VERSION 5.8 ;
BUSBITCHARS "[]" ;
DIVIDERCHAR "/" ;
UNITS
    DATABASE MICRONS 1000 ;
END UNITS

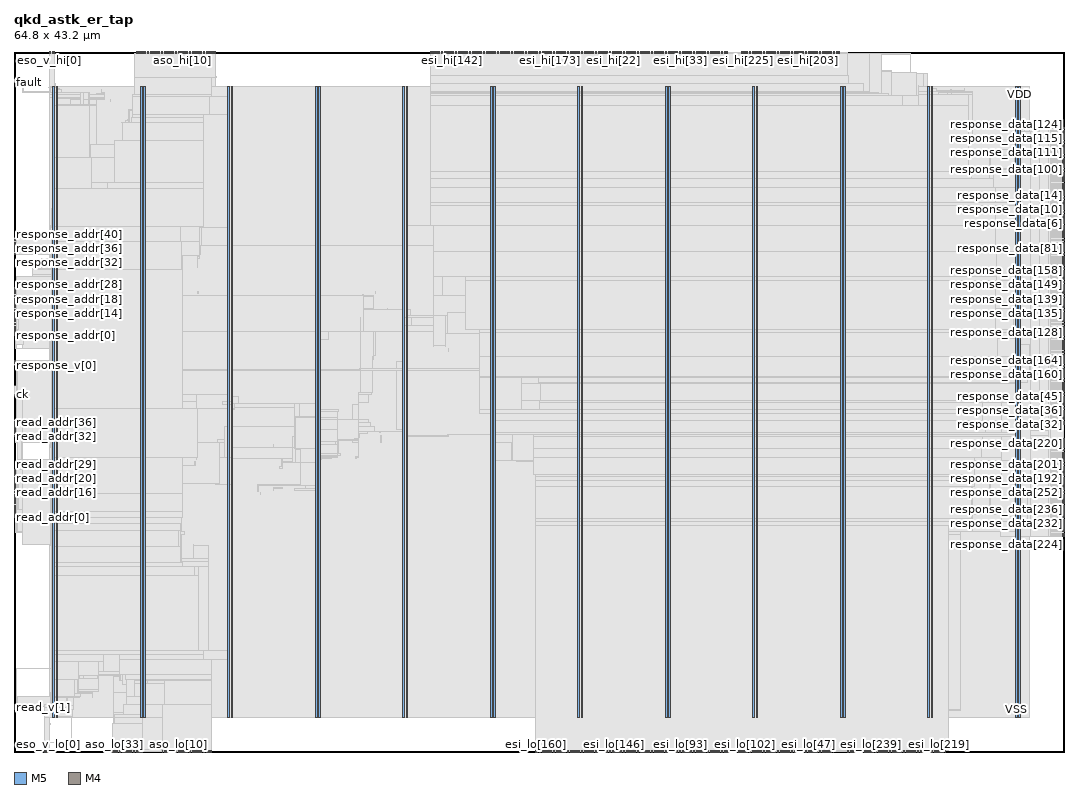
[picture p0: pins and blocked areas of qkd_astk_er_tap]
MACRO qkd_astk_er_tap
  FOREIGN qkd_astk_er_tap 0 0 ;
  CLASS BLOCK ;
  SIZE 64.8 BY 43.2 ;
  PIN aso_hi[0]
    DIRECTION OUTPUT ;
    USE SIGNAL ;
    PORT
      LAYER M5 ;
        RECT  9.456 43.116 9.48 43.2 ;
    END
  END aso_hi[0]
  PIN aso_hi[10]
    DIRECTION OUTPUT ;
    USE SIGNAL ;
    PORT
      LAYER M5 ;
        RECT  10.416 43.116 10.44 43.2 ;
    END
  END aso_hi[10]
  PIN aso_hi[11]
    DIRECTION OUTPUT ;
    USE SIGNAL ;
    PORT
      LAYER M5 ;
        RECT  10.512 43.116 10.536 43.2 ;
    END
  END aso_hi[11]
  PIN aso_hi[12]
    DIRECTION OUTPUT ;
    USE SIGNAL ;
    PORT
      LAYER M5 ;
        RECT  10.608 43.116 10.632 43.2 ;
    END
  END aso_hi[12]
  PIN aso_hi[13]
    DIRECTION OUTPUT ;
    USE SIGNAL ;
    PORT
      LAYER M5 ;
        RECT  10.704 43.116 10.728 43.2 ;
    END
  END aso_hi[13]
  PIN aso_hi[14]
    DIRECTION OUTPUT ;
    USE SIGNAL ;
    PORT
      LAYER M5 ;
        RECT  10.8 43.116 10.824 43.2 ;
    END
  END aso_hi[14]
  PIN aso_hi[15]
    DIRECTION OUTPUT ;
    USE SIGNAL ;
    PORT
      LAYER M5 ;
        RECT  10.896 43.116 10.92 43.2 ;
    END
  END aso_hi[15]
  PIN aso_hi[16]
    DIRECTION OUTPUT ;
    USE SIGNAL ;
    PORT
      LAYER M5 ;
        RECT  10.992 43.116 11.016 43.2 ;
    END
  END aso_hi[16]
  PIN aso_hi[17]
    DIRECTION OUTPUT ;
    USE SIGNAL ;
    PORT
      LAYER M5 ;
        RECT  11.088 43.116 11.112 43.2 ;
    END
  END aso_hi[17]
  PIN aso_hi[18]
    DIRECTION OUTPUT ;
    USE SIGNAL ;
    PORT
      LAYER M5 ;
        RECT  11.184 43.116 11.208 43.2 ;
    END
  END aso_hi[18]
  PIN aso_hi[19]
    DIRECTION OUTPUT ;
    USE SIGNAL ;
    PORT
      LAYER M5 ;
        RECT  11.28 43.116 11.304 43.2 ;
    END
  END aso_hi[19]
  PIN aso_hi[1]
    DIRECTION OUTPUT ;
    USE SIGNAL ;
    PORT
      LAYER M5 ;
        RECT  9.552 43.116 9.576 43.2 ;
    END
  END aso_hi[1]
  PIN aso_hi[20]
    DIRECTION OUTPUT ;
    USE SIGNAL ;
    PORT
      LAYER M5 ;
        RECT  11.376 43.116 11.4 43.2 ;
    END
  END aso_hi[20]
  PIN aso_hi[21]
    DIRECTION OUTPUT ;
    USE SIGNAL ;
    PORT
      LAYER M5 ;
        RECT  11.472 43.116 11.496 43.2 ;
    END
  END aso_hi[21]
  PIN aso_hi[22]
    DIRECTION OUTPUT ;
    USE SIGNAL ;
    PORT
      LAYER M5 ;
        RECT  11.568 43.116 11.592 43.2 ;
    END
  END aso_hi[22]
  PIN aso_hi[23]
    DIRECTION OUTPUT ;
    USE SIGNAL ;
    PORT
      LAYER M5 ;
        RECT  11.664 43.116 11.688 43.2 ;
    END
  END aso_hi[23]
  PIN aso_hi[24]
    DIRECTION OUTPUT ;
    USE SIGNAL ;
    PORT
      LAYER M5 ;
        RECT  11.76 43.116 11.784 43.2 ;
    END
  END aso_hi[24]
  PIN aso_hi[25]
    DIRECTION OUTPUT ;
    USE SIGNAL ;
    PORT
      LAYER M5 ;
        RECT  11.856 43.116 11.88 43.2 ;
    END
  END aso_hi[25]
  PIN aso_hi[26]
    DIRECTION OUTPUT ;
    USE SIGNAL ;
    PORT
      LAYER M5 ;
        RECT  11.952 43.116 11.976 43.2 ;
    END
  END aso_hi[26]
  PIN aso_hi[27]
    DIRECTION OUTPUT ;
    USE SIGNAL ;
    PORT
      LAYER M5 ;
        RECT  12.048 43.116 12.072 43.2 ;
    END
  END aso_hi[27]
  PIN aso_hi[28]
    DIRECTION OUTPUT ;
    USE SIGNAL ;
    PORT
      LAYER M5 ;
        RECT  12.144 43.116 12.168 43.2 ;
    END
  END aso_hi[28]
  PIN aso_hi[29]
    DIRECTION OUTPUT ;
    USE SIGNAL ;
    PORT
      LAYER M5 ;
        RECT  12.24 43.116 12.264 43.2 ;
    END
  END aso_hi[29]
  PIN aso_hi[2]
    DIRECTION OUTPUT ;
    USE SIGNAL ;
    PORT
      LAYER M5 ;
        RECT  9.648 43.116 9.672 43.2 ;
    END
  END aso_hi[2]
  PIN aso_hi[30]
    DIRECTION OUTPUT ;
    USE SIGNAL ;
    PORT
      LAYER M5 ;
        RECT  12.336 43.116 12.36 43.2 ;
    END
  END aso_hi[30]
  PIN aso_hi[31]
    DIRECTION OUTPUT ;
    USE SIGNAL ;
    PORT
      LAYER M5 ;
        RECT  12.432 43.116 12.456 43.2 ;
    END
  END aso_hi[31]
  PIN aso_hi[32]
    DIRECTION OUTPUT ;
    USE SIGNAL ;
    PORT
      LAYER M5 ;
        RECT  7.536 43.116 7.56 43.2 ;
    END
  END aso_hi[32]
  PIN aso_hi[33]
    DIRECTION OUTPUT ;
    USE SIGNAL ;
    PORT
      LAYER M5 ;
        RECT  7.632 43.116 7.656 43.2 ;
    END
  END aso_hi[33]
  PIN aso_hi[34]
    DIRECTION OUTPUT ;
    USE SIGNAL ;
    PORT
      LAYER M5 ;
        RECT  7.728 43.116 7.752 43.2 ;
    END
  END aso_hi[34]
  PIN aso_hi[35]
    DIRECTION OUTPUT ;
    USE SIGNAL ;
    PORT
      LAYER M5 ;
        RECT  7.824 43.116 7.848 43.2 ;
    END
  END aso_hi[35]
  PIN aso_hi[36]
    DIRECTION OUTPUT ;
    USE SIGNAL ;
    PORT
      LAYER M5 ;
        RECT  7.92 43.116 7.944 43.2 ;
    END
  END aso_hi[36]
  PIN aso_hi[37]
    DIRECTION OUTPUT ;
    USE SIGNAL ;
    PORT
      LAYER M5 ;
        RECT  8.016 43.116 8.04 43.2 ;
    END
  END aso_hi[37]
  PIN aso_hi[38]
    DIRECTION OUTPUT ;
    USE SIGNAL ;
    PORT
      LAYER M5 ;
        RECT  8.112 43.116 8.136 43.2 ;
    END
  END aso_hi[38]
  PIN aso_hi[39]
    DIRECTION OUTPUT ;
    USE SIGNAL ;
    PORT
      LAYER M5 ;
        RECT  8.208 43.116 8.232 43.2 ;
    END
  END aso_hi[39]
  PIN aso_hi[3]
    DIRECTION OUTPUT ;
    USE SIGNAL ;
    PORT
      LAYER M5 ;
        RECT  9.744 43.116 9.768 43.2 ;
    END
  END aso_hi[3]
  PIN aso_hi[40]
    DIRECTION OUTPUT ;
    USE SIGNAL ;
    PORT
      LAYER M5 ;
        RECT  8.304 43.116 8.328 43.2 ;
    END
  END aso_hi[40]
  PIN aso_hi[41]
    DIRECTION OUTPUT ;
    USE SIGNAL ;
    PORT
      LAYER M5 ;
        RECT  8.4 43.116 8.424 43.2 ;
    END
  END aso_hi[41]
  PIN aso_hi[42]
    DIRECTION OUTPUT ;
    USE SIGNAL ;
    PORT
      LAYER M5 ;
        RECT  8.496 43.116 8.52 43.2 ;
    END
  END aso_hi[42]
  PIN aso_hi[43]
    DIRECTION OUTPUT ;
    USE SIGNAL ;
    PORT
      LAYER M5 ;
        RECT  8.592 43.116 8.616 43.2 ;
    END
  END aso_hi[43]
  PIN aso_hi[44]
    DIRECTION OUTPUT ;
    USE SIGNAL ;
    PORT
      LAYER M5 ;
        RECT  8.688 43.116 8.712 43.2 ;
    END
  END aso_hi[44]
  PIN aso_hi[45]
    DIRECTION OUTPUT ;
    USE SIGNAL ;
    PORT
      LAYER M5 ;
        RECT  8.784 43.116 8.808 43.2 ;
    END
  END aso_hi[45]
  PIN aso_hi[46]
    DIRECTION OUTPUT ;
    USE SIGNAL ;
    PORT
      LAYER M5 ;
        RECT  8.88 43.116 8.904 43.2 ;
    END
  END aso_hi[46]
  PIN aso_hi[47]
    DIRECTION OUTPUT ;
    USE SIGNAL ;
    PORT
      LAYER M5 ;
        RECT  8.976 43.116 9 43.2 ;
    END
  END aso_hi[47]
  PIN aso_hi[48]
    DIRECTION OUTPUT ;
    USE SIGNAL ;
    PORT
      LAYER M5 ;
        RECT  9.072 43.116 9.096 43.2 ;
    END
  END aso_hi[48]
  PIN aso_hi[49]
    DIRECTION OUTPUT ;
    USE SIGNAL ;
    PORT
      LAYER M5 ;
        RECT  9.168 43.116 9.192 43.2 ;
    END
  END aso_hi[49]
  PIN aso_hi[4]
    DIRECTION OUTPUT ;
    USE SIGNAL ;
    PORT
      LAYER M5 ;
        RECT  9.84 43.116 9.864 43.2 ;
    END
  END aso_hi[4]
  PIN aso_hi[50]
    DIRECTION OUTPUT ;
    USE SIGNAL ;
    PORT
      LAYER M5 ;
        RECT  9.264 43.116 9.288 43.2 ;
    END
  END aso_hi[50]
  PIN aso_hi[51]
    DIRECTION OUTPUT ;
    USE SIGNAL ;
    PORT
      LAYER M5 ;
        RECT  9.36 43.116 9.384 43.2 ;
    END
  END aso_hi[51]
  PIN aso_hi[5]
    DIRECTION OUTPUT ;
    USE SIGNAL ;
    PORT
      LAYER M5 ;
        RECT  9.936 43.116 9.96 43.2 ;
    END
  END aso_hi[5]
  PIN aso_hi[6]
    DIRECTION OUTPUT ;
    USE SIGNAL ;
    PORT
      LAYER M5 ;
        RECT  10.032 43.116 10.056 43.2 ;
    END
  END aso_hi[6]
  PIN aso_hi[7]
    DIRECTION OUTPUT ;
    USE SIGNAL ;
    PORT
      LAYER M5 ;
        RECT  10.128 43.116 10.152 43.2 ;
    END
  END aso_hi[7]
  PIN aso_hi[8]
    DIRECTION OUTPUT ;
    USE SIGNAL ;
    PORT
      LAYER M5 ;
        RECT  10.224 43.116 10.248 43.2 ;
    END
  END aso_hi[8]
  PIN aso_hi[9]
    DIRECTION OUTPUT ;
    USE SIGNAL ;
    PORT
      LAYER M5 ;
        RECT  10.32 43.116 10.344 43.2 ;
    END
  END aso_hi[9]
  PIN aso_lo[0]
    DIRECTION OUTPUT ;
    USE SIGNAL ;
    PORT
      LAYER M5 ;
        RECT  9.168 0 9.192 0.084 ;
    END
  END aso_lo[0]
  PIN aso_lo[10]
    DIRECTION OUTPUT ;
    USE SIGNAL ;
    PORT
      LAYER M5 ;
        RECT  10.128 0 10.152 0.084 ;
    END
  END aso_lo[10]
  PIN aso_lo[11]
    DIRECTION OUTPUT ;
    USE SIGNAL ;
    PORT
      LAYER M5 ;
        RECT  10.224 0 10.248 0.084 ;
    END
  END aso_lo[11]
  PIN aso_lo[12]
    DIRECTION OUTPUT ;
    USE SIGNAL ;
    PORT
      LAYER M5 ;
        RECT  10.32 0 10.344 0.084 ;
    END
  END aso_lo[12]
  PIN aso_lo[13]
    DIRECTION OUTPUT ;
    USE SIGNAL ;
    PORT
      LAYER M5 ;
        RECT  10.416 0 10.44 0.084 ;
    END
  END aso_lo[13]
  PIN aso_lo[14]
    DIRECTION OUTPUT ;
    USE SIGNAL ;
    PORT
      LAYER M5 ;
        RECT  10.512 0 10.536 0.084 ;
    END
  END aso_lo[14]
  PIN aso_lo[15]
    DIRECTION OUTPUT ;
    USE SIGNAL ;
    PORT
      LAYER M5 ;
        RECT  10.608 0 10.632 0.084 ;
    END
  END aso_lo[15]
  PIN aso_lo[16]
    DIRECTION OUTPUT ;
    USE SIGNAL ;
    PORT
      LAYER M5 ;
        RECT  10.704 0 10.728 0.084 ;
    END
  END aso_lo[16]
  PIN aso_lo[17]
    DIRECTION OUTPUT ;
    USE SIGNAL ;
    PORT
      LAYER M5 ;
        RECT  10.8 0 10.824 0.084 ;
    END
  END aso_lo[17]
  PIN aso_lo[18]
    DIRECTION OUTPUT ;
    USE SIGNAL ;
    PORT
      LAYER M5 ;
        RECT  10.896 0 10.92 0.084 ;
    END
  END aso_lo[18]
  PIN aso_lo[19]
    DIRECTION OUTPUT ;
    USE SIGNAL ;
    PORT
      LAYER M5 ;
        RECT  10.992 0 11.016 0.084 ;
    END
  END aso_lo[19]
  PIN aso_lo[1]
    DIRECTION OUTPUT ;
    USE SIGNAL ;
    PORT
      LAYER M5 ;
        RECT  9.264 0 9.288 0.084 ;
    END
  END aso_lo[1]
  PIN aso_lo[20]
    DIRECTION OUTPUT ;
    USE SIGNAL ;
    PORT
      LAYER M5 ;
        RECT  11.088 0 11.112 0.084 ;
    END
  END aso_lo[20]
  PIN aso_lo[21]
    DIRECTION OUTPUT ;
    USE SIGNAL ;
    PORT
      LAYER M5 ;
        RECT  11.184 0 11.208 0.084 ;
    END
  END aso_lo[21]
  PIN aso_lo[22]
    DIRECTION OUTPUT ;
    USE SIGNAL ;
    PORT
      LAYER M5 ;
        RECT  11.28 0 11.304 0.084 ;
    END
  END aso_lo[22]
  PIN aso_lo[23]
    DIRECTION OUTPUT ;
    USE SIGNAL ;
    PORT
      LAYER M5 ;
        RECT  11.376 0 11.4 0.084 ;
    END
  END aso_lo[23]
  PIN aso_lo[24]
    DIRECTION OUTPUT ;
    USE SIGNAL ;
    PORT
      LAYER M5 ;
        RECT  11.472 0 11.496 0.084 ;
    END
  END aso_lo[24]
  PIN aso_lo[25]
    DIRECTION OUTPUT ;
    USE SIGNAL ;
    PORT
      LAYER M5 ;
        RECT  11.568 0 11.592 0.084 ;
    END
  END aso_lo[25]
  PIN aso_lo[26]
    DIRECTION OUTPUT ;
    USE SIGNAL ;
    PORT
      LAYER M5 ;
        RECT  11.664 0 11.688 0.084 ;
    END
  END aso_lo[26]
  PIN aso_lo[27]
    DIRECTION OUTPUT ;
    USE SIGNAL ;
    PORT
      LAYER M5 ;
        RECT  11.76 0 11.784 0.084 ;
    END
  END aso_lo[27]
  PIN aso_lo[28]
    DIRECTION OUTPUT ;
    USE SIGNAL ;
    PORT
      LAYER M5 ;
        RECT  11.856 0 11.88 0.084 ;
    END
  END aso_lo[28]
  PIN aso_lo[29]
    DIRECTION OUTPUT ;
    USE SIGNAL ;
    PORT
      LAYER M5 ;
        RECT  11.952 0 11.976 0.084 ;
    END
  END aso_lo[29]
  PIN aso_lo[2]
    DIRECTION OUTPUT ;
    USE SIGNAL ;
    PORT
      LAYER M5 ;
        RECT  9.36 0 9.384 0.084 ;
    END
  END aso_lo[2]
  PIN aso_lo[30]
    DIRECTION OUTPUT ;
    USE SIGNAL ;
    PORT
      LAYER M5 ;
        RECT  12.048 0 12.072 0.084 ;
    END
  END aso_lo[30]
  PIN aso_lo[31]
    DIRECTION OUTPUT ;
    USE SIGNAL ;
    PORT
      LAYER M5 ;
        RECT  12.144 0 12.168 0.084 ;
    END
  END aso_lo[31]
  PIN aso_lo[32]
    DIRECTION OUTPUT ;
    USE SIGNAL ;
    PORT
      LAYER M5 ;
        RECT  6.096 0 6.12 0.084 ;
    END
  END aso_lo[32]
  PIN aso_lo[33]
    DIRECTION OUTPUT ;
    USE SIGNAL ;
    PORT
      LAYER M5 ;
        RECT  6.192 0 6.216 0.084 ;
    END
  END aso_lo[33]
  PIN aso_lo[34]
    DIRECTION OUTPUT ;
    USE SIGNAL ;
    PORT
      LAYER M5 ;
        RECT  6.288 0 6.312 0.084 ;
    END
  END aso_lo[34]
  PIN aso_lo[35]
    DIRECTION OUTPUT ;
    USE SIGNAL ;
    PORT
      LAYER M5 ;
        RECT  6.384 0 6.408 0.084 ;
    END
  END aso_lo[35]
  PIN aso_lo[36]
    DIRECTION OUTPUT ;
    USE SIGNAL ;
    PORT
      LAYER M5 ;
        RECT  6.48 0 6.504 0.084 ;
    END
  END aso_lo[36]
  PIN aso_lo[37]
    DIRECTION OUTPUT ;
    USE SIGNAL ;
    PORT
      LAYER M5 ;
        RECT  6.576 0 6.6 0.084 ;
    END
  END aso_lo[37]
  PIN aso_lo[38]
    DIRECTION OUTPUT ;
    USE SIGNAL ;
    PORT
      LAYER M5 ;
        RECT  6.672 0 6.696 0.084 ;
    END
  END aso_lo[38]
  PIN aso_lo[39]
    DIRECTION OUTPUT ;
    USE SIGNAL ;
    PORT
      LAYER M5 ;
        RECT  6.768 0 6.792 0.084 ;
    END
  END aso_lo[39]
  PIN aso_lo[3]
    DIRECTION OUTPUT ;
    USE SIGNAL ;
    PORT
      LAYER M5 ;
        RECT  9.456 0 9.48 0.084 ;
    END
  END aso_lo[3]
  PIN aso_lo[40]
    DIRECTION OUTPUT ;
    USE SIGNAL ;
    PORT
      LAYER M5 ;
        RECT  6.864 0 6.888 0.084 ;
    END
  END aso_lo[40]
  PIN aso_lo[41]
    DIRECTION OUTPUT ;
    USE SIGNAL ;
    PORT
      LAYER M5 ;
        RECT  6.96 0 6.984 0.084 ;
    END
  END aso_lo[41]
  PIN aso_lo[42]
    DIRECTION OUTPUT ;
    USE SIGNAL ;
    PORT
      LAYER M5 ;
        RECT  7.056 0 7.08 0.084 ;
    END
  END aso_lo[42]
  PIN aso_lo[43]
    DIRECTION OUTPUT ;
    USE SIGNAL ;
    PORT
      LAYER M5 ;
        RECT  7.152 0 7.176 0.084 ;
    END
  END aso_lo[43]
  PIN aso_lo[44]
    DIRECTION OUTPUT ;
    USE SIGNAL ;
    PORT
      LAYER M5 ;
        RECT  7.248 0 7.272 0.084 ;
    END
  END aso_lo[44]
  PIN aso_lo[45]
    DIRECTION OUTPUT ;
    USE SIGNAL ;
    PORT
      LAYER M5 ;
        RECT  7.344 0 7.368 0.084 ;
    END
  END aso_lo[45]
  PIN aso_lo[46]
    DIRECTION OUTPUT ;
    USE SIGNAL ;
    PORT
      LAYER M5 ;
        RECT  7.44 0 7.464 0.084 ;
    END
  END aso_lo[46]
  PIN aso_lo[47]
    DIRECTION OUTPUT ;
    USE SIGNAL ;
    PORT
      LAYER M5 ;
        RECT  7.536 0 7.56 0.084 ;
    END
  END aso_lo[47]
  PIN aso_lo[48]
    DIRECTION OUTPUT ;
    USE SIGNAL ;
    PORT
      LAYER M5 ;
        RECT  7.632 0 7.656 0.084 ;
    END
  END aso_lo[48]
  PIN aso_lo[49]
    DIRECTION OUTPUT ;
    USE SIGNAL ;
    PORT
      LAYER M5 ;
        RECT  7.728 0 7.752 0.084 ;
    END
  END aso_lo[49]
  PIN aso_lo[4]
    DIRECTION OUTPUT ;
    USE SIGNAL ;
    PORT
      LAYER M5 ;
        RECT  9.552 0 9.576 0.084 ;
    END
  END aso_lo[4]
  PIN aso_lo[50]
    DIRECTION OUTPUT ;
    USE SIGNAL ;
    PORT
      LAYER M5 ;
        RECT  7.824 0 7.848 0.084 ;
    END
  END aso_lo[50]
  PIN aso_lo[51]
    DIRECTION OUTPUT ;
    USE SIGNAL ;
    PORT
      LAYER M5 ;
        RECT  7.92 0 7.944 0.084 ;
    END
  END aso_lo[51]
  PIN aso_lo[5]
    DIRECTION OUTPUT ;
    USE SIGNAL ;
    PORT
      LAYER M5 ;
        RECT  9.648 0 9.672 0.084 ;
    END
  END aso_lo[5]
  PIN aso_lo[6]
    DIRECTION OUTPUT ;
    USE SIGNAL ;
    PORT
      LAYER M5 ;
        RECT  9.744 0 9.768 0.084 ;
    END
  END aso_lo[6]
  PIN aso_lo[7]
    DIRECTION OUTPUT ;
    USE SIGNAL ;
    PORT
      LAYER M5 ;
        RECT  9.84 0 9.864 0.084 ;
    END
  END aso_lo[7]
  PIN aso_lo[8]
    DIRECTION OUTPUT ;
    USE SIGNAL ;
    PORT
      LAYER M5 ;
        RECT  9.936 0 9.96 0.084 ;
    END
  END aso_lo[8]
  PIN aso_lo[9]
    DIRECTION OUTPUT ;
    USE SIGNAL ;
    PORT
      LAYER M5 ;
        RECT  10.032 0 10.056 0.084 ;
    END
  END aso_lo[9]
  PIN ck
    DIRECTION INPUT ;
    USE SIGNAL ;
    PORT
      LAYER M4 ;
        RECT  0 22.032 0.084 22.056 ;
    END
  END ck
  PIN esi_hi[0]
    DIRECTION INPUT ;
    USE SIGNAL ;
    PORT
      LAYER M5 ;
        RECT  34.896 43.116 34.92 43.2 ;
    END
  END esi_hi[0]
  PIN esi_hi[100]
    DIRECTION INPUT ;
    USE SIGNAL ;
    PORT
      LAYER M5 ;
        RECT  29.136 43.116 29.16 43.2 ;
    END
  END esi_hi[100]
  PIN esi_hi[101]
    DIRECTION INPUT ;
    USE SIGNAL ;
    PORT
      LAYER M5 ;
        RECT  29.232 43.116 29.256 43.2 ;
    END
  END esi_hi[101]
  PIN esi_hi[102]
    DIRECTION INPUT ;
    USE SIGNAL ;
    PORT
      LAYER M5 ;
        RECT  29.328 43.116 29.352 43.2 ;
    END
  END esi_hi[102]
  PIN esi_hi[103]
    DIRECTION INPUT ;
    USE SIGNAL ;
    PORT
      LAYER M5 ;
        RECT  29.424 43.116 29.448 43.2 ;
    END
  END esi_hi[103]
  PIN esi_hi[104]
    DIRECTION INPUT ;
    USE SIGNAL ;
    PORT
      LAYER M5 ;
        RECT  29.52 43.116 29.544 43.2 ;
    END
  END esi_hi[104]
  PIN esi_hi[105]
    DIRECTION INPUT ;
    USE SIGNAL ;
    PORT
      LAYER M5 ;
        RECT  29.616 43.116 29.64 43.2 ;
    END
  END esi_hi[105]
  PIN esi_hi[106]
    DIRECTION INPUT ;
    USE SIGNAL ;
    PORT
      LAYER M5 ;
        RECT  29.712 43.116 29.736 43.2 ;
    END
  END esi_hi[106]
  PIN esi_hi[107]
    DIRECTION INPUT ;
    USE SIGNAL ;
    PORT
      LAYER M5 ;
        RECT  29.808 43.116 29.832 43.2 ;
    END
  END esi_hi[107]
  PIN esi_hi[108]
    DIRECTION INPUT ;
    USE SIGNAL ;
    PORT
      LAYER M5 ;
        RECT  29.904 43.116 29.928 43.2 ;
    END
  END esi_hi[108]
  PIN esi_hi[109]
    DIRECTION INPUT ;
    USE SIGNAL ;
    PORT
      LAYER M5 ;
        RECT  30 43.116 30.024 43.2 ;
    END
  END esi_hi[109]
  PIN esi_hi[10]
    DIRECTION INPUT ;
    USE SIGNAL ;
    PORT
      LAYER M5 ;
        RECT  35.856 43.116 35.88 43.2 ;
    END
  END esi_hi[10]
  PIN esi_hi[110]
    DIRECTION INPUT ;
    USE SIGNAL ;
    PORT
      LAYER M5 ;
        RECT  30.096 43.116 30.12 43.2 ;
    END
  END esi_hi[110]
  PIN esi_hi[111]
    DIRECTION INPUT ;
    USE SIGNAL ;
    PORT
      LAYER M5 ;
        RECT  30.192 43.116 30.216 43.2 ;
    END
  END esi_hi[111]
  PIN esi_hi[112]
    DIRECTION INPUT ;
    USE SIGNAL ;
    PORT
      LAYER M5 ;
        RECT  30.288 43.116 30.312 43.2 ;
    END
  END esi_hi[112]
  PIN esi_hi[113]
    DIRECTION INPUT ;
    USE SIGNAL ;
    PORT
      LAYER M5 ;
        RECT  30.384 43.116 30.408 43.2 ;
    END
  END esi_hi[113]
  PIN esi_hi[114]
    DIRECTION INPUT ;
    USE SIGNAL ;
    PORT
      LAYER M5 ;
        RECT  30.48 43.116 30.504 43.2 ;
    END
  END esi_hi[114]
  PIN esi_hi[115]
    DIRECTION INPUT ;
    USE SIGNAL ;
    PORT
      LAYER M5 ;
        RECT  30.576 43.116 30.6 43.2 ;
    END
  END esi_hi[115]
  PIN esi_hi[116]
    DIRECTION INPUT ;
    USE SIGNAL ;
    PORT
      LAYER M5 ;
        RECT  30.672 43.116 30.696 43.2 ;
    END
  END esi_hi[116]
  PIN esi_hi[117]
    DIRECTION INPUT ;
    USE SIGNAL ;
    PORT
      LAYER M5 ;
        RECT  30.768 43.116 30.792 43.2 ;
    END
  END esi_hi[117]
  PIN esi_hi[118]
    DIRECTION INPUT ;
    USE SIGNAL ;
    PORT
      LAYER M5 ;
        RECT  30.864 43.116 30.888 43.2 ;
    END
  END esi_hi[118]
  PIN esi_hi[119]
    DIRECTION INPUT ;
    USE SIGNAL ;
    PORT
      LAYER M5 ;
        RECT  30.96 43.116 30.984 43.2 ;
    END
  END esi_hi[119]
  PIN esi_hi[11]
    DIRECTION INPUT ;
    USE SIGNAL ;
    PORT
      LAYER M5 ;
        RECT  35.952 43.116 35.976 43.2 ;
    END
  END esi_hi[11]
  PIN esi_hi[120]
    DIRECTION INPUT ;
    USE SIGNAL ;
    PORT
      LAYER M5 ;
        RECT  31.056 43.116 31.08 43.2 ;
    END
  END esi_hi[120]
  PIN esi_hi[121]
    DIRECTION INPUT ;
    USE SIGNAL ;
    PORT
      LAYER M5 ;
        RECT  31.152 43.116 31.176 43.2 ;
    END
  END esi_hi[121]
  PIN esi_hi[122]
    DIRECTION INPUT ;
    USE SIGNAL ;
    PORT
      LAYER M5 ;
        RECT  31.248 43.116 31.272 43.2 ;
    END
  END esi_hi[122]
  PIN esi_hi[123]
    DIRECTION INPUT ;
    USE SIGNAL ;
    PORT
      LAYER M5 ;
        RECT  31.344 43.116 31.368 43.2 ;
    END
  END esi_hi[123]
  PIN esi_hi[124]
    DIRECTION INPUT ;
    USE SIGNAL ;
    PORT
      LAYER M5 ;
        RECT  31.44 43.116 31.464 43.2 ;
    END
  END esi_hi[124]
  PIN esi_hi[125]
    DIRECTION INPUT ;
    USE SIGNAL ;
    PORT
      LAYER M5 ;
        RECT  31.536 43.116 31.56 43.2 ;
    END
  END esi_hi[125]
  PIN esi_hi[126]
    DIRECTION INPUT ;
    USE SIGNAL ;
    PORT
      LAYER M5 ;
        RECT  31.632 43.116 31.656 43.2 ;
    END
  END esi_hi[126]
  PIN esi_hi[127]
    DIRECTION INPUT ;
    USE SIGNAL ;
    PORT
      LAYER M5 ;
        RECT  31.728 43.116 31.752 43.2 ;
    END
  END esi_hi[127]
  PIN esi_hi[128]
    DIRECTION INPUT ;
    USE SIGNAL ;
    PORT
      LAYER M5 ;
        RECT  25.68 43.116 25.704 43.2 ;
    END
  END esi_hi[128]
  PIN esi_hi[129]
    DIRECTION INPUT ;
    USE SIGNAL ;
    PORT
      LAYER M5 ;
        RECT  25.776 43.116 25.8 43.2 ;
    END
  END esi_hi[129]
  PIN esi_hi[12]
    DIRECTION INPUT ;
    USE SIGNAL ;
    PORT
      LAYER M5 ;
        RECT  36.048 43.116 36.072 43.2 ;
    END
  END esi_hi[12]
  PIN esi_hi[130]
    DIRECTION INPUT ;
    USE SIGNAL ;
    PORT
      LAYER M5 ;
        RECT  25.872 43.116 25.896 43.2 ;
    END
  END esi_hi[130]
  PIN esi_hi[131]
    DIRECTION INPUT ;
    USE SIGNAL ;
    PORT
      LAYER M5 ;
        RECT  25.968 43.116 25.992 43.2 ;
    END
  END esi_hi[131]
  PIN esi_hi[132]
    DIRECTION INPUT ;
    USE SIGNAL ;
    PORT
      LAYER M5 ;
        RECT  26.064 43.116 26.088 43.2 ;
    END
  END esi_hi[132]
  PIN esi_hi[133]
    DIRECTION INPUT ;
    USE SIGNAL ;
    PORT
      LAYER M5 ;
        RECT  26.16 43.116 26.184 43.2 ;
    END
  END esi_hi[133]
  PIN esi_hi[134]
    DIRECTION INPUT ;
    USE SIGNAL ;
    PORT
      LAYER M5 ;
        RECT  26.256 43.116 26.28 43.2 ;
    END
  END esi_hi[134]
  PIN esi_hi[135]
    DIRECTION INPUT ;
    USE SIGNAL ;
    PORT
      LAYER M5 ;
        RECT  26.352 43.116 26.376 43.2 ;
    END
  END esi_hi[135]
  PIN esi_hi[136]
    DIRECTION INPUT ;
    USE SIGNAL ;
    PORT
      LAYER M5 ;
        RECT  26.448 43.116 26.472 43.2 ;
    END
  END esi_hi[136]
  PIN esi_hi[137]
    DIRECTION INPUT ;
    USE SIGNAL ;
    PORT
      LAYER M5 ;
        RECT  26.544 43.116 26.568 43.2 ;
    END
  END esi_hi[137]
  PIN esi_hi[138]
    DIRECTION INPUT ;
    USE SIGNAL ;
    PORT
      LAYER M5 ;
        RECT  26.64 43.116 26.664 43.2 ;
    END
  END esi_hi[138]
  PIN esi_hi[139]
    DIRECTION INPUT ;
    USE SIGNAL ;
    PORT
      LAYER M5 ;
        RECT  26.736 43.116 26.76 43.2 ;
    END
  END esi_hi[139]
  PIN esi_hi[13]
    DIRECTION INPUT ;
    USE SIGNAL ;
    PORT
      LAYER M5 ;
        RECT  36.144 43.116 36.168 43.2 ;
    END
  END esi_hi[13]
  PIN esi_hi[140]
    DIRECTION INPUT ;
    USE SIGNAL ;
    PORT
      LAYER M5 ;
        RECT  26.832 43.116 26.856 43.2 ;
    END
  END esi_hi[140]
  PIN esi_hi[141]
    DIRECTION INPUT ;
    USE SIGNAL ;
    PORT
      LAYER M5 ;
        RECT  26.928 43.116 26.952 43.2 ;
    END
  END esi_hi[141]
  PIN esi_hi[142]
    DIRECTION INPUT ;
    USE SIGNAL ;
    PORT
      LAYER M5 ;
        RECT  27.024 43.116 27.048 43.2 ;
    END
  END esi_hi[142]
  PIN esi_hi[143]
    DIRECTION INPUT ;
    USE SIGNAL ;
    PORT
      LAYER M5 ;
        RECT  27.12 43.116 27.144 43.2 ;
    END
  END esi_hi[143]
  PIN esi_hi[144]
    DIRECTION INPUT ;
    USE SIGNAL ;
    PORT
      LAYER M5 ;
        RECT  27.216 43.116 27.24 43.2 ;
    END
  END esi_hi[144]
  PIN esi_hi[145]
    DIRECTION INPUT ;
    USE SIGNAL ;
    PORT
      LAYER M5 ;
        RECT  27.312 43.116 27.336 43.2 ;
    END
  END esi_hi[145]
  PIN esi_hi[146]
    DIRECTION INPUT ;
    USE SIGNAL ;
    PORT
      LAYER M5 ;
        RECT  27.408 43.116 27.432 43.2 ;
    END
  END esi_hi[146]
  PIN esi_hi[147]
    DIRECTION INPUT ;
    USE SIGNAL ;
    PORT
      LAYER M5 ;
        RECT  27.504 43.116 27.528 43.2 ;
    END
  END esi_hi[147]
  PIN esi_hi[148]
    DIRECTION INPUT ;
    USE SIGNAL ;
    PORT
      LAYER M5 ;
        RECT  27.6 43.116 27.624 43.2 ;
    END
  END esi_hi[148]
  PIN esi_hi[149]
    DIRECTION INPUT ;
    USE SIGNAL ;
    PORT
      LAYER M5 ;
        RECT  27.696 43.116 27.72 43.2 ;
    END
  END esi_hi[149]
  PIN esi_hi[14]
    DIRECTION INPUT ;
    USE SIGNAL ;
    PORT
      LAYER M5 ;
        RECT  36.24 43.116 36.264 43.2 ;
    END
  END esi_hi[14]
  PIN esi_hi[150]
    DIRECTION INPUT ;
    USE SIGNAL ;
    PORT
      LAYER M5 ;
        RECT  27.792 43.116 27.816 43.2 ;
    END
  END esi_hi[150]
  PIN esi_hi[151]
    DIRECTION INPUT ;
    USE SIGNAL ;
    PORT
      LAYER M5 ;
        RECT  27.888 43.116 27.912 43.2 ;
    END
  END esi_hi[151]
  PIN esi_hi[152]
    DIRECTION INPUT ;
    USE SIGNAL ;
    PORT
      LAYER M5 ;
        RECT  27.984 43.116 28.008 43.2 ;
    END
  END esi_hi[152]
  PIN esi_hi[153]
    DIRECTION INPUT ;
    USE SIGNAL ;
    PORT
      LAYER M5 ;
        RECT  28.08 43.116 28.104 43.2 ;
    END
  END esi_hi[153]
  PIN esi_hi[154]
    DIRECTION INPUT ;
    USE SIGNAL ;
    PORT
      LAYER M5 ;
        RECT  28.176 43.116 28.2 43.2 ;
    END
  END esi_hi[154]
  PIN esi_hi[155]
    DIRECTION INPUT ;
    USE SIGNAL ;
    PORT
      LAYER M5 ;
        RECT  28.272 43.116 28.296 43.2 ;
    END
  END esi_hi[155]
  PIN esi_hi[156]
    DIRECTION INPUT ;
    USE SIGNAL ;
    PORT
      LAYER M5 ;
        RECT  28.368 43.116 28.392 43.2 ;
    END
  END esi_hi[156]
  PIN esi_hi[157]
    DIRECTION INPUT ;
    USE SIGNAL ;
    PORT
      LAYER M5 ;
        RECT  28.464 43.116 28.488 43.2 ;
    END
  END esi_hi[157]
  PIN esi_hi[158]
    DIRECTION INPUT ;
    USE SIGNAL ;
    PORT
      LAYER M5 ;
        RECT  28.56 43.116 28.584 43.2 ;
    END
  END esi_hi[158]
  PIN esi_hi[159]
    DIRECTION INPUT ;
    USE SIGNAL ;
    PORT
      LAYER M5 ;
        RECT  28.656 43.116 28.68 43.2 ;
    END
  END esi_hi[159]
  PIN esi_hi[15]
    DIRECTION INPUT ;
    USE SIGNAL ;
    PORT
      LAYER M5 ;
        RECT  36.336 43.116 36.36 43.2 ;
    END
  END esi_hi[15]
  PIN esi_hi[160]
    DIRECTION INPUT ;
    USE SIGNAL ;
    PORT
      LAYER M5 ;
        RECT  31.824 43.116 31.848 43.2 ;
    END
  END esi_hi[160]
  PIN esi_hi[161]
    DIRECTION INPUT ;
    USE SIGNAL ;
    PORT
      LAYER M5 ;
        RECT  31.92 43.116 31.944 43.2 ;
    END
  END esi_hi[161]
  PIN esi_hi[162]
    DIRECTION INPUT ;
    USE SIGNAL ;
    PORT
      LAYER M5 ;
        RECT  32.016 43.116 32.04 43.2 ;
    END
  END esi_hi[162]
  PIN esi_hi[163]
    DIRECTION INPUT ;
    USE SIGNAL ;
    PORT
      LAYER M5 ;
        RECT  32.112 43.116 32.136 43.2 ;
    END
  END esi_hi[163]
  PIN esi_hi[164]
    DIRECTION INPUT ;
    USE SIGNAL ;
    PORT
      LAYER M5 ;
        RECT  32.208 43.116 32.232 43.2 ;
    END
  END esi_hi[164]
  PIN esi_hi[165]
    DIRECTION INPUT ;
    USE SIGNAL ;
    PORT
      LAYER M5 ;
        RECT  32.304 43.116 32.328 43.2 ;
    END
  END esi_hi[165]
  PIN esi_hi[166]
    DIRECTION INPUT ;
    USE SIGNAL ;
    PORT
      LAYER M5 ;
        RECT  32.4 43.116 32.424 43.2 ;
    END
  END esi_hi[166]
  PIN esi_hi[167]
    DIRECTION INPUT ;
    USE SIGNAL ;
    PORT
      LAYER M5 ;
        RECT  32.496 43.116 32.52 43.2 ;
    END
  END esi_hi[167]
  PIN esi_hi[168]
    DIRECTION INPUT ;
    USE SIGNAL ;
    PORT
      LAYER M5 ;
        RECT  32.592 43.116 32.616 43.2 ;
    END
  END esi_hi[168]
  PIN esi_hi[169]
    DIRECTION INPUT ;
    USE SIGNAL ;
    PORT
      LAYER M5 ;
        RECT  32.688 43.116 32.712 43.2 ;
    END
  END esi_hi[169]
  PIN esi_hi[16]
    DIRECTION INPUT ;
    USE SIGNAL ;
    PORT
      LAYER M5 ;
        RECT  36.432 43.116 36.456 43.2 ;
    END
  END esi_hi[16]
  PIN esi_hi[170]
    DIRECTION INPUT ;
    USE SIGNAL ;
    PORT
      LAYER M5 ;
        RECT  32.784 43.116 32.808 43.2 ;
    END
  END esi_hi[170]
  PIN esi_hi[171]
    DIRECTION INPUT ;
    USE SIGNAL ;
    PORT
      LAYER M5 ;
        RECT  32.88 43.116 32.904 43.2 ;
    END
  END esi_hi[171]
  PIN esi_hi[172]
    DIRECTION INPUT ;
    USE SIGNAL ;
    PORT
      LAYER M5 ;
        RECT  32.976 43.116 33 43.2 ;
    END
  END esi_hi[172]
  PIN esi_hi[173]
    DIRECTION INPUT ;
    USE SIGNAL ;
    PORT
      LAYER M5 ;
        RECT  33.072 43.116 33.096 43.2 ;
    END
  END esi_hi[173]
  PIN esi_hi[174]
    DIRECTION INPUT ;
    USE SIGNAL ;
    PORT
      LAYER M5 ;
        RECT  33.168 43.116 33.192 43.2 ;
    END
  END esi_hi[174]
  PIN esi_hi[175]
    DIRECTION INPUT ;
    USE SIGNAL ;
    PORT
      LAYER M5 ;
        RECT  33.264 43.116 33.288 43.2 ;
    END
  END esi_hi[175]
  PIN esi_hi[176]
    DIRECTION INPUT ;
    USE SIGNAL ;
    PORT
      LAYER M5 ;
        RECT  33.36 43.116 33.384 43.2 ;
    END
  END esi_hi[176]
  PIN esi_hi[177]
    DIRECTION INPUT ;
    USE SIGNAL ;
    PORT
      LAYER M5 ;
        RECT  33.456 43.116 33.48 43.2 ;
    END
  END esi_hi[177]
  PIN esi_hi[178]
    DIRECTION INPUT ;
    USE SIGNAL ;
    PORT
      LAYER M5 ;
        RECT  33.552 43.116 33.576 43.2 ;
    END
  END esi_hi[178]
  PIN esi_hi[179]
    DIRECTION INPUT ;
    USE SIGNAL ;
    PORT
      LAYER M5 ;
        RECT  33.648 43.116 33.672 43.2 ;
    END
  END esi_hi[179]
  PIN esi_hi[17]
    DIRECTION INPUT ;
    USE SIGNAL ;
    PORT
      LAYER M5 ;
        RECT  36.528 43.116 36.552 43.2 ;
    END
  END esi_hi[17]
  PIN esi_hi[180]
    DIRECTION INPUT ;
    USE SIGNAL ;
    PORT
      LAYER M5 ;
        RECT  33.744 43.116 33.768 43.2 ;
    END
  END esi_hi[180]
  PIN esi_hi[181]
    DIRECTION INPUT ;
    USE SIGNAL ;
    PORT
      LAYER M5 ;
        RECT  33.84 43.116 33.864 43.2 ;
    END
  END esi_hi[181]
  PIN esi_hi[182]
    DIRECTION INPUT ;
    USE SIGNAL ;
    PORT
      LAYER M5 ;
        RECT  33.936 43.116 33.96 43.2 ;
    END
  END esi_hi[182]
  PIN esi_hi[183]
    DIRECTION INPUT ;
    USE SIGNAL ;
    PORT
      LAYER M5 ;
        RECT  34.032 43.116 34.056 43.2 ;
    END
  END esi_hi[183]
  PIN esi_hi[184]
    DIRECTION INPUT ;
    USE SIGNAL ;
    PORT
      LAYER M5 ;
        RECT  34.128 43.116 34.152 43.2 ;
    END
  END esi_hi[184]
  PIN esi_hi[185]
    DIRECTION INPUT ;
    USE SIGNAL ;
    PORT
      LAYER M5 ;
        RECT  34.224 43.116 34.248 43.2 ;
    END
  END esi_hi[185]
  PIN esi_hi[186]
    DIRECTION INPUT ;
    USE SIGNAL ;
    PORT
      LAYER M5 ;
        RECT  34.32 43.116 34.344 43.2 ;
    END
  END esi_hi[186]
  PIN esi_hi[187]
    DIRECTION INPUT ;
    USE SIGNAL ;
    PORT
      LAYER M5 ;
        RECT  34.416 43.116 34.44 43.2 ;
    END
  END esi_hi[187]
  PIN esi_hi[188]
    DIRECTION INPUT ;
    USE SIGNAL ;
    PORT
      LAYER M5 ;
        RECT  34.512 43.116 34.536 43.2 ;
    END
  END esi_hi[188]
  PIN esi_hi[189]
    DIRECTION INPUT ;
    USE SIGNAL ;
    PORT
      LAYER M5 ;
        RECT  34.608 43.116 34.632 43.2 ;
    END
  END esi_hi[189]
  PIN esi_hi[18]
    DIRECTION INPUT ;
    USE SIGNAL ;
    PORT
      LAYER M5 ;
        RECT  36.624 43.116 36.648 43.2 ;
    END
  END esi_hi[18]
  PIN esi_hi[190]
    DIRECTION INPUT ;
    USE SIGNAL ;
    PORT
      LAYER M5 ;
        RECT  34.704 43.116 34.728 43.2 ;
    END
  END esi_hi[190]
  PIN esi_hi[191]
    DIRECTION INPUT ;
    USE SIGNAL ;
    PORT
      LAYER M5 ;
        RECT  34.8 43.116 34.824 43.2 ;
    END
  END esi_hi[191]
  PIN esi_hi[192]
    DIRECTION INPUT ;
    USE SIGNAL ;
    PORT
      LAYER M5 ;
        RECT  47.952 43.116 47.976 43.2 ;
    END
  END esi_hi[192]
  PIN esi_hi[193]
    DIRECTION INPUT ;
    USE SIGNAL ;
    PORT
      LAYER M5 ;
        RECT  48.048 43.116 48.072 43.2 ;
    END
  END esi_hi[193]
  PIN esi_hi[194]
    DIRECTION INPUT ;
    USE SIGNAL ;
    PORT
      LAYER M5 ;
        RECT  48.144 43.116 48.168 43.2 ;
    END
  END esi_hi[194]
  PIN esi_hi[195]
    DIRECTION INPUT ;
    USE SIGNAL ;
    PORT
      LAYER M5 ;
        RECT  48.24 43.116 48.264 43.2 ;
    END
  END esi_hi[195]
  PIN esi_hi[196]
    DIRECTION INPUT ;
    USE SIGNAL ;
    PORT
      LAYER M5 ;
        RECT  48.336 43.116 48.36 43.2 ;
    END
  END esi_hi[196]
  PIN esi_hi[197]
    DIRECTION INPUT ;
    USE SIGNAL ;
    PORT
      LAYER M5 ;
        RECT  48.432 43.116 48.456 43.2 ;
    END
  END esi_hi[197]
  PIN esi_hi[198]
    DIRECTION INPUT ;
    USE SIGNAL ;
    PORT
      LAYER M5 ;
        RECT  48.528 43.116 48.552 43.2 ;
    END
  END esi_hi[198]
  PIN esi_hi[199]
    DIRECTION INPUT ;
    USE SIGNAL ;
    PORT
      LAYER M5 ;
        RECT  48.624 43.116 48.648 43.2 ;
    END
  END esi_hi[199]
  PIN esi_hi[19]
    DIRECTION INPUT ;
    USE SIGNAL ;
    PORT
      LAYER M5 ;
        RECT  36.72 43.116 36.744 43.2 ;
    END
  END esi_hi[19]
  PIN esi_hi[1]
    DIRECTION INPUT ;
    USE SIGNAL ;
    PORT
      LAYER M5 ;
        RECT  34.992 43.116 35.016 43.2 ;
    END
  END esi_hi[1]
  PIN esi_hi[200]
    DIRECTION INPUT ;
    USE SIGNAL ;
    PORT
      LAYER M5 ;
        RECT  48.72 43.116 48.744 43.2 ;
    END
  END esi_hi[200]
  PIN esi_hi[201]
    DIRECTION INPUT ;
    USE SIGNAL ;
    PORT
      LAYER M5 ;
        RECT  48.816 43.116 48.84 43.2 ;
    END
  END esi_hi[201]
  PIN esi_hi[202]
    DIRECTION INPUT ;
    USE SIGNAL ;
    PORT
      LAYER M5 ;
        RECT  48.912 43.116 48.936 43.2 ;
    END
  END esi_hi[202]
  PIN esi_hi[203]
    DIRECTION INPUT ;
    USE SIGNAL ;
    PORT
      LAYER M5 ;
        RECT  49.008 43.116 49.032 43.2 ;
    END
  END esi_hi[203]
  PIN esi_hi[204]
    DIRECTION INPUT ;
    USE SIGNAL ;
    PORT
      LAYER M5 ;
        RECT  49.104 43.116 49.128 43.2 ;
    END
  END esi_hi[204]
  PIN esi_hi[205]
    DIRECTION INPUT ;
    USE SIGNAL ;
    PORT
      LAYER M5 ;
        RECT  49.2 43.116 49.224 43.2 ;
    END
  END esi_hi[205]
  PIN esi_hi[206]
    DIRECTION INPUT ;
    USE SIGNAL ;
    PORT
      LAYER M5 ;
        RECT  49.296 43.116 49.32 43.2 ;
    END
  END esi_hi[206]
  PIN esi_hi[207]
    DIRECTION INPUT ;
    USE SIGNAL ;
    PORT
      LAYER M5 ;
        RECT  49.392 43.116 49.416 43.2 ;
    END
  END esi_hi[207]
  PIN esi_hi[208]
    DIRECTION INPUT ;
    USE SIGNAL ;
    PORT
      LAYER M5 ;
        RECT  49.488 43.116 49.512 43.2 ;
    END
  END esi_hi[208]
  PIN esi_hi[209]
    DIRECTION INPUT ;
    USE SIGNAL ;
    PORT
      LAYER M5 ;
        RECT  49.584 43.116 49.608 43.2 ;
    END
  END esi_hi[209]
  PIN esi_hi[20]
    DIRECTION INPUT ;
    USE SIGNAL ;
    PORT
      LAYER M5 ;
        RECT  36.816 43.116 36.84 43.2 ;
    END
  END esi_hi[20]
  PIN esi_hi[210]
    DIRECTION INPUT ;
    USE SIGNAL ;
    PORT
      LAYER M5 ;
        RECT  49.68 43.116 49.704 43.2 ;
    END
  END esi_hi[210]
  PIN esi_hi[211]
    DIRECTION INPUT ;
    USE SIGNAL ;
    PORT
      LAYER M5 ;
        RECT  49.776 43.116 49.8 43.2 ;
    END
  END esi_hi[211]
  PIN esi_hi[212]
    DIRECTION INPUT ;
    USE SIGNAL ;
    PORT
      LAYER M5 ;
        RECT  49.872 43.116 49.896 43.2 ;
    END
  END esi_hi[212]
  PIN esi_hi[213]
    DIRECTION INPUT ;
    USE SIGNAL ;
    PORT
      LAYER M5 ;
        RECT  49.968 43.116 49.992 43.2 ;
    END
  END esi_hi[213]
  PIN esi_hi[214]
    DIRECTION INPUT ;
    USE SIGNAL ;
    PORT
      LAYER M5 ;
        RECT  50.064 43.116 50.088 43.2 ;
    END
  END esi_hi[214]
  PIN esi_hi[215]
    DIRECTION INPUT ;
    USE SIGNAL ;
    PORT
      LAYER M5 ;
        RECT  50.16 43.116 50.184 43.2 ;
    END
  END esi_hi[215]
  PIN esi_hi[216]
    DIRECTION INPUT ;
    USE SIGNAL ;
    PORT
      LAYER M5 ;
        RECT  50.256 43.116 50.28 43.2 ;
    END
  END esi_hi[216]
  PIN esi_hi[217]
    DIRECTION INPUT ;
    USE SIGNAL ;
    PORT
      LAYER M5 ;
        RECT  50.352 43.116 50.376 43.2 ;
    END
  END esi_hi[217]
  PIN esi_hi[218]
    DIRECTION INPUT ;
    USE SIGNAL ;
    PORT
      LAYER M5 ;
        RECT  50.448 43.116 50.472 43.2 ;
    END
  END esi_hi[218]
  PIN esi_hi[219]
    DIRECTION INPUT ;
    USE SIGNAL ;
    PORT
      LAYER M5 ;
        RECT  50.544 43.116 50.568 43.2 ;
    END
  END esi_hi[219]
  PIN esi_hi[21]
    DIRECTION INPUT ;
    USE SIGNAL ;
    PORT
      LAYER M5 ;
        RECT  36.912 43.116 36.936 43.2 ;
    END
  END esi_hi[21]
  PIN esi_hi[220]
    DIRECTION INPUT ;
    USE SIGNAL ;
    PORT
      LAYER M5 ;
        RECT  50.64 43.116 50.664 43.2 ;
    END
  END esi_hi[220]
  PIN esi_hi[221]
    DIRECTION INPUT ;
    USE SIGNAL ;
    PORT
      LAYER M5 ;
        RECT  50.736 43.116 50.76 43.2 ;
    END
  END esi_hi[221]
  PIN esi_hi[222]
    DIRECTION INPUT ;
    USE SIGNAL ;
    PORT
      LAYER M5 ;
        RECT  50.832 43.116 50.856 43.2 ;
    END
  END esi_hi[222]
  PIN esi_hi[223]
    DIRECTION INPUT ;
    USE SIGNAL ;
    PORT
      LAYER M5 ;
        RECT  50.928 43.116 50.952 43.2 ;
    END
  END esi_hi[223]
  PIN esi_hi[224]
    DIRECTION INPUT ;
    USE SIGNAL ;
    PORT
      LAYER M5 ;
        RECT  44.88 43.116 44.904 43.2 ;
    END
  END esi_hi[224]
  PIN esi_hi[225]
    DIRECTION INPUT ;
    USE SIGNAL ;
    PORT
      LAYER M5 ;
        RECT  44.976 43.116 45 43.2 ;
    END
  END esi_hi[225]
  PIN esi_hi[226]
    DIRECTION INPUT ;
    USE SIGNAL ;
    PORT
      LAYER M5 ;
        RECT  45.072 43.116 45.096 43.2 ;
    END
  END esi_hi[226]
  PIN esi_hi[227]
    DIRECTION INPUT ;
    USE SIGNAL ;
    PORT
      LAYER M5 ;
        RECT  45.168 43.116 45.192 43.2 ;
    END
  END esi_hi[227]
  PIN esi_hi[228]
    DIRECTION INPUT ;
    USE SIGNAL ;
    PORT
      LAYER M5 ;
        RECT  45.264 43.116 45.288 43.2 ;
    END
  END esi_hi[228]
  PIN esi_hi[229]
    DIRECTION INPUT ;
    USE SIGNAL ;
    PORT
      LAYER M5 ;
        RECT  45.36 43.116 45.384 43.2 ;
    END
  END esi_hi[229]
  PIN esi_hi[22]
    DIRECTION INPUT ;
    USE SIGNAL ;
    PORT
      LAYER M5 ;
        RECT  37.008 43.116 37.032 43.2 ;
    END
  END esi_hi[22]
  PIN esi_hi[230]
    DIRECTION INPUT ;
    USE SIGNAL ;
    PORT
      LAYER M5 ;
        RECT  45.456 43.116 45.48 43.2 ;
    END
  END esi_hi[230]
  PIN esi_hi[231]
    DIRECTION INPUT ;
    USE SIGNAL ;
    PORT
      LAYER M5 ;
        RECT  45.552 43.116 45.576 43.2 ;
    END
  END esi_hi[231]
  PIN esi_hi[232]
    DIRECTION INPUT ;
    USE SIGNAL ;
    PORT
      LAYER M5 ;
        RECT  45.648 43.116 45.672 43.2 ;
    END
  END esi_hi[232]
  PIN esi_hi[233]
    DIRECTION INPUT ;
    USE SIGNAL ;
    PORT
      LAYER M5 ;
        RECT  45.744 43.116 45.768 43.2 ;
    END
  END esi_hi[233]
  PIN esi_hi[234]
    DIRECTION INPUT ;
    USE SIGNAL ;
    PORT
      LAYER M5 ;
        RECT  45.84 43.116 45.864 43.2 ;
    END
  END esi_hi[234]
  PIN esi_hi[235]
    DIRECTION INPUT ;
    USE SIGNAL ;
    PORT
      LAYER M5 ;
        RECT  45.936 43.116 45.96 43.2 ;
    END
  END esi_hi[235]
  PIN esi_hi[236]
    DIRECTION INPUT ;
    USE SIGNAL ;
    PORT
      LAYER M5 ;
        RECT  46.032 43.116 46.056 43.2 ;
    END
  END esi_hi[236]
  PIN esi_hi[237]
    DIRECTION INPUT ;
    USE SIGNAL ;
    PORT
      LAYER M5 ;
        RECT  46.128 43.116 46.152 43.2 ;
    END
  END esi_hi[237]
  PIN esi_hi[238]
    DIRECTION INPUT ;
    USE SIGNAL ;
    PORT
      LAYER M5 ;
        RECT  46.224 43.116 46.248 43.2 ;
    END
  END esi_hi[238]
  PIN esi_hi[239]
    DIRECTION INPUT ;
    USE SIGNAL ;
    PORT
      LAYER M5 ;
        RECT  46.32 43.116 46.344 43.2 ;
    END
  END esi_hi[239]
  PIN esi_hi[23]
    DIRECTION INPUT ;
    USE SIGNAL ;
    PORT
      LAYER M5 ;
        RECT  37.104 43.116 37.128 43.2 ;
    END
  END esi_hi[23]
  PIN esi_hi[240]
    DIRECTION INPUT ;
    USE SIGNAL ;
    PORT
      LAYER M5 ;
        RECT  46.416 43.116 46.44 43.2 ;
    END
  END esi_hi[240]
  PIN esi_hi[241]
    DIRECTION INPUT ;
    USE SIGNAL ;
    PORT
      LAYER M5 ;
        RECT  46.512 43.116 46.536 43.2 ;
    END
  END esi_hi[241]
  PIN esi_hi[242]
    DIRECTION INPUT ;
    USE SIGNAL ;
    PORT
      LAYER M5 ;
        RECT  46.608 43.116 46.632 43.2 ;
    END
  END esi_hi[242]
  PIN esi_hi[243]
    DIRECTION INPUT ;
    USE SIGNAL ;
    PORT
      LAYER M5 ;
        RECT  46.704 43.116 46.728 43.2 ;
    END
  END esi_hi[243]
  PIN esi_hi[244]
    DIRECTION INPUT ;
    USE SIGNAL ;
    PORT
      LAYER M5 ;
        RECT  46.8 43.116 46.824 43.2 ;
    END
  END esi_hi[244]
  PIN esi_hi[245]
    DIRECTION INPUT ;
    USE SIGNAL ;
    PORT
      LAYER M5 ;
        RECT  46.896 43.116 46.92 43.2 ;
    END
  END esi_hi[245]
  PIN esi_hi[246]
    DIRECTION INPUT ;
    USE SIGNAL ;
    PORT
      LAYER M5 ;
        RECT  46.992 43.116 47.016 43.2 ;
    END
  END esi_hi[246]
  PIN esi_hi[247]
    DIRECTION INPUT ;
    USE SIGNAL ;
    PORT
      LAYER M5 ;
        RECT  47.088 43.116 47.112 43.2 ;
    END
  END esi_hi[247]
  PIN esi_hi[248]
    DIRECTION INPUT ;
    USE SIGNAL ;
    PORT
      LAYER M5 ;
        RECT  47.184 43.116 47.208 43.2 ;
    END
  END esi_hi[248]
  PIN esi_hi[249]
    DIRECTION INPUT ;
    USE SIGNAL ;
    PORT
      LAYER M5 ;
        RECT  47.28 43.116 47.304 43.2 ;
    END
  END esi_hi[249]
  PIN esi_hi[24]
    DIRECTION INPUT ;
    USE SIGNAL ;
    PORT
      LAYER M5 ;
        RECT  37.2 43.116 37.224 43.2 ;
    END
  END esi_hi[24]
  PIN esi_hi[250]
    DIRECTION INPUT ;
    USE SIGNAL ;
    PORT
      LAYER M5 ;
        RECT  47.376 43.116 47.4 43.2 ;
    END
  END esi_hi[250]
  PIN esi_hi[251]
    DIRECTION INPUT ;
    USE SIGNAL ;
    PORT
      LAYER M5 ;
        RECT  47.472 43.116 47.496 43.2 ;
    END
  END esi_hi[251]
  PIN esi_hi[252]
    DIRECTION INPUT ;
    USE SIGNAL ;
    PORT
      LAYER M5 ;
        RECT  47.568 43.116 47.592 43.2 ;
    END
  END esi_hi[252]
  PIN esi_hi[253]
    DIRECTION INPUT ;
    USE SIGNAL ;
    PORT
      LAYER M5 ;
        RECT  47.664 43.116 47.688 43.2 ;
    END
  END esi_hi[253]
  PIN esi_hi[254]
    DIRECTION INPUT ;
    USE SIGNAL ;
    PORT
      LAYER M5 ;
        RECT  47.76 43.116 47.784 43.2 ;
    END
  END esi_hi[254]
  PIN esi_hi[255]
    DIRECTION INPUT ;
    USE SIGNAL ;
    PORT
      LAYER M5 ;
        RECT  47.856 43.116 47.88 43.2 ;
    END
  END esi_hi[255]
  PIN esi_hi[25]
    DIRECTION INPUT ;
    USE SIGNAL ;
    PORT
      LAYER M5 ;
        RECT  37.296 43.116 37.32 43.2 ;
    END
  END esi_hi[25]
  PIN esi_hi[26]
    DIRECTION INPUT ;
    USE SIGNAL ;
    PORT
      LAYER M5 ;
        RECT  37.392 43.116 37.416 43.2 ;
    END
  END esi_hi[26]
  PIN esi_hi[27]
    DIRECTION INPUT ;
    USE SIGNAL ;
    PORT
      LAYER M5 ;
        RECT  37.488 43.116 37.512 43.2 ;
    END
  END esi_hi[27]
  PIN esi_hi[28]
    DIRECTION INPUT ;
    USE SIGNAL ;
    PORT
      LAYER M5 ;
        RECT  37.584 43.116 37.608 43.2 ;
    END
  END esi_hi[28]
  PIN esi_hi[29]
    DIRECTION INPUT ;
    USE SIGNAL ;
    PORT
      LAYER M5 ;
        RECT  37.68 43.116 37.704 43.2 ;
    END
  END esi_hi[29]
  PIN esi_hi[2]
    DIRECTION INPUT ;
    USE SIGNAL ;
    PORT
      LAYER M5 ;
        RECT  35.088 43.116 35.112 43.2 ;
    END
  END esi_hi[2]
  PIN esi_hi[30]
    DIRECTION INPUT ;
    USE SIGNAL ;
    PORT
      LAYER M5 ;
        RECT  37.776 43.116 37.8 43.2 ;
    END
  END esi_hi[30]
  PIN esi_hi[31]
    DIRECTION INPUT ;
    USE SIGNAL ;
    PORT
      LAYER M5 ;
        RECT  37.872 43.116 37.896 43.2 ;
    END
  END esi_hi[31]
  PIN esi_hi[32]
    DIRECTION INPUT ;
    USE SIGNAL ;
    PORT
      LAYER M5 ;
        RECT  41.04 43.116 41.064 43.2 ;
    END
  END esi_hi[32]
  PIN esi_hi[33]
    DIRECTION INPUT ;
    USE SIGNAL ;
    PORT
      LAYER M5 ;
        RECT  41.136 43.116 41.16 43.2 ;
    END
  END esi_hi[33]
  PIN esi_hi[34]
    DIRECTION INPUT ;
    USE SIGNAL ;
    PORT
      LAYER M5 ;
        RECT  41.232 43.116 41.256 43.2 ;
    END
  END esi_hi[34]
  PIN esi_hi[35]
    DIRECTION INPUT ;
    USE SIGNAL ;
    PORT
      LAYER M5 ;
        RECT  41.328 43.116 41.352 43.2 ;
    END
  END esi_hi[35]
  PIN esi_hi[36]
    DIRECTION INPUT ;
    USE SIGNAL ;
    PORT
      LAYER M5 ;
        RECT  41.424 43.116 41.448 43.2 ;
    END
  END esi_hi[36]
  PIN esi_hi[37]
    DIRECTION INPUT ;
    USE SIGNAL ;
    PORT
      LAYER M5 ;
        RECT  41.52 43.116 41.544 43.2 ;
    END
  END esi_hi[37]
  PIN esi_hi[38]
    DIRECTION INPUT ;
    USE SIGNAL ;
    PORT
      LAYER M5 ;
        RECT  41.616 43.116 41.64 43.2 ;
    END
  END esi_hi[38]
  PIN esi_hi[39]
    DIRECTION INPUT ;
    USE SIGNAL ;
    PORT
      LAYER M5 ;
        RECT  41.712 43.116 41.736 43.2 ;
    END
  END esi_hi[39]
  PIN esi_hi[3]
    DIRECTION INPUT ;
    USE SIGNAL ;
    PORT
      LAYER M5 ;
        RECT  35.184 43.116 35.208 43.2 ;
    END
  END esi_hi[3]
  PIN esi_hi[40]
    DIRECTION INPUT ;
    USE SIGNAL ;
    PORT
      LAYER M5 ;
        RECT  41.808 43.116 41.832 43.2 ;
    END
  END esi_hi[40]
  PIN esi_hi[41]
    DIRECTION INPUT ;
    USE SIGNAL ;
    PORT
      LAYER M5 ;
        RECT  41.904 43.116 41.928 43.2 ;
    END
  END esi_hi[41]
  PIN esi_hi[42]
    DIRECTION INPUT ;
    USE SIGNAL ;
    PORT
      LAYER M5 ;
        RECT  42 43.116 42.024 43.2 ;
    END
  END esi_hi[42]
  PIN esi_hi[43]
    DIRECTION INPUT ;
    USE SIGNAL ;
    PORT
      LAYER M5 ;
        RECT  42.096 43.116 42.12 43.2 ;
    END
  END esi_hi[43]
  PIN esi_hi[44]
    DIRECTION INPUT ;
    USE SIGNAL ;
    PORT
      LAYER M5 ;
        RECT  42.192 43.116 42.216 43.2 ;
    END
  END esi_hi[44]
  PIN esi_hi[45]
    DIRECTION INPUT ;
    USE SIGNAL ;
    PORT
      LAYER M5 ;
        RECT  42.288 43.116 42.312 43.2 ;
    END
  END esi_hi[45]
  PIN esi_hi[46]
    DIRECTION INPUT ;
    USE SIGNAL ;
    PORT
      LAYER M5 ;
        RECT  42.384 43.116 42.408 43.2 ;
    END
  END esi_hi[46]
  PIN esi_hi[47]
    DIRECTION INPUT ;
    USE SIGNAL ;
    PORT
      LAYER M5 ;
        RECT  42.48 43.116 42.504 43.2 ;
    END
  END esi_hi[47]
  PIN esi_hi[48]
    DIRECTION INPUT ;
    USE SIGNAL ;
    PORT
      LAYER M5 ;
        RECT  42.576 43.116 42.6 43.2 ;
    END
  END esi_hi[48]
  PIN esi_hi[49]
    DIRECTION INPUT ;
    USE SIGNAL ;
    PORT
      LAYER M5 ;
        RECT  42.672 43.116 42.696 43.2 ;
    END
  END esi_hi[49]
  PIN esi_hi[4]
    DIRECTION INPUT ;
    USE SIGNAL ;
    PORT
      LAYER M5 ;
        RECT  35.28 43.116 35.304 43.2 ;
    END
  END esi_hi[4]
  PIN esi_hi[50]
    DIRECTION INPUT ;
    USE SIGNAL ;
    PORT
      LAYER M5 ;
        RECT  42.768 43.116 42.792 43.2 ;
    END
  END esi_hi[50]
  PIN esi_hi[51]
    DIRECTION INPUT ;
    USE SIGNAL ;
    PORT
      LAYER M5 ;
        RECT  42.864 43.116 42.888 43.2 ;
    END
  END esi_hi[51]
  PIN esi_hi[52]
    DIRECTION INPUT ;
    USE SIGNAL ;
    PORT
      LAYER M5 ;
        RECT  42.96 43.116 42.984 43.2 ;
    END
  END esi_hi[52]
  PIN esi_hi[53]
    DIRECTION INPUT ;
    USE SIGNAL ;
    PORT
      LAYER M5 ;
        RECT  43.056 43.116 43.08 43.2 ;
    END
  END esi_hi[53]
  PIN esi_hi[54]
    DIRECTION INPUT ;
    USE SIGNAL ;
    PORT
      LAYER M5 ;
        RECT  43.152 43.116 43.176 43.2 ;
    END
  END esi_hi[54]
  PIN esi_hi[55]
    DIRECTION INPUT ;
    USE SIGNAL ;
    PORT
      LAYER M5 ;
        RECT  43.248 43.116 43.272 43.2 ;
    END
  END esi_hi[55]
  PIN esi_hi[56]
    DIRECTION INPUT ;
    USE SIGNAL ;
    PORT
      LAYER M5 ;
        RECT  43.344 43.116 43.368 43.2 ;
    END
  END esi_hi[56]
  PIN esi_hi[57]
    DIRECTION INPUT ;
    USE SIGNAL ;
    PORT
      LAYER M5 ;
        RECT  43.44 43.116 43.464 43.2 ;
    END
  END esi_hi[57]
  PIN esi_hi[58]
    DIRECTION INPUT ;
    USE SIGNAL ;
    PORT
      LAYER M5 ;
        RECT  43.536 43.116 43.56 43.2 ;
    END
  END esi_hi[58]
  PIN esi_hi[59]
    DIRECTION INPUT ;
    USE SIGNAL ;
    PORT
      LAYER M5 ;
        RECT  43.632 43.116 43.656 43.2 ;
    END
  END esi_hi[59]
  PIN esi_hi[5]
    DIRECTION INPUT ;
    USE SIGNAL ;
    PORT
      LAYER M5 ;
        RECT  35.376 43.116 35.4 43.2 ;
    END
  END esi_hi[5]
  PIN esi_hi[60]
    DIRECTION INPUT ;
    USE SIGNAL ;
    PORT
      LAYER M5 ;
        RECT  43.728 43.116 43.752 43.2 ;
    END
  END esi_hi[60]
  PIN esi_hi[61]
    DIRECTION INPUT ;
    USE SIGNAL ;
    PORT
      LAYER M5 ;
        RECT  43.824 43.116 43.848 43.2 ;
    END
  END esi_hi[61]
  PIN esi_hi[62]
    DIRECTION INPUT ;
    USE SIGNAL ;
    PORT
      LAYER M5 ;
        RECT  43.92 43.116 43.944 43.2 ;
    END
  END esi_hi[62]
  PIN esi_hi[63]
    DIRECTION INPUT ;
    USE SIGNAL ;
    PORT
      LAYER M5 ;
        RECT  44.016 43.116 44.04 43.2 ;
    END
  END esi_hi[63]
  PIN esi_hi[64]
    DIRECTION INPUT ;
    USE SIGNAL ;
    PORT
      LAYER M5 ;
        RECT  37.968 43.116 37.992 43.2 ;
    END
  END esi_hi[64]
  PIN esi_hi[65]
    DIRECTION INPUT ;
    USE SIGNAL ;
    PORT
      LAYER M5 ;
        RECT  38.064 43.116 38.088 43.2 ;
    END
  END esi_hi[65]
  PIN esi_hi[66]
    DIRECTION INPUT ;
    USE SIGNAL ;
    PORT
      LAYER M5 ;
        RECT  38.16 43.116 38.184 43.2 ;
    END
  END esi_hi[66]
  PIN esi_hi[67]
    DIRECTION INPUT ;
    USE SIGNAL ;
    PORT
      LAYER M5 ;
        RECT  38.256 43.116 38.28 43.2 ;
    END
  END esi_hi[67]
  PIN esi_hi[68]
    DIRECTION INPUT ;
    USE SIGNAL ;
    PORT
      LAYER M5 ;
        RECT  38.352 43.116 38.376 43.2 ;
    END
  END esi_hi[68]
  PIN esi_hi[69]
    DIRECTION INPUT ;
    USE SIGNAL ;
    PORT
      LAYER M5 ;
        RECT  38.448 43.116 38.472 43.2 ;
    END
  END esi_hi[69]
  PIN esi_hi[6]
    DIRECTION INPUT ;
    USE SIGNAL ;
    PORT
      LAYER M5 ;
        RECT  35.472 43.116 35.496 43.2 ;
    END
  END esi_hi[6]
  PIN esi_hi[70]
    DIRECTION INPUT ;
    USE SIGNAL ;
    PORT
      LAYER M5 ;
        RECT  38.544 43.116 38.568 43.2 ;
    END
  END esi_hi[70]
  PIN esi_hi[71]
    DIRECTION INPUT ;
    USE SIGNAL ;
    PORT
      LAYER M5 ;
        RECT  38.64 43.116 38.664 43.2 ;
    END
  END esi_hi[71]
  PIN esi_hi[72]
    DIRECTION INPUT ;
    USE SIGNAL ;
    PORT
      LAYER M5 ;
        RECT  38.736 43.116 38.76 43.2 ;
    END
  END esi_hi[72]
  PIN esi_hi[73]
    DIRECTION INPUT ;
    USE SIGNAL ;
    PORT
      LAYER M5 ;
        RECT  38.832 43.116 38.856 43.2 ;
    END
  END esi_hi[73]
  PIN esi_hi[74]
    DIRECTION INPUT ;
    USE SIGNAL ;
    PORT
      LAYER M5 ;
        RECT  38.928 43.116 38.952 43.2 ;
    END
  END esi_hi[74]
  PIN esi_hi[75]
    DIRECTION INPUT ;
    USE SIGNAL ;
    PORT
      LAYER M5 ;
        RECT  39.024 43.116 39.048 43.2 ;
    END
  END esi_hi[75]
  PIN esi_hi[76]
    DIRECTION INPUT ;
    USE SIGNAL ;
    PORT
      LAYER M5 ;
        RECT  39.12 43.116 39.144 43.2 ;
    END
  END esi_hi[76]
  PIN esi_hi[77]
    DIRECTION INPUT ;
    USE SIGNAL ;
    PORT
      LAYER M5 ;
        RECT  39.216 43.116 39.24 43.2 ;
    END
  END esi_hi[77]
  PIN esi_hi[78]
    DIRECTION INPUT ;
    USE SIGNAL ;
    PORT
      LAYER M5 ;
        RECT  39.312 43.116 39.336 43.2 ;
    END
  END esi_hi[78]
  PIN esi_hi[79]
    DIRECTION INPUT ;
    USE SIGNAL ;
    PORT
      LAYER M5 ;
        RECT  39.408 43.116 39.432 43.2 ;
    END
  END esi_hi[79]
  PIN esi_hi[7]
    DIRECTION INPUT ;
    USE SIGNAL ;
    PORT
      LAYER M5 ;
        RECT  35.568 43.116 35.592 43.2 ;
    END
  END esi_hi[7]
  PIN esi_hi[80]
    DIRECTION INPUT ;
    USE SIGNAL ;
    PORT
      LAYER M5 ;
        RECT  39.504 43.116 39.528 43.2 ;
    END
  END esi_hi[80]
  PIN esi_hi[81]
    DIRECTION INPUT ;
    USE SIGNAL ;
    PORT
      LAYER M5 ;
        RECT  39.6 43.116 39.624 43.2 ;
    END
  END esi_hi[81]
  PIN esi_hi[82]
    DIRECTION INPUT ;
    USE SIGNAL ;
    PORT
      LAYER M5 ;
        RECT  39.696 43.116 39.72 43.2 ;
    END
  END esi_hi[82]
  PIN esi_hi[83]
    DIRECTION INPUT ;
    USE SIGNAL ;
    PORT
      LAYER M5 ;
        RECT  39.792 43.116 39.816 43.2 ;
    END
  END esi_hi[83]
  PIN esi_hi[84]
    DIRECTION INPUT ;
    USE SIGNAL ;
    PORT
      LAYER M5 ;
        RECT  39.888 43.116 39.912 43.2 ;
    END
  END esi_hi[84]
  PIN esi_hi[85]
    DIRECTION INPUT ;
    USE SIGNAL ;
    PORT
      LAYER M5 ;
        RECT  39.984 43.116 40.008 43.2 ;
    END
  END esi_hi[85]
  PIN esi_hi[86]
    DIRECTION INPUT ;
    USE SIGNAL ;
    PORT
      LAYER M5 ;
        RECT  40.08 43.116 40.104 43.2 ;
    END
  END esi_hi[86]
  PIN esi_hi[87]
    DIRECTION INPUT ;
    USE SIGNAL ;
    PORT
      LAYER M5 ;
        RECT  40.176 43.116 40.2 43.2 ;
    END
  END esi_hi[87]
  PIN esi_hi[88]
    DIRECTION INPUT ;
    USE SIGNAL ;
    PORT
      LAYER M5 ;
        RECT  40.272 43.116 40.296 43.2 ;
    END
  END esi_hi[88]
  PIN esi_hi[89]
    DIRECTION INPUT ;
    USE SIGNAL ;
    PORT
      LAYER M5 ;
        RECT  40.368 43.116 40.392 43.2 ;
    END
  END esi_hi[89]
  PIN esi_hi[8]
    DIRECTION INPUT ;
    USE SIGNAL ;
    PORT
      LAYER M5 ;
        RECT  35.664 43.116 35.688 43.2 ;
    END
  END esi_hi[8]
  PIN esi_hi[90]
    DIRECTION INPUT ;
    USE SIGNAL ;
    PORT
      LAYER M5 ;
        RECT  40.464 43.116 40.488 43.2 ;
    END
  END esi_hi[90]
  PIN esi_hi[91]
    DIRECTION INPUT ;
    USE SIGNAL ;
    PORT
      LAYER M5 ;
        RECT  40.56 43.116 40.584 43.2 ;
    END
  END esi_hi[91]
  PIN esi_hi[92]
    DIRECTION INPUT ;
    USE SIGNAL ;
    PORT
      LAYER M5 ;
        RECT  40.656 43.116 40.68 43.2 ;
    END
  END esi_hi[92]
  PIN esi_hi[93]
    DIRECTION INPUT ;
    USE SIGNAL ;
    PORT
      LAYER M5 ;
        RECT  40.752 43.116 40.776 43.2 ;
    END
  END esi_hi[93]
  PIN esi_hi[94]
    DIRECTION INPUT ;
    USE SIGNAL ;
    PORT
      LAYER M5 ;
        RECT  40.848 43.116 40.872 43.2 ;
    END
  END esi_hi[94]
  PIN esi_hi[95]
    DIRECTION INPUT ;
    USE SIGNAL ;
    PORT
      LAYER M5 ;
        RECT  40.944 43.116 40.968 43.2 ;
    END
  END esi_hi[95]
  PIN esi_hi[96]
    DIRECTION INPUT ;
    USE SIGNAL ;
    PORT
      LAYER M5 ;
        RECT  28.752 43.116 28.776 43.2 ;
    END
  END esi_hi[96]
  PIN esi_hi[97]
    DIRECTION INPUT ;
    USE SIGNAL ;
    PORT
      LAYER M5 ;
        RECT  28.848 43.116 28.872 43.2 ;
    END
  END esi_hi[97]
  PIN esi_hi[98]
    DIRECTION INPUT ;
    USE SIGNAL ;
    PORT
      LAYER M5 ;
        RECT  28.944 43.116 28.968 43.2 ;
    END
  END esi_hi[98]
  PIN esi_hi[99]
    DIRECTION INPUT ;
    USE SIGNAL ;
    PORT
      LAYER M5 ;
        RECT  29.04 43.116 29.064 43.2 ;
    END
  END esi_hi[99]
  PIN esi_hi[9]
    DIRECTION INPUT ;
    USE SIGNAL ;
    PORT
      LAYER M5 ;
        RECT  35.76 43.116 35.784 43.2 ;
    END
  END esi_hi[9]
  PIN esi_lo[0]
    DIRECTION INPUT ;
    USE SIGNAL ;
    PORT
      LAYER M5 ;
        RECT  41.424 0 41.448 0.084 ;
    END
  END esi_lo[0]
  PIN esi_lo[100]
    DIRECTION INPUT ;
    USE SIGNAL ;
    PORT
      LAYER M5 ;
        RECT  44.88 0 44.904 0.084 ;
    END
  END esi_lo[100]
  PIN esi_lo[101]
    DIRECTION INPUT ;
    USE SIGNAL ;
    PORT
      LAYER M5 ;
        RECT  44.976 0 45 0.084 ;
    END
  END esi_lo[101]
  PIN esi_lo[102]
    DIRECTION INPUT ;
    USE SIGNAL ;
    PORT
      LAYER M5 ;
        RECT  45.072 0 45.096 0.084 ;
    END
  END esi_lo[102]
  PIN esi_lo[103]
    DIRECTION INPUT ;
    USE SIGNAL ;
    PORT
      LAYER M5 ;
        RECT  45.168 0 45.192 0.084 ;
    END
  END esi_lo[103]
  PIN esi_lo[104]
    DIRECTION INPUT ;
    USE SIGNAL ;
    PORT
      LAYER M5 ;
        RECT  45.264 0 45.288 0.084 ;
    END
  END esi_lo[104]
  PIN esi_lo[105]
    DIRECTION INPUT ;
    USE SIGNAL ;
    PORT
      LAYER M5 ;
        RECT  45.36 0 45.384 0.084 ;
    END
  END esi_lo[105]
  PIN esi_lo[106]
    DIRECTION INPUT ;
    USE SIGNAL ;
    PORT
      LAYER M5 ;
        RECT  45.456 0 45.48 0.084 ;
    END
  END esi_lo[106]
  PIN esi_lo[107]
    DIRECTION INPUT ;
    USE SIGNAL ;
    PORT
      LAYER M5 ;
        RECT  45.552 0 45.576 0.084 ;
    END
  END esi_lo[107]
  PIN esi_lo[108]
    DIRECTION INPUT ;
    USE SIGNAL ;
    PORT
      LAYER M5 ;
        RECT  45.648 0 45.672 0.084 ;
    END
  END esi_lo[108]
  PIN esi_lo[109]
    DIRECTION INPUT ;
    USE SIGNAL ;
    PORT
      LAYER M5 ;
        RECT  45.744 0 45.768 0.084 ;
    END
  END esi_lo[109]
  PIN esi_lo[10]
    DIRECTION INPUT ;
    USE SIGNAL ;
    PORT
      LAYER M5 ;
        RECT  42.384 0 42.408 0.084 ;
    END
  END esi_lo[10]
  PIN esi_lo[110]
    DIRECTION INPUT ;
    USE SIGNAL ;
    PORT
      LAYER M5 ;
        RECT  45.84 0 45.864 0.084 ;
    END
  END esi_lo[110]
  PIN esi_lo[111]
    DIRECTION INPUT ;
    USE SIGNAL ;
    PORT
      LAYER M5 ;
        RECT  45.936 0 45.96 0.084 ;
    END
  END esi_lo[111]
  PIN esi_lo[112]
    DIRECTION INPUT ;
    USE SIGNAL ;
    PORT
      LAYER M5 ;
        RECT  46.032 0 46.056 0.084 ;
    END
  END esi_lo[112]
  PIN esi_lo[113]
    DIRECTION INPUT ;
    USE SIGNAL ;
    PORT
      LAYER M5 ;
        RECT  46.128 0 46.152 0.084 ;
    END
  END esi_lo[113]
  PIN esi_lo[114]
    DIRECTION INPUT ;
    USE SIGNAL ;
    PORT
      LAYER M5 ;
        RECT  46.224 0 46.248 0.084 ;
    END
  END esi_lo[114]
  PIN esi_lo[115]
    DIRECTION INPUT ;
    USE SIGNAL ;
    PORT
      LAYER M5 ;
        RECT  46.32 0 46.344 0.084 ;
    END
  END esi_lo[115]
  PIN esi_lo[116]
    DIRECTION INPUT ;
    USE SIGNAL ;
    PORT
      LAYER M5 ;
        RECT  46.416 0 46.44 0.084 ;
    END
  END esi_lo[116]
  PIN esi_lo[117]
    DIRECTION INPUT ;
    USE SIGNAL ;
    PORT
      LAYER M5 ;
        RECT  46.512 0 46.536 0.084 ;
    END
  END esi_lo[117]
  PIN esi_lo[118]
    DIRECTION INPUT ;
    USE SIGNAL ;
    PORT
      LAYER M5 ;
        RECT  46.608 0 46.632 0.084 ;
    END
  END esi_lo[118]
  PIN esi_lo[119]
    DIRECTION INPUT ;
    USE SIGNAL ;
    PORT
      LAYER M5 ;
        RECT  46.704 0 46.728 0.084 ;
    END
  END esi_lo[119]
  PIN esi_lo[11]
    DIRECTION INPUT ;
    USE SIGNAL ;
    PORT
      LAYER M5 ;
        RECT  42.48 0 42.504 0.084 ;
    END
  END esi_lo[11]
  PIN esi_lo[120]
    DIRECTION INPUT ;
    USE SIGNAL ;
    PORT
      LAYER M5 ;
        RECT  46.8 0 46.824 0.084 ;
    END
  END esi_lo[120]
  PIN esi_lo[121]
    DIRECTION INPUT ;
    USE SIGNAL ;
    PORT
      LAYER M5 ;
        RECT  46.896 0 46.92 0.084 ;
    END
  END esi_lo[121]
  PIN esi_lo[122]
    DIRECTION INPUT ;
    USE SIGNAL ;
    PORT
      LAYER M5 ;
        RECT  46.992 0 47.016 0.084 ;
    END
  END esi_lo[122]
  PIN esi_lo[123]
    DIRECTION INPUT ;
    USE SIGNAL ;
    PORT
      LAYER M5 ;
        RECT  47.088 0 47.112 0.084 ;
    END
  END esi_lo[123]
  PIN esi_lo[124]
    DIRECTION INPUT ;
    USE SIGNAL ;
    PORT
      LAYER M5 ;
        RECT  47.184 0 47.208 0.084 ;
    END
  END esi_lo[124]
  PIN esi_lo[125]
    DIRECTION INPUT ;
    USE SIGNAL ;
    PORT
      LAYER M5 ;
        RECT  47.28 0 47.304 0.084 ;
    END
  END esi_lo[125]
  PIN esi_lo[126]
    DIRECTION INPUT ;
    USE SIGNAL ;
    PORT
      LAYER M5 ;
        RECT  47.376 0 47.4 0.084 ;
    END
  END esi_lo[126]
  PIN esi_lo[127]
    DIRECTION INPUT ;
    USE SIGNAL ;
    PORT
      LAYER M5 ;
        RECT  47.472 0 47.496 0.084 ;
    END
  END esi_lo[127]
  PIN esi_lo[128]
    DIRECTION INPUT ;
    USE SIGNAL ;
    PORT
      LAYER M5 ;
        RECT  35.28 0 35.304 0.084 ;
    END
  END esi_lo[128]
  PIN esi_lo[129]
    DIRECTION INPUT ;
    USE SIGNAL ;
    PORT
      LAYER M5 ;
        RECT  35.376 0 35.4 0.084 ;
    END
  END esi_lo[129]
  PIN esi_lo[12]
    DIRECTION INPUT ;
    USE SIGNAL ;
    PORT
      LAYER M5 ;
        RECT  42.576 0 42.6 0.084 ;
    END
  END esi_lo[12]
  PIN esi_lo[130]
    DIRECTION INPUT ;
    USE SIGNAL ;
    PORT
      LAYER M5 ;
        RECT  35.472 0 35.496 0.084 ;
    END
  END esi_lo[130]
  PIN esi_lo[131]
    DIRECTION INPUT ;
    USE SIGNAL ;
    PORT
      LAYER M5 ;
        RECT  35.568 0 35.592 0.084 ;
    END
  END esi_lo[131]
  PIN esi_lo[132]
    DIRECTION INPUT ;
    USE SIGNAL ;
    PORT
      LAYER M5 ;
        RECT  35.664 0 35.688 0.084 ;
    END
  END esi_lo[132]
  PIN esi_lo[133]
    DIRECTION INPUT ;
    USE SIGNAL ;
    PORT
      LAYER M5 ;
        RECT  35.76 0 35.784 0.084 ;
    END
  END esi_lo[133]
  PIN esi_lo[134]
    DIRECTION INPUT ;
    USE SIGNAL ;
    PORT
      LAYER M5 ;
        RECT  35.856 0 35.88 0.084 ;
    END
  END esi_lo[134]
  PIN esi_lo[135]
    DIRECTION INPUT ;
    USE SIGNAL ;
    PORT
      LAYER M5 ;
        RECT  35.952 0 35.976 0.084 ;
    END
  END esi_lo[135]
  PIN esi_lo[136]
    DIRECTION INPUT ;
    USE SIGNAL ;
    PORT
      LAYER M5 ;
        RECT  36.048 0 36.072 0.084 ;
    END
  END esi_lo[136]
  PIN esi_lo[137]
    DIRECTION INPUT ;
    USE SIGNAL ;
    PORT
      LAYER M5 ;
        RECT  36.144 0 36.168 0.084 ;
    END
  END esi_lo[137]
  PIN esi_lo[138]
    DIRECTION INPUT ;
    USE SIGNAL ;
    PORT
      LAYER M5 ;
        RECT  36.24 0 36.264 0.084 ;
    END
  END esi_lo[138]
  PIN esi_lo[139]
    DIRECTION INPUT ;
    USE SIGNAL ;
    PORT
      LAYER M5 ;
        RECT  36.336 0 36.36 0.084 ;
    END
  END esi_lo[139]
  PIN esi_lo[13]
    DIRECTION INPUT ;
    USE SIGNAL ;
    PORT
      LAYER M5 ;
        RECT  42.672 0 42.696 0.084 ;
    END
  END esi_lo[13]
  PIN esi_lo[140]
    DIRECTION INPUT ;
    USE SIGNAL ;
    PORT
      LAYER M5 ;
        RECT  36.432 0 36.456 0.084 ;
    END
  END esi_lo[140]
  PIN esi_lo[141]
    DIRECTION INPUT ;
    USE SIGNAL ;
    PORT
      LAYER M5 ;
        RECT  36.528 0 36.552 0.084 ;
    END
  END esi_lo[141]
  PIN esi_lo[142]
    DIRECTION INPUT ;
    USE SIGNAL ;
    PORT
      LAYER M5 ;
        RECT  36.624 0 36.648 0.084 ;
    END
  END esi_lo[142]
  PIN esi_lo[143]
    DIRECTION INPUT ;
    USE SIGNAL ;
    PORT
      LAYER M5 ;
        RECT  36.72 0 36.744 0.084 ;
    END
  END esi_lo[143]
  PIN esi_lo[144]
    DIRECTION INPUT ;
    USE SIGNAL ;
    PORT
      LAYER M5 ;
        RECT  36.816 0 36.84 0.084 ;
    END
  END esi_lo[144]
  PIN esi_lo[145]
    DIRECTION INPUT ;
    USE SIGNAL ;
    PORT
      LAYER M5 ;
        RECT  36.912 0 36.936 0.084 ;
    END
  END esi_lo[145]
  PIN esi_lo[146]
    DIRECTION INPUT ;
    USE SIGNAL ;
    PORT
      LAYER M5 ;
        RECT  37.008 0 37.032 0.084 ;
    END
  END esi_lo[146]
  PIN esi_lo[147]
    DIRECTION INPUT ;
    USE SIGNAL ;
    PORT
      LAYER M5 ;
        RECT  37.104 0 37.128 0.084 ;
    END
  END esi_lo[147]
  PIN esi_lo[148]
    DIRECTION INPUT ;
    USE SIGNAL ;
    PORT
      LAYER M5 ;
        RECT  37.2 0 37.224 0.084 ;
    END
  END esi_lo[148]
  PIN esi_lo[149]
    DIRECTION INPUT ;
    USE SIGNAL ;
    PORT
      LAYER M5 ;
        RECT  37.296 0 37.32 0.084 ;
    END
  END esi_lo[149]
  PIN esi_lo[14]
    DIRECTION INPUT ;
    USE SIGNAL ;
    PORT
      LAYER M5 ;
        RECT  42.768 0 42.792 0.084 ;
    END
  END esi_lo[14]
  PIN esi_lo[150]
    DIRECTION INPUT ;
    USE SIGNAL ;
    PORT
      LAYER M5 ;
        RECT  37.392 0 37.416 0.084 ;
    END
  END esi_lo[150]
  PIN esi_lo[151]
    DIRECTION INPUT ;
    USE SIGNAL ;
    PORT
      LAYER M5 ;
        RECT  37.488 0 37.512 0.084 ;
    END
  END esi_lo[151]
  PIN esi_lo[152]
    DIRECTION INPUT ;
    USE SIGNAL ;
    PORT
      LAYER M5 ;
        RECT  37.584 0 37.608 0.084 ;
    END
  END esi_lo[152]
  PIN esi_lo[153]
    DIRECTION INPUT ;
    USE SIGNAL ;
    PORT
      LAYER M5 ;
        RECT  37.68 0 37.704 0.084 ;
    END
  END esi_lo[153]
  PIN esi_lo[154]
    DIRECTION INPUT ;
    USE SIGNAL ;
    PORT
      LAYER M5 ;
        RECT  37.776 0 37.8 0.084 ;
    END
  END esi_lo[154]
  PIN esi_lo[155]
    DIRECTION INPUT ;
    USE SIGNAL ;
    PORT
      LAYER M5 ;
        RECT  37.872 0 37.896 0.084 ;
    END
  END esi_lo[155]
  PIN esi_lo[156]
    DIRECTION INPUT ;
    USE SIGNAL ;
    PORT
      LAYER M5 ;
        RECT  37.968 0 37.992 0.084 ;
    END
  END esi_lo[156]
  PIN esi_lo[157]
    DIRECTION INPUT ;
    USE SIGNAL ;
    PORT
      LAYER M5 ;
        RECT  38.064 0 38.088 0.084 ;
    END
  END esi_lo[157]
  PIN esi_lo[158]
    DIRECTION INPUT ;
    USE SIGNAL ;
    PORT
      LAYER M5 ;
        RECT  38.16 0 38.184 0.084 ;
    END
  END esi_lo[158]
  PIN esi_lo[159]
    DIRECTION INPUT ;
    USE SIGNAL ;
    PORT
      LAYER M5 ;
        RECT  38.256 0 38.28 0.084 ;
    END
  END esi_lo[159]
  PIN esi_lo[15]
    DIRECTION INPUT ;
    USE SIGNAL ;
    PORT
      LAYER M5 ;
        RECT  42.864 0 42.888 0.084 ;
    END
  END esi_lo[15]
  PIN esi_lo[160]
    DIRECTION INPUT ;
    USE SIGNAL ;
    PORT
      LAYER M5 ;
        RECT  32.208 0 32.232 0.084 ;
    END
  END esi_lo[160]
  PIN esi_lo[161]
    DIRECTION INPUT ;
    USE SIGNAL ;
    PORT
      LAYER M5 ;
        RECT  32.304 0 32.328 0.084 ;
    END
  END esi_lo[161]
  PIN esi_lo[162]
    DIRECTION INPUT ;
    USE SIGNAL ;
    PORT
      LAYER M5 ;
        RECT  32.4 0 32.424 0.084 ;
    END
  END esi_lo[162]
  PIN esi_lo[163]
    DIRECTION INPUT ;
    USE SIGNAL ;
    PORT
      LAYER M5 ;
        RECT  32.496 0 32.52 0.084 ;
    END
  END esi_lo[163]
  PIN esi_lo[164]
    DIRECTION INPUT ;
    USE SIGNAL ;
    PORT
      LAYER M5 ;
        RECT  32.592 0 32.616 0.084 ;
    END
  END esi_lo[164]
  PIN esi_lo[165]
    DIRECTION INPUT ;
    USE SIGNAL ;
    PORT
      LAYER M5 ;
        RECT  32.688 0 32.712 0.084 ;
    END
  END esi_lo[165]
  PIN esi_lo[166]
    DIRECTION INPUT ;
    USE SIGNAL ;
    PORT
      LAYER M5 ;
        RECT  32.784 0 32.808 0.084 ;
    END
  END esi_lo[166]
  PIN esi_lo[167]
    DIRECTION INPUT ;
    USE SIGNAL ;
    PORT
      LAYER M5 ;
        RECT  32.88 0 32.904 0.084 ;
    END
  END esi_lo[167]
  PIN esi_lo[168]
    DIRECTION INPUT ;
    USE SIGNAL ;
    PORT
      LAYER M5 ;
        RECT  32.976 0 33 0.084 ;
    END
  END esi_lo[168]
  PIN esi_lo[169]
    DIRECTION INPUT ;
    USE SIGNAL ;
    PORT
      LAYER M5 ;
        RECT  33.072 0 33.096 0.084 ;
    END
  END esi_lo[169]
  PIN esi_lo[16]
    DIRECTION INPUT ;
    USE SIGNAL ;
    PORT
      LAYER M5 ;
        RECT  42.96 0 42.984 0.084 ;
    END
  END esi_lo[16]
  PIN esi_lo[170]
    DIRECTION INPUT ;
    USE SIGNAL ;
    PORT
      LAYER M5 ;
        RECT  33.168 0 33.192 0.084 ;
    END
  END esi_lo[170]
  PIN esi_lo[171]
    DIRECTION INPUT ;
    USE SIGNAL ;
    PORT
      LAYER M5 ;
        RECT  33.264 0 33.288 0.084 ;
    END
  END esi_lo[171]
  PIN esi_lo[172]
    DIRECTION INPUT ;
    USE SIGNAL ;
    PORT
      LAYER M5 ;
        RECT  33.36 0 33.384 0.084 ;
    END
  END esi_lo[172]
  PIN esi_lo[173]
    DIRECTION INPUT ;
    USE SIGNAL ;
    PORT
      LAYER M5 ;
        RECT  33.456 0 33.48 0.084 ;
    END
  END esi_lo[173]
  PIN esi_lo[174]
    DIRECTION INPUT ;
    USE SIGNAL ;
    PORT
      LAYER M5 ;
        RECT  33.552 0 33.576 0.084 ;
    END
  END esi_lo[174]
  PIN esi_lo[175]
    DIRECTION INPUT ;
    USE SIGNAL ;
    PORT
      LAYER M5 ;
        RECT  33.648 0 33.672 0.084 ;
    END
  END esi_lo[175]
  PIN esi_lo[176]
    DIRECTION INPUT ;
    USE SIGNAL ;
    PORT
      LAYER M5 ;
        RECT  33.744 0 33.768 0.084 ;
    END
  END esi_lo[176]
  PIN esi_lo[177]
    DIRECTION INPUT ;
    USE SIGNAL ;
    PORT
      LAYER M5 ;
        RECT  33.84 0 33.864 0.084 ;
    END
  END esi_lo[177]
  PIN esi_lo[178]
    DIRECTION INPUT ;
    USE SIGNAL ;
    PORT
      LAYER M5 ;
        RECT  33.936 0 33.96 0.084 ;
    END
  END esi_lo[178]
  PIN esi_lo[179]
    DIRECTION INPUT ;
    USE SIGNAL ;
    PORT
      LAYER M5 ;
        RECT  34.032 0 34.056 0.084 ;
    END
  END esi_lo[179]
  PIN esi_lo[17]
    DIRECTION INPUT ;
    USE SIGNAL ;
    PORT
      LAYER M5 ;
        RECT  43.056 0 43.08 0.084 ;
    END
  END esi_lo[17]
  PIN esi_lo[180]
    DIRECTION INPUT ;
    USE SIGNAL ;
    PORT
      LAYER M5 ;
        RECT  34.128 0 34.152 0.084 ;
    END
  END esi_lo[180]
  PIN esi_lo[181]
    DIRECTION INPUT ;
    USE SIGNAL ;
    PORT
      LAYER M5 ;
        RECT  34.224 0 34.248 0.084 ;
    END
  END esi_lo[181]
  PIN esi_lo[182]
    DIRECTION INPUT ;
    USE SIGNAL ;
    PORT
      LAYER M5 ;
        RECT  34.32 0 34.344 0.084 ;
    END
  END esi_lo[182]
  PIN esi_lo[183]
    DIRECTION INPUT ;
    USE SIGNAL ;
    PORT
      LAYER M5 ;
        RECT  34.416 0 34.44 0.084 ;
    END
  END esi_lo[183]
  PIN esi_lo[184]
    DIRECTION INPUT ;
    USE SIGNAL ;
    PORT
      LAYER M5 ;
        RECT  34.512 0 34.536 0.084 ;
    END
  END esi_lo[184]
  PIN esi_lo[185]
    DIRECTION INPUT ;
    USE SIGNAL ;
    PORT
      LAYER M5 ;
        RECT  34.608 0 34.632 0.084 ;
    END
  END esi_lo[185]
  PIN esi_lo[186]
    DIRECTION INPUT ;
    USE SIGNAL ;
    PORT
      LAYER M5 ;
        RECT  34.704 0 34.728 0.084 ;
    END
  END esi_lo[186]
  PIN esi_lo[187]
    DIRECTION INPUT ;
    USE SIGNAL ;
    PORT
      LAYER M5 ;
        RECT  34.8 0 34.824 0.084 ;
    END
  END esi_lo[187]
  PIN esi_lo[188]
    DIRECTION INPUT ;
    USE SIGNAL ;
    PORT
      LAYER M5 ;
        RECT  34.896 0 34.92 0.084 ;
    END
  END esi_lo[188]
  PIN esi_lo[189]
    DIRECTION INPUT ;
    USE SIGNAL ;
    PORT
      LAYER M5 ;
        RECT  34.992 0 35.016 0.084 ;
    END
  END esi_lo[189]
  PIN esi_lo[18]
    DIRECTION INPUT ;
    USE SIGNAL ;
    PORT
      LAYER M5 ;
        RECT  43.152 0 43.176 0.084 ;
    END
  END esi_lo[18]
  PIN esi_lo[190]
    DIRECTION INPUT ;
    USE SIGNAL ;
    PORT
      LAYER M5 ;
        RECT  35.088 0 35.112 0.084 ;
    END
  END esi_lo[190]
  PIN esi_lo[191]
    DIRECTION INPUT ;
    USE SIGNAL ;
    PORT
      LAYER M5 ;
        RECT  35.184 0 35.208 0.084 ;
    END
  END esi_lo[191]
  PIN esi_lo[192]
    DIRECTION INPUT ;
    USE SIGNAL ;
    PORT
      LAYER M5 ;
        RECT  54.48 0 54.504 0.084 ;
    END
  END esi_lo[192]
  PIN esi_lo[193]
    DIRECTION INPUT ;
    USE SIGNAL ;
    PORT
      LAYER M5 ;
        RECT  54.576 0 54.6 0.084 ;
    END
  END esi_lo[193]
  PIN esi_lo[194]
    DIRECTION INPUT ;
    USE SIGNAL ;
    PORT
      LAYER M5 ;
        RECT  54.672 0 54.696 0.084 ;
    END
  END esi_lo[194]
  PIN esi_lo[195]
    DIRECTION INPUT ;
    USE SIGNAL ;
    PORT
      LAYER M5 ;
        RECT  54.768 0 54.792 0.084 ;
    END
  END esi_lo[195]
  PIN esi_lo[196]
    DIRECTION INPUT ;
    USE SIGNAL ;
    PORT
      LAYER M5 ;
        RECT  54.864 0 54.888 0.084 ;
    END
  END esi_lo[196]
  PIN esi_lo[197]
    DIRECTION INPUT ;
    USE SIGNAL ;
    PORT
      LAYER M5 ;
        RECT  54.96 0 54.984 0.084 ;
    END
  END esi_lo[197]
  PIN esi_lo[198]
    DIRECTION INPUT ;
    USE SIGNAL ;
    PORT
      LAYER M5 ;
        RECT  55.056 0 55.08 0.084 ;
    END
  END esi_lo[198]
  PIN esi_lo[199]
    DIRECTION INPUT ;
    USE SIGNAL ;
    PORT
      LAYER M5 ;
        RECT  55.152 0 55.176 0.084 ;
    END
  END esi_lo[199]
  PIN esi_lo[19]
    DIRECTION INPUT ;
    USE SIGNAL ;
    PORT
      LAYER M5 ;
        RECT  43.248 0 43.272 0.084 ;
    END
  END esi_lo[19]
  PIN esi_lo[1]
    DIRECTION INPUT ;
    USE SIGNAL ;
    PORT
      LAYER M5 ;
        RECT  41.52 0 41.544 0.084 ;
    END
  END esi_lo[1]
  PIN esi_lo[200]
    DIRECTION INPUT ;
    USE SIGNAL ;
    PORT
      LAYER M5 ;
        RECT  55.248 0 55.272 0.084 ;
    END
  END esi_lo[200]
  PIN esi_lo[201]
    DIRECTION INPUT ;
    USE SIGNAL ;
    PORT
      LAYER M5 ;
        RECT  55.344 0 55.368 0.084 ;
    END
  END esi_lo[201]
  PIN esi_lo[202]
    DIRECTION INPUT ;
    USE SIGNAL ;
    PORT
      LAYER M5 ;
        RECT  55.44 0 55.464 0.084 ;
    END
  END esi_lo[202]
  PIN esi_lo[203]
    DIRECTION INPUT ;
    USE SIGNAL ;
    PORT
      LAYER M5 ;
        RECT  55.536 0 55.56 0.084 ;
    END
  END esi_lo[203]
  PIN esi_lo[204]
    DIRECTION INPUT ;
    USE SIGNAL ;
    PORT
      LAYER M5 ;
        RECT  55.632 0 55.656 0.084 ;
    END
  END esi_lo[204]
  PIN esi_lo[205]
    DIRECTION INPUT ;
    USE SIGNAL ;
    PORT
      LAYER M5 ;
        RECT  55.728 0 55.752 0.084 ;
    END
  END esi_lo[205]
  PIN esi_lo[206]
    DIRECTION INPUT ;
    USE SIGNAL ;
    PORT
      LAYER M5 ;
        RECT  55.824 0 55.848 0.084 ;
    END
  END esi_lo[206]
  PIN esi_lo[207]
    DIRECTION INPUT ;
    USE SIGNAL ;
    PORT
      LAYER M5 ;
        RECT  55.92 0 55.944 0.084 ;
    END
  END esi_lo[207]
  PIN esi_lo[208]
    DIRECTION INPUT ;
    USE SIGNAL ;
    PORT
      LAYER M5 ;
        RECT  56.016 0 56.04 0.084 ;
    END
  END esi_lo[208]
  PIN esi_lo[209]
    DIRECTION INPUT ;
    USE SIGNAL ;
    PORT
      LAYER M5 ;
        RECT  56.112 0 56.136 0.084 ;
    END
  END esi_lo[209]
  PIN esi_lo[20]
    DIRECTION INPUT ;
    USE SIGNAL ;
    PORT
      LAYER M5 ;
        RECT  43.344 0 43.368 0.084 ;
    END
  END esi_lo[20]
  PIN esi_lo[210]
    DIRECTION INPUT ;
    USE SIGNAL ;
    PORT
      LAYER M5 ;
        RECT  56.208 0 56.232 0.084 ;
    END
  END esi_lo[210]
  PIN esi_lo[211]
    DIRECTION INPUT ;
    USE SIGNAL ;
    PORT
      LAYER M5 ;
        RECT  56.304 0 56.328 0.084 ;
    END
  END esi_lo[211]
  PIN esi_lo[212]
    DIRECTION INPUT ;
    USE SIGNAL ;
    PORT
      LAYER M5 ;
        RECT  56.4 0 56.424 0.084 ;
    END
  END esi_lo[212]
  PIN esi_lo[213]
    DIRECTION INPUT ;
    USE SIGNAL ;
    PORT
      LAYER M5 ;
        RECT  56.496 0 56.52 0.084 ;
    END
  END esi_lo[213]
  PIN esi_lo[214]
    DIRECTION INPUT ;
    USE SIGNAL ;
    PORT
      LAYER M5 ;
        RECT  56.592 0 56.616 0.084 ;
    END
  END esi_lo[214]
  PIN esi_lo[215]
    DIRECTION INPUT ;
    USE SIGNAL ;
    PORT
      LAYER M5 ;
        RECT  56.688 0 56.712 0.084 ;
    END
  END esi_lo[215]
  PIN esi_lo[216]
    DIRECTION INPUT ;
    USE SIGNAL ;
    PORT
      LAYER M5 ;
        RECT  56.784 0 56.808 0.084 ;
    END
  END esi_lo[216]
  PIN esi_lo[217]
    DIRECTION INPUT ;
    USE SIGNAL ;
    PORT
      LAYER M5 ;
        RECT  56.88 0 56.904 0.084 ;
    END
  END esi_lo[217]
  PIN esi_lo[218]
    DIRECTION INPUT ;
    USE SIGNAL ;
    PORT
      LAYER M5 ;
        RECT  56.976 0 57 0.084 ;
    END
  END esi_lo[218]
  PIN esi_lo[219]
    DIRECTION INPUT ;
    USE SIGNAL ;
    PORT
      LAYER M5 ;
        RECT  57.072 0 57.096 0.084 ;
    END
  END esi_lo[219]
  PIN esi_lo[21]
    DIRECTION INPUT ;
    USE SIGNAL ;
    PORT
      LAYER M5 ;
        RECT  43.44 0 43.464 0.084 ;
    END
  END esi_lo[21]
  PIN esi_lo[220]
    DIRECTION INPUT ;
    USE SIGNAL ;
    PORT
      LAYER M5 ;
        RECT  57.168 0 57.192 0.084 ;
    END
  END esi_lo[220]
  PIN esi_lo[221]
    DIRECTION INPUT ;
    USE SIGNAL ;
    PORT
      LAYER M5 ;
        RECT  57.264 0 57.288 0.084 ;
    END
  END esi_lo[221]
  PIN esi_lo[222]
    DIRECTION INPUT ;
    USE SIGNAL ;
    PORT
      LAYER M5 ;
        RECT  57.36 0 57.384 0.084 ;
    END
  END esi_lo[222]
  PIN esi_lo[223]
    DIRECTION INPUT ;
    USE SIGNAL ;
    PORT
      LAYER M5 ;
        RECT  57.456 0 57.48 0.084 ;
    END
  END esi_lo[223]
  PIN esi_lo[224]
    DIRECTION INPUT ;
    USE SIGNAL ;
    PORT
      LAYER M5 ;
        RECT  51.408 0 51.432 0.084 ;
    END
  END esi_lo[224]
  PIN esi_lo[225]
    DIRECTION INPUT ;
    USE SIGNAL ;
    PORT
      LAYER M5 ;
        RECT  51.504 0 51.528 0.084 ;
    END
  END esi_lo[225]
  PIN esi_lo[226]
    DIRECTION INPUT ;
    USE SIGNAL ;
    PORT
      LAYER M5 ;
        RECT  51.6 0 51.624 0.084 ;
    END
  END esi_lo[226]
  PIN esi_lo[227]
    DIRECTION INPUT ;
    USE SIGNAL ;
    PORT
      LAYER M5 ;
        RECT  51.696 0 51.72 0.084 ;
    END
  END esi_lo[227]
  PIN esi_lo[228]
    DIRECTION INPUT ;
    USE SIGNAL ;
    PORT
      LAYER M5 ;
        RECT  51.792 0 51.816 0.084 ;
    END
  END esi_lo[228]
  PIN esi_lo[229]
    DIRECTION INPUT ;
    USE SIGNAL ;
    PORT
      LAYER M5 ;
        RECT  51.888 0 51.912 0.084 ;
    END
  END esi_lo[229]
  PIN esi_lo[22]
    DIRECTION INPUT ;
    USE SIGNAL ;
    PORT
      LAYER M5 ;
        RECT  43.536 0 43.56 0.084 ;
    END
  END esi_lo[22]
  PIN esi_lo[230]
    DIRECTION INPUT ;
    USE SIGNAL ;
    PORT
      LAYER M5 ;
        RECT  51.984 0 52.008 0.084 ;
    END
  END esi_lo[230]
  PIN esi_lo[231]
    DIRECTION INPUT ;
    USE SIGNAL ;
    PORT
      LAYER M5 ;
        RECT  52.08 0 52.104 0.084 ;
    END
  END esi_lo[231]
  PIN esi_lo[232]
    DIRECTION INPUT ;
    USE SIGNAL ;
    PORT
      LAYER M5 ;
        RECT  52.176 0 52.2 0.084 ;
    END
  END esi_lo[232]
  PIN esi_lo[233]
    DIRECTION INPUT ;
    USE SIGNAL ;
    PORT
      LAYER M5 ;
        RECT  52.272 0 52.296 0.084 ;
    END
  END esi_lo[233]
  PIN esi_lo[234]
    DIRECTION INPUT ;
    USE SIGNAL ;
    PORT
      LAYER M5 ;
        RECT  52.368 0 52.392 0.084 ;
    END
  END esi_lo[234]
  PIN esi_lo[235]
    DIRECTION INPUT ;
    USE SIGNAL ;
    PORT
      LAYER M5 ;
        RECT  52.464 0 52.488 0.084 ;
    END
  END esi_lo[235]
  PIN esi_lo[236]
    DIRECTION INPUT ;
    USE SIGNAL ;
    PORT
      LAYER M5 ;
        RECT  52.56 0 52.584 0.084 ;
    END
  END esi_lo[236]
  PIN esi_lo[237]
    DIRECTION INPUT ;
    USE SIGNAL ;
    PORT
      LAYER M5 ;
        RECT  52.656 0 52.68 0.084 ;
    END
  END esi_lo[237]
  PIN esi_lo[238]
    DIRECTION INPUT ;
    USE SIGNAL ;
    PORT
      LAYER M5 ;
        RECT  52.752 0 52.776 0.084 ;
    END
  END esi_lo[238]
  PIN esi_lo[239]
    DIRECTION INPUT ;
    USE SIGNAL ;
    PORT
      LAYER M5 ;
        RECT  52.848 0 52.872 0.084 ;
    END
  END esi_lo[239]
  PIN esi_lo[23]
    DIRECTION INPUT ;
    USE SIGNAL ;
    PORT
      LAYER M5 ;
        RECT  43.632 0 43.656 0.084 ;
    END
  END esi_lo[23]
  PIN esi_lo[240]
    DIRECTION INPUT ;
    USE SIGNAL ;
    PORT
      LAYER M5 ;
        RECT  52.944 0 52.968 0.084 ;
    END
  END esi_lo[240]
  PIN esi_lo[241]
    DIRECTION INPUT ;
    USE SIGNAL ;
    PORT
      LAYER M5 ;
        RECT  53.04 0 53.064 0.084 ;
    END
  END esi_lo[241]
  PIN esi_lo[242]
    DIRECTION INPUT ;
    USE SIGNAL ;
    PORT
      LAYER M5 ;
        RECT  53.136 0 53.16 0.084 ;
    END
  END esi_lo[242]
  PIN esi_lo[243]
    DIRECTION INPUT ;
    USE SIGNAL ;
    PORT
      LAYER M5 ;
        RECT  53.232 0 53.256 0.084 ;
    END
  END esi_lo[243]
  PIN esi_lo[244]
    DIRECTION INPUT ;
    USE SIGNAL ;
    PORT
      LAYER M5 ;
        RECT  53.328 0 53.352 0.084 ;
    END
  END esi_lo[244]
  PIN esi_lo[245]
    DIRECTION INPUT ;
    USE SIGNAL ;
    PORT
      LAYER M5 ;
        RECT  53.424 0 53.448 0.084 ;
    END
  END esi_lo[245]
  PIN esi_lo[246]
    DIRECTION INPUT ;
    USE SIGNAL ;
    PORT
      LAYER M5 ;
        RECT  53.52 0 53.544 0.084 ;
    END
  END esi_lo[246]
  PIN esi_lo[247]
    DIRECTION INPUT ;
    USE SIGNAL ;
    PORT
      LAYER M5 ;
        RECT  53.616 0 53.64 0.084 ;
    END
  END esi_lo[247]
  PIN esi_lo[248]
    DIRECTION INPUT ;
    USE SIGNAL ;
    PORT
      LAYER M5 ;
        RECT  53.712 0 53.736 0.084 ;
    END
  END esi_lo[248]
  PIN esi_lo[249]
    DIRECTION INPUT ;
    USE SIGNAL ;
    PORT
      LAYER M5 ;
        RECT  53.808 0 53.832 0.084 ;
    END
  END esi_lo[249]
  PIN esi_lo[24]
    DIRECTION INPUT ;
    USE SIGNAL ;
    PORT
      LAYER M5 ;
        RECT  43.728 0 43.752 0.084 ;
    END
  END esi_lo[24]
  PIN esi_lo[250]
    DIRECTION INPUT ;
    USE SIGNAL ;
    PORT
      LAYER M5 ;
        RECT  53.904 0 53.928 0.084 ;
    END
  END esi_lo[250]
  PIN esi_lo[251]
    DIRECTION INPUT ;
    USE SIGNAL ;
    PORT
      LAYER M5 ;
        RECT  54 0 54.024 0.084 ;
    END
  END esi_lo[251]
  PIN esi_lo[252]
    DIRECTION INPUT ;
    USE SIGNAL ;
    PORT
      LAYER M5 ;
        RECT  54.096 0 54.12 0.084 ;
    END
  END esi_lo[252]
  PIN esi_lo[253]
    DIRECTION INPUT ;
    USE SIGNAL ;
    PORT
      LAYER M5 ;
        RECT  54.192 0 54.216 0.084 ;
    END
  END esi_lo[253]
  PIN esi_lo[254]
    DIRECTION INPUT ;
    USE SIGNAL ;
    PORT
      LAYER M5 ;
        RECT  54.288 0 54.312 0.084 ;
    END
  END esi_lo[254]
  PIN esi_lo[255]
    DIRECTION INPUT ;
    USE SIGNAL ;
    PORT
      LAYER M5 ;
        RECT  54.384 0 54.408 0.084 ;
    END
  END esi_lo[255]
  PIN esi_lo[25]
    DIRECTION INPUT ;
    USE SIGNAL ;
    PORT
      LAYER M5 ;
        RECT  43.824 0 43.848 0.084 ;
    END
  END esi_lo[25]
  PIN esi_lo[26]
    DIRECTION INPUT ;
    USE SIGNAL ;
    PORT
      LAYER M5 ;
        RECT  43.92 0 43.944 0.084 ;
    END
  END esi_lo[26]
  PIN esi_lo[27]
    DIRECTION INPUT ;
    USE SIGNAL ;
    PORT
      LAYER M5 ;
        RECT  44.016 0 44.04 0.084 ;
    END
  END esi_lo[27]
  PIN esi_lo[28]
    DIRECTION INPUT ;
    USE SIGNAL ;
    PORT
      LAYER M5 ;
        RECT  44.112 0 44.136 0.084 ;
    END
  END esi_lo[28]
  PIN esi_lo[29]
    DIRECTION INPUT ;
    USE SIGNAL ;
    PORT
      LAYER M5 ;
        RECT  44.208 0 44.232 0.084 ;
    END
  END esi_lo[29]
  PIN esi_lo[2]
    DIRECTION INPUT ;
    USE SIGNAL ;
    PORT
      LAYER M5 ;
        RECT  41.616 0 41.64 0.084 ;
    END
  END esi_lo[2]
  PIN esi_lo[30]
    DIRECTION INPUT ;
    USE SIGNAL ;
    PORT
      LAYER M5 ;
        RECT  44.304 0 44.328 0.084 ;
    END
  END esi_lo[30]
  PIN esi_lo[31]
    DIRECTION INPUT ;
    USE SIGNAL ;
    PORT
      LAYER M5 ;
        RECT  44.4 0 44.424 0.084 ;
    END
  END esi_lo[31]
  PIN esi_lo[32]
    DIRECTION INPUT ;
    USE SIGNAL ;
    PORT
      LAYER M5 ;
        RECT  47.568 0 47.592 0.084 ;
    END
  END esi_lo[32]
  PIN esi_lo[33]
    DIRECTION INPUT ;
    USE SIGNAL ;
    PORT
      LAYER M5 ;
        RECT  47.664 0 47.688 0.084 ;
    END
  END esi_lo[33]
  PIN esi_lo[34]
    DIRECTION INPUT ;
    USE SIGNAL ;
    PORT
      LAYER M5 ;
        RECT  47.76 0 47.784 0.084 ;
    END
  END esi_lo[34]
  PIN esi_lo[35]
    DIRECTION INPUT ;
    USE SIGNAL ;
    PORT
      LAYER M5 ;
        RECT  47.856 0 47.88 0.084 ;
    END
  END esi_lo[35]
  PIN esi_lo[36]
    DIRECTION INPUT ;
    USE SIGNAL ;
    PORT
      LAYER M5 ;
        RECT  47.952 0 47.976 0.084 ;
    END
  END esi_lo[36]
  PIN esi_lo[37]
    DIRECTION INPUT ;
    USE SIGNAL ;
    PORT
      LAYER M5 ;
        RECT  48.048 0 48.072 0.084 ;
    END
  END esi_lo[37]
  PIN esi_lo[38]
    DIRECTION INPUT ;
    USE SIGNAL ;
    PORT
      LAYER M5 ;
        RECT  48.144 0 48.168 0.084 ;
    END
  END esi_lo[38]
  PIN esi_lo[39]
    DIRECTION INPUT ;
    USE SIGNAL ;
    PORT
      LAYER M5 ;
        RECT  48.24 0 48.264 0.084 ;
    END
  END esi_lo[39]
  PIN esi_lo[3]
    DIRECTION INPUT ;
    USE SIGNAL ;
    PORT
      LAYER M5 ;
        RECT  41.712 0 41.736 0.084 ;
    END
  END esi_lo[3]
  PIN esi_lo[40]
    DIRECTION INPUT ;
    USE SIGNAL ;
    PORT
      LAYER M5 ;
        RECT  48.336 0 48.36 0.084 ;
    END
  END esi_lo[40]
  PIN esi_lo[41]
    DIRECTION INPUT ;
    USE SIGNAL ;
    PORT
      LAYER M5 ;
        RECT  48.432 0 48.456 0.084 ;
    END
  END esi_lo[41]
  PIN esi_lo[42]
    DIRECTION INPUT ;
    USE SIGNAL ;
    PORT
      LAYER M5 ;
        RECT  48.528 0 48.552 0.084 ;
    END
  END esi_lo[42]
  PIN esi_lo[43]
    DIRECTION INPUT ;
    USE SIGNAL ;
    PORT
      LAYER M5 ;
        RECT  48.624 0 48.648 0.084 ;
    END
  END esi_lo[43]
  PIN esi_lo[44]
    DIRECTION INPUT ;
    USE SIGNAL ;
    PORT
      LAYER M5 ;
        RECT  48.72 0 48.744 0.084 ;
    END
  END esi_lo[44]
  PIN esi_lo[45]
    DIRECTION INPUT ;
    USE SIGNAL ;
    PORT
      LAYER M5 ;
        RECT  48.816 0 48.84 0.084 ;
    END
  END esi_lo[45]
  PIN esi_lo[46]
    DIRECTION INPUT ;
    USE SIGNAL ;
    PORT
      LAYER M5 ;
        RECT  48.912 0 48.936 0.084 ;
    END
  END esi_lo[46]
  PIN esi_lo[47]
    DIRECTION INPUT ;
    USE SIGNAL ;
    PORT
      LAYER M5 ;
        RECT  49.008 0 49.032 0.084 ;
    END
  END esi_lo[47]
  PIN esi_lo[48]
    DIRECTION INPUT ;
    USE SIGNAL ;
    PORT
      LAYER M5 ;
        RECT  49.104 0 49.128 0.084 ;
    END
  END esi_lo[48]
  PIN esi_lo[49]
    DIRECTION INPUT ;
    USE SIGNAL ;
    PORT
      LAYER M5 ;
        RECT  49.2 0 49.224 0.084 ;
    END
  END esi_lo[49]
  PIN esi_lo[4]
    DIRECTION INPUT ;
    USE SIGNAL ;
    PORT
      LAYER M5 ;
        RECT  41.808 0 41.832 0.084 ;
    END
  END esi_lo[4]
  PIN esi_lo[50]
    DIRECTION INPUT ;
    USE SIGNAL ;
    PORT
      LAYER M5 ;
        RECT  49.296 0 49.32 0.084 ;
    END
  END esi_lo[50]
  PIN esi_lo[51]
    DIRECTION INPUT ;
    USE SIGNAL ;
    PORT
      LAYER M5 ;
        RECT  49.392 0 49.416 0.084 ;
    END
  END esi_lo[51]
  PIN esi_lo[52]
    DIRECTION INPUT ;
    USE SIGNAL ;
    PORT
      LAYER M5 ;
        RECT  49.488 0 49.512 0.084 ;
    END
  END esi_lo[52]
  PIN esi_lo[53]
    DIRECTION INPUT ;
    USE SIGNAL ;
    PORT
      LAYER M5 ;
        RECT  49.584 0 49.608 0.084 ;
    END
  END esi_lo[53]
  PIN esi_lo[54]
    DIRECTION INPUT ;
    USE SIGNAL ;
    PORT
      LAYER M5 ;
        RECT  49.68 0 49.704 0.084 ;
    END
  END esi_lo[54]
  PIN esi_lo[55]
    DIRECTION INPUT ;
    USE SIGNAL ;
    PORT
      LAYER M5 ;
        RECT  49.776 0 49.8 0.084 ;
    END
  END esi_lo[55]
  PIN esi_lo[56]
    DIRECTION INPUT ;
    USE SIGNAL ;
    PORT
      LAYER M5 ;
        RECT  49.872 0 49.896 0.084 ;
    END
  END esi_lo[56]
  PIN esi_lo[57]
    DIRECTION INPUT ;
    USE SIGNAL ;
    PORT
      LAYER M5 ;
        RECT  49.968 0 49.992 0.084 ;
    END
  END esi_lo[57]
  PIN esi_lo[58]
    DIRECTION INPUT ;
    USE SIGNAL ;
    PORT
      LAYER M5 ;
        RECT  50.064 0 50.088 0.084 ;
    END
  END esi_lo[58]
  PIN esi_lo[59]
    DIRECTION INPUT ;
    USE SIGNAL ;
    PORT
      LAYER M5 ;
        RECT  50.16 0 50.184 0.084 ;
    END
  END esi_lo[59]
  PIN esi_lo[5]
    DIRECTION INPUT ;
    USE SIGNAL ;
    PORT
      LAYER M5 ;
        RECT  41.904 0 41.928 0.084 ;
    END
  END esi_lo[5]
  PIN esi_lo[60]
    DIRECTION INPUT ;
    USE SIGNAL ;
    PORT
      LAYER M5 ;
        RECT  50.256 0 50.28 0.084 ;
    END
  END esi_lo[60]
  PIN esi_lo[61]
    DIRECTION INPUT ;
    USE SIGNAL ;
    PORT
      LAYER M5 ;
        RECT  50.352 0 50.376 0.084 ;
    END
  END esi_lo[61]
  PIN esi_lo[62]
    DIRECTION INPUT ;
    USE SIGNAL ;
    PORT
      LAYER M5 ;
        RECT  50.448 0 50.472 0.084 ;
    END
  END esi_lo[62]
  PIN esi_lo[63]
    DIRECTION INPUT ;
    USE SIGNAL ;
    PORT
      LAYER M5 ;
        RECT  50.544 0 50.568 0.084 ;
    END
  END esi_lo[63]
  PIN esi_lo[64]
    DIRECTION INPUT ;
    USE SIGNAL ;
    PORT
      LAYER M5 ;
        RECT  38.352 0 38.376 0.084 ;
    END
  END esi_lo[64]
  PIN esi_lo[65]
    DIRECTION INPUT ;
    USE SIGNAL ;
    PORT
      LAYER M5 ;
        RECT  38.448 0 38.472 0.084 ;
    END
  END esi_lo[65]
  PIN esi_lo[66]
    DIRECTION INPUT ;
    USE SIGNAL ;
    PORT
      LAYER M5 ;
        RECT  38.544 0 38.568 0.084 ;
    END
  END esi_lo[66]
  PIN esi_lo[67]
    DIRECTION INPUT ;
    USE SIGNAL ;
    PORT
      LAYER M5 ;
        RECT  38.64 0 38.664 0.084 ;
    END
  END esi_lo[67]
  PIN esi_lo[68]
    DIRECTION INPUT ;
    USE SIGNAL ;
    PORT
      LAYER M5 ;
        RECT  38.736 0 38.76 0.084 ;
    END
  END esi_lo[68]
  PIN esi_lo[69]
    DIRECTION INPUT ;
    USE SIGNAL ;
    PORT
      LAYER M5 ;
        RECT  38.832 0 38.856 0.084 ;
    END
  END esi_lo[69]
  PIN esi_lo[6]
    DIRECTION INPUT ;
    USE SIGNAL ;
    PORT
      LAYER M5 ;
        RECT  42 0 42.024 0.084 ;
    END
  END esi_lo[6]
  PIN esi_lo[70]
    DIRECTION INPUT ;
    USE SIGNAL ;
    PORT
      LAYER M5 ;
        RECT  38.928 0 38.952 0.084 ;
    END
  END esi_lo[70]
  PIN esi_lo[71]
    DIRECTION INPUT ;
    USE SIGNAL ;
    PORT
      LAYER M5 ;
        RECT  39.024 0 39.048 0.084 ;
    END
  END esi_lo[71]
  PIN esi_lo[72]
    DIRECTION INPUT ;
    USE SIGNAL ;
    PORT
      LAYER M5 ;
        RECT  39.12 0 39.144 0.084 ;
    END
  END esi_lo[72]
  PIN esi_lo[73]
    DIRECTION INPUT ;
    USE SIGNAL ;
    PORT
      LAYER M5 ;
        RECT  39.216 0 39.24 0.084 ;
    END
  END esi_lo[73]
  PIN esi_lo[74]
    DIRECTION INPUT ;
    USE SIGNAL ;
    PORT
      LAYER M5 ;
        RECT  39.312 0 39.336 0.084 ;
    END
  END esi_lo[74]
  PIN esi_lo[75]
    DIRECTION INPUT ;
    USE SIGNAL ;
    PORT
      LAYER M5 ;
        RECT  39.408 0 39.432 0.084 ;
    END
  END esi_lo[75]
  PIN esi_lo[76]
    DIRECTION INPUT ;
    USE SIGNAL ;
    PORT
      LAYER M5 ;
        RECT  39.504 0 39.528 0.084 ;
    END
  END esi_lo[76]
  PIN esi_lo[77]
    DIRECTION INPUT ;
    USE SIGNAL ;
    PORT
      LAYER M5 ;
        RECT  39.6 0 39.624 0.084 ;
    END
  END esi_lo[77]
  PIN esi_lo[78]
    DIRECTION INPUT ;
    USE SIGNAL ;
    PORT
      LAYER M5 ;
        RECT  39.696 0 39.72 0.084 ;
    END
  END esi_lo[78]
  PIN esi_lo[79]
    DIRECTION INPUT ;
    USE SIGNAL ;
    PORT
      LAYER M5 ;
        RECT  39.792 0 39.816 0.084 ;
    END
  END esi_lo[79]
  PIN esi_lo[7]
    DIRECTION INPUT ;
    USE SIGNAL ;
    PORT
      LAYER M5 ;
        RECT  42.096 0 42.12 0.084 ;
    END
  END esi_lo[7]
  PIN esi_lo[80]
    DIRECTION INPUT ;
    USE SIGNAL ;
    PORT
      LAYER M5 ;
        RECT  39.888 0 39.912 0.084 ;
    END
  END esi_lo[80]
  PIN esi_lo[81]
    DIRECTION INPUT ;
    USE SIGNAL ;
    PORT
      LAYER M5 ;
        RECT  39.984 0 40.008 0.084 ;
    END
  END esi_lo[81]
  PIN esi_lo[82]
    DIRECTION INPUT ;
    USE SIGNAL ;
    PORT
      LAYER M5 ;
        RECT  40.08 0 40.104 0.084 ;
    END
  END esi_lo[82]
  PIN esi_lo[83]
    DIRECTION INPUT ;
    USE SIGNAL ;
    PORT
      LAYER M5 ;
        RECT  40.176 0 40.2 0.084 ;
    END
  END esi_lo[83]
  PIN esi_lo[84]
    DIRECTION INPUT ;
    USE SIGNAL ;
    PORT
      LAYER M5 ;
        RECT  40.272 0 40.296 0.084 ;
    END
  END esi_lo[84]
  PIN esi_lo[85]
    DIRECTION INPUT ;
    USE SIGNAL ;
    PORT
      LAYER M5 ;
        RECT  40.368 0 40.392 0.084 ;
    END
  END esi_lo[85]
  PIN esi_lo[86]
    DIRECTION INPUT ;
    USE SIGNAL ;
    PORT
      LAYER M5 ;
        RECT  40.464 0 40.488 0.084 ;
    END
  END esi_lo[86]
  PIN esi_lo[87]
    DIRECTION INPUT ;
    USE SIGNAL ;
    PORT
      LAYER M5 ;
        RECT  40.56 0 40.584 0.084 ;
    END
  END esi_lo[87]
  PIN esi_lo[88]
    DIRECTION INPUT ;
    USE SIGNAL ;
    PORT
      LAYER M5 ;
        RECT  40.656 0 40.68 0.084 ;
    END
  END esi_lo[88]
  PIN esi_lo[89]
    DIRECTION INPUT ;
    USE SIGNAL ;
    PORT
      LAYER M5 ;
        RECT  40.752 0 40.776 0.084 ;
    END
  END esi_lo[89]
  PIN esi_lo[8]
    DIRECTION INPUT ;
    USE SIGNAL ;
    PORT
      LAYER M5 ;
        RECT  42.192 0 42.216 0.084 ;
    END
  END esi_lo[8]
  PIN esi_lo[90]
    DIRECTION INPUT ;
    USE SIGNAL ;
    PORT
      LAYER M5 ;
        RECT  40.848 0 40.872 0.084 ;
    END
  END esi_lo[90]
  PIN esi_lo[91]
    DIRECTION INPUT ;
    USE SIGNAL ;
    PORT
      LAYER M5 ;
        RECT  40.944 0 40.968 0.084 ;
    END
  END esi_lo[91]
  PIN esi_lo[92]
    DIRECTION INPUT ;
    USE SIGNAL ;
    PORT
      LAYER M5 ;
        RECT  41.04 0 41.064 0.084 ;
    END
  END esi_lo[92]
  PIN esi_lo[93]
    DIRECTION INPUT ;
    USE SIGNAL ;
    PORT
      LAYER M5 ;
        RECT  41.136 0 41.16 0.084 ;
    END
  END esi_lo[93]
  PIN esi_lo[94]
    DIRECTION INPUT ;
    USE SIGNAL ;
    PORT
      LAYER M5 ;
        RECT  41.232 0 41.256 0.084 ;
    END
  END esi_lo[94]
  PIN esi_lo[95]
    DIRECTION INPUT ;
    USE SIGNAL ;
    PORT
      LAYER M5 ;
        RECT  41.328 0 41.352 0.084 ;
    END
  END esi_lo[95]
  PIN esi_lo[96]
    DIRECTION INPUT ;
    USE SIGNAL ;
    PORT
      LAYER M5 ;
        RECT  44.496 0 44.52 0.084 ;
    END
  END esi_lo[96]
  PIN esi_lo[97]
    DIRECTION INPUT ;
    USE SIGNAL ;
    PORT
      LAYER M5 ;
        RECT  44.592 0 44.616 0.084 ;
    END
  END esi_lo[97]
  PIN esi_lo[98]
    DIRECTION INPUT ;
    USE SIGNAL ;
    PORT
      LAYER M5 ;
        RECT  44.688 0 44.712 0.084 ;
    END
  END esi_lo[98]
  PIN esi_lo[99]
    DIRECTION INPUT ;
    USE SIGNAL ;
    PORT
      LAYER M5 ;
        RECT  44.784 0 44.808 0.084 ;
    END
  END esi_lo[99]
  PIN esi_lo[9]
    DIRECTION INPUT ;
    USE SIGNAL ;
    PORT
      LAYER M5 ;
        RECT  42.288 0 42.312 0.084 ;
    END
  END esi_lo[9]
  PIN eso_v_hi[0]
    DIRECTION INPUT ;
    USE SIGNAL ;
    PORT
      LAYER M5 ;
        RECT  2.16 43.116 2.184 43.2 ;
    END
  END eso_v_hi[0]
  PIN eso_v_hi[1]
    DIRECTION INPUT ;
    USE SIGNAL ;
    PORT
      LAYER M5 ;
        RECT  2.256 43.116 2.28 43.2 ;
    END
  END eso_v_hi[1]
  PIN eso_v_hi[2]
    DIRECTION INPUT ;
    USE SIGNAL ;
    PORT
      LAYER M5 ;
        RECT  2.352 43.116 2.376 43.2 ;
    END
  END eso_v_hi[2]
  PIN eso_v_hi[3]
    DIRECTION INPUT ;
    USE SIGNAL ;
    PORT
      LAYER M5 ;
        RECT  2.448 43.116 2.472 43.2 ;
    END
  END eso_v_hi[3]
  PIN eso_v_lo[0]
    DIRECTION INPUT ;
    USE SIGNAL ;
    PORT
      LAYER M5 ;
        RECT  1.872 0 1.896 0.084 ;
    END
  END eso_v_lo[0]
  PIN eso_v_lo[1]
    DIRECTION INPUT ;
    USE SIGNAL ;
    PORT
      LAYER M5 ;
        RECT  1.968 0 1.992 0.084 ;
    END
  END eso_v_lo[1]
  PIN eso_v_lo[2]
    DIRECTION INPUT ;
    USE SIGNAL ;
    PORT
      LAYER M5 ;
        RECT  2.064 0 2.088 0.084 ;
    END
  END eso_v_lo[2]
  PIN eso_v_lo[3]
    DIRECTION INPUT ;
    USE SIGNAL ;
    PORT
      LAYER M5 ;
        RECT  2.16 0 2.184 0.084 ;
    END
  END eso_v_lo[3]
  PIN fault
    DIRECTION OUTPUT ;
    USE SIGNAL ;
    PORT
      LAYER M4 ;
        RECT  0 41.328 0.084 41.352 ;
    END
    PORT
      LAYER M4 ;
        RECT  0.06 41.328 0.569 41.352 ;
    END
  END fault
  PIN read_addr[0]
    DIRECTION INPUT ;
    USE SIGNAL ;
    PORT
      LAYER M4 ;
        RECT  0 14.448 0.084 14.472 ;
    END
  END read_addr[0]
  PIN read_addr[10]
    DIRECTION INPUT ;
    USE SIGNAL ;
    PORT
      LAYER M4 ;
        RECT  0 15.408 0.084 15.432 ;
    END
  END read_addr[10]
  PIN read_addr[11]
    DIRECTION INPUT ;
    USE SIGNAL ;
    PORT
      LAYER M4 ;
        RECT  0 15.504 0.084 15.528 ;
    END
  END read_addr[11]
  PIN read_addr[12]
    DIRECTION INPUT ;
    USE SIGNAL ;
    PORT
      LAYER M4 ;
        RECT  0 15.6 0.084 15.624 ;
    END
  END read_addr[12]
  PIN read_addr[13]
    DIRECTION INPUT ;
    USE SIGNAL ;
    PORT
      LAYER M4 ;
        RECT  0 15.696 0.084 15.72 ;
    END
  END read_addr[13]
  PIN read_addr[14]
    DIRECTION INPUT ;
    USE SIGNAL ;
    PORT
      LAYER M4 ;
        RECT  0 15.792 0.084 15.816 ;
    END
  END read_addr[14]
  PIN read_addr[15]
    DIRECTION INPUT ;
    USE SIGNAL ;
    PORT
      LAYER M4 ;
        RECT  0 15.888 0.084 15.912 ;
    END
  END read_addr[15]
  PIN read_addr[16]
    DIRECTION INPUT ;
    USE SIGNAL ;
    PORT
      LAYER M4 ;
        RECT  0 15.984 0.084 16.008 ;
    END
  END read_addr[16]
  PIN read_addr[17]
    DIRECTION INPUT ;
    USE SIGNAL ;
    PORT
      LAYER M4 ;
        RECT  0 16.08 0.084 16.104 ;
    END
  END read_addr[17]
  PIN read_addr[18]
    DIRECTION INPUT ;
    USE SIGNAL ;
    PORT
      LAYER M4 ;
        RECT  0 16.176 0.084 16.2 ;
    END
  END read_addr[18]
  PIN read_addr[19]
    DIRECTION INPUT ;
    USE SIGNAL ;
    PORT
      LAYER M4 ;
        RECT  0 16.272 0.084 16.296 ;
    END
  END read_addr[19]
  PIN read_addr[1]
    DIRECTION INPUT ;
    USE SIGNAL ;
    PORT
      LAYER M4 ;
        RECT  0 14.544 0.084 14.568 ;
    END
  END read_addr[1]
  PIN read_addr[20]
    DIRECTION INPUT ;
    USE SIGNAL ;
    PORT
      LAYER M4 ;
        RECT  0 16.368 0.084 16.392 ;
    END
  END read_addr[20]
  PIN read_addr[21]
    DIRECTION INPUT ;
    USE SIGNAL ;
    PORT
      LAYER M4 ;
        RECT  0 16.464 0.084 16.488 ;
    END
  END read_addr[21]
  PIN read_addr[22]
    DIRECTION INPUT ;
    USE SIGNAL ;
    PORT
      LAYER M4 ;
        RECT  0 16.56 0.084 16.584 ;
    END
  END read_addr[22]
  PIN read_addr[23]
    DIRECTION INPUT ;
    USE SIGNAL ;
    PORT
      LAYER M4 ;
        RECT  0 16.656 0.084 16.68 ;
    END
  END read_addr[23]
  PIN read_addr[24]
    DIRECTION INPUT ;
    USE SIGNAL ;
    PORT
      LAYER M4 ;
        RECT  0 16.752 0.084 16.776 ;
    END
  END read_addr[24]
  PIN read_addr[25]
    DIRECTION INPUT ;
    USE SIGNAL ;
    PORT
      LAYER M4 ;
        RECT  0 16.848 0.084 16.872 ;
    END
  END read_addr[25]
  PIN read_addr[26]
    DIRECTION INPUT ;
    USE SIGNAL ;
    PORT
      LAYER M4 ;
        RECT  0 16.944 0.084 16.968 ;
    END
  END read_addr[26]
  PIN read_addr[27]
    DIRECTION INPUT ;
    USE SIGNAL ;
    PORT
      LAYER M4 ;
        RECT  0 17.04 0.084 17.064 ;
    END
  END read_addr[27]
  PIN read_addr[28]
    DIRECTION INPUT ;
    USE SIGNAL ;
    PORT
      LAYER M4 ;
        RECT  0 17.136 0.084 17.16 ;
    END
  END read_addr[28]
  PIN read_addr[29]
    DIRECTION INPUT ;
    USE SIGNAL ;
    PORT
      LAYER M4 ;
        RECT  0 17.232 0.084 17.256 ;
    END
  END read_addr[29]
  PIN read_addr[2]
    DIRECTION INPUT ;
    USE SIGNAL ;
    PORT
      LAYER M4 ;
        RECT  0 14.64 0.084 14.664 ;
    END
  END read_addr[2]
  PIN read_addr[30]
    DIRECTION INPUT ;
    USE SIGNAL ;
    PORT
      LAYER M4 ;
        RECT  0 17.328 0.084 17.352 ;
    END
  END read_addr[30]
  PIN read_addr[31]
    DIRECTION INPUT ;
    USE SIGNAL ;
    PORT
      LAYER M4 ;
        RECT  0 17.424 0.084 17.448 ;
    END
  END read_addr[31]
  PIN read_addr[32]
    DIRECTION INPUT ;
    USE SIGNAL ;
    PORT
      LAYER M4 ;
        RECT  0 19.44 0.084 19.464 ;
    END
  END read_addr[32]
  PIN read_addr[33]
    DIRECTION INPUT ;
    USE SIGNAL ;
    PORT
      LAYER M4 ;
        RECT  0 19.536 0.084 19.56 ;
    END
  END read_addr[33]
  PIN read_addr[34]
    DIRECTION INPUT ;
    USE SIGNAL ;
    PORT
      LAYER M4 ;
        RECT  0 19.632 0.084 19.656 ;
    END
  END read_addr[34]
  PIN read_addr[35]
    DIRECTION INPUT ;
    USE SIGNAL ;
    PORT
      LAYER M4 ;
        RECT  0 19.728 0.084 19.752 ;
    END
  END read_addr[35]
  PIN read_addr[36]
    DIRECTION INPUT ;
    USE SIGNAL ;
    PORT
      LAYER M4 ;
        RECT  0 19.824 0.084 19.848 ;
    END
  END read_addr[36]
  PIN read_addr[37]
    DIRECTION INPUT ;
    USE SIGNAL ;
    PORT
      LAYER M4 ;
        RECT  0 19.92 0.084 19.944 ;
    END
  END read_addr[37]
  PIN read_addr[38]
    DIRECTION INPUT ;
    USE SIGNAL ;
    PORT
      LAYER M4 ;
        RECT  0 20.016 0.084 20.04 ;
    END
  END read_addr[38]
  PIN read_addr[39]
    DIRECTION INPUT ;
    USE SIGNAL ;
    PORT
      LAYER M4 ;
        RECT  0 20.112 0.084 20.136 ;
    END
  END read_addr[39]
  PIN read_addr[3]
    DIRECTION INPUT ;
    USE SIGNAL ;
    PORT
      LAYER M4 ;
        RECT  0 14.736 0.084 14.76 ;
    END
  END read_addr[3]
  PIN read_addr[40]
    DIRECTION INPUT ;
    USE SIGNAL ;
    PORT
      LAYER M4 ;
        RECT  0 20.208 0.084 20.232 ;
    END
  END read_addr[40]
  PIN read_addr[41]
    DIRECTION INPUT ;
    USE SIGNAL ;
    PORT
      LAYER M4 ;
        RECT  0 20.304 0.084 20.328 ;
    END
  END read_addr[41]
  PIN read_addr[42]
    DIRECTION INPUT ;
    USE SIGNAL ;
    PORT
      LAYER M4 ;
        RECT  0 20.4 0.084 20.424 ;
    END
  END read_addr[42]
  PIN read_addr[43]
    DIRECTION INPUT ;
    USE SIGNAL ;
    PORT
      LAYER M4 ;
        RECT  0 20.496 0.084 20.52 ;
    END
  END read_addr[43]
  PIN read_addr[4]
    DIRECTION INPUT ;
    USE SIGNAL ;
    PORT
      LAYER M4 ;
        RECT  0 14.832 0.084 14.856 ;
    END
  END read_addr[4]
  PIN read_addr[5]
    DIRECTION INPUT ;
    USE SIGNAL ;
    PORT
      LAYER M4 ;
        RECT  0 14.928 0.084 14.952 ;
    END
  END read_addr[5]
  PIN read_addr[6]
    DIRECTION INPUT ;
    USE SIGNAL ;
    PORT
      LAYER M4 ;
        RECT  0 15.024 0.084 15.048 ;
    END
  END read_addr[6]
  PIN read_addr[7]
    DIRECTION INPUT ;
    USE SIGNAL ;
    PORT
      LAYER M4 ;
        RECT  0 15.12 0.084 15.144 ;
    END
  END read_addr[7]
  PIN read_addr[8]
    DIRECTION INPUT ;
    USE SIGNAL ;
    PORT
      LAYER M4 ;
        RECT  0 15.216 0.084 15.24 ;
    END
  END read_addr[8]
  PIN read_addr[9]
    DIRECTION INPUT ;
    USE SIGNAL ;
    PORT
      LAYER M4 ;
        RECT  0 15.312 0.084 15.336 ;
    END
  END read_addr[9]
  PIN read_v[0]
    DIRECTION INPUT ;
    USE SIGNAL ;
    PORT
      LAYER M4 ;
        RECT  0 2.64 0.084 2.664 ;
    END
  END read_v[0]
  PIN read_v[1]
    DIRECTION INPUT ;
    USE SIGNAL ;
    PORT
      LAYER M4 ;
        RECT  0 2.736 0.084 2.76 ;
    END
  END read_v[1]
  PIN read_v[2]
    DIRECTION INPUT ;
    USE SIGNAL ;
    PORT
      LAYER M4 ;
        RECT  0 2.832 0.084 2.856 ;
    END
  END read_v[2]
  PIN read_v[3]
    DIRECTION INPUT ;
    USE SIGNAL ;
    PORT
      LAYER M4 ;
        RECT  0 2.928 0.084 2.952 ;
    END
  END read_v[3]
  PIN response_addr[0]
    DIRECTION OUTPUT ;
    USE SIGNAL ;
    PORT
      LAYER M4 ;
        RECT  0 25.68 0.084 25.704 ;
    END
  END response_addr[0]
  PIN response_addr[10]
    DIRECTION OUTPUT ;
    USE SIGNAL ;
    PORT
      LAYER M4 ;
        RECT  0 26.64 0.084 26.664 ;
    END
  END response_addr[10]
  PIN response_addr[11]
    DIRECTION OUTPUT ;
    USE SIGNAL ;
    PORT
      LAYER M4 ;
        RECT  0 26.736 0.084 26.76 ;
    END
  END response_addr[11]
  PIN response_addr[12]
    DIRECTION OUTPUT ;
    USE SIGNAL ;
    PORT
      LAYER M4 ;
        RECT  0 26.832 0.084 26.856 ;
    END
  END response_addr[12]
  PIN response_addr[13]
    DIRECTION OUTPUT ;
    USE SIGNAL ;
    PORT
      LAYER M4 ;
        RECT  0 26.928 0.084 26.952 ;
    END
  END response_addr[13]
  PIN response_addr[14]
    DIRECTION OUTPUT ;
    USE SIGNAL ;
    PORT
      LAYER M4 ;
        RECT  0 27.024 0.084 27.048 ;
    END
  END response_addr[14]
  PIN response_addr[15]
    DIRECTION OUTPUT ;
    USE SIGNAL ;
    PORT
      LAYER M4 ;
        RECT  0 27.12 0.084 27.144 ;
    END
  END response_addr[15]
  PIN response_addr[16]
    DIRECTION OUTPUT ;
    USE SIGNAL ;
    PORT
      LAYER M4 ;
        RECT  0 27.216 0.084 27.24 ;
    END
  END response_addr[16]
  PIN response_addr[17]
    DIRECTION OUTPUT ;
    USE SIGNAL ;
    PORT
      LAYER M4 ;
        RECT  0 27.312 0.084 27.336 ;
    END
  END response_addr[17]
  PIN response_addr[18]
    DIRECTION OUTPUT ;
    USE SIGNAL ;
    PORT
      LAYER M4 ;
        RECT  0 27.408 0.084 27.432 ;
    END
  END response_addr[18]
  PIN response_addr[19]
    DIRECTION OUTPUT ;
    USE SIGNAL ;
    PORT
      LAYER M4 ;
        RECT  0 27.504 0.084 27.528 ;
    END
  END response_addr[19]
  PIN response_addr[1]
    DIRECTION OUTPUT ;
    USE SIGNAL ;
    PORT
      LAYER M4 ;
        RECT  0 25.776 0.084 25.8 ;
    END
  END response_addr[1]
  PIN response_addr[20]
    DIRECTION OUTPUT ;
    USE SIGNAL ;
    PORT
      LAYER M4 ;
        RECT  0 27.6 0.084 27.624 ;
    END
  END response_addr[20]
  PIN response_addr[21]
    DIRECTION OUTPUT ;
    USE SIGNAL ;
    PORT
      LAYER M4 ;
        RECT  0 27.696 0.084 27.72 ;
    END
  END response_addr[21]
  PIN response_addr[22]
    DIRECTION OUTPUT ;
    USE SIGNAL ;
    PORT
      LAYER M4 ;
        RECT  0 27.792 0.084 27.816 ;
    END
  END response_addr[22]
  PIN response_addr[23]
    DIRECTION OUTPUT ;
    USE SIGNAL ;
    PORT
      LAYER M4 ;
        RECT  0 27.888 0.084 27.912 ;
    END
  END response_addr[23]
  PIN response_addr[24]
    DIRECTION OUTPUT ;
    USE SIGNAL ;
    PORT
      LAYER M4 ;
        RECT  0 27.984 0.084 28.008 ;
    END
  END response_addr[24]
  PIN response_addr[25]
    DIRECTION OUTPUT ;
    USE SIGNAL ;
    PORT
      LAYER M4 ;
        RECT  0 28.08 0.084 28.104 ;
    END
  END response_addr[25]
  PIN response_addr[26]
    DIRECTION OUTPUT ;
    USE SIGNAL ;
    PORT
      LAYER M4 ;
        RECT  0 28.176 0.084 28.2 ;
    END
  END response_addr[26]
  PIN response_addr[27]
    DIRECTION OUTPUT ;
    USE SIGNAL ;
    PORT
      LAYER M4 ;
        RECT  0 28.272 0.084 28.296 ;
    END
  END response_addr[27]
  PIN response_addr[28]
    DIRECTION OUTPUT ;
    USE SIGNAL ;
    PORT
      LAYER M4 ;
        RECT  0 28.368 0.084 28.392 ;
    END
  END response_addr[28]
  PIN response_addr[29]
    DIRECTION OUTPUT ;
    USE SIGNAL ;
    PORT
      LAYER M4 ;
        RECT  0 28.464 0.084 28.488 ;
    END
  END response_addr[29]
  PIN response_addr[2]
    DIRECTION OUTPUT ;
    USE SIGNAL ;
    PORT
      LAYER M4 ;
        RECT  0 25.872 0.084 25.896 ;
    END
  END response_addr[2]
  PIN response_addr[30]
    DIRECTION OUTPUT ;
    USE SIGNAL ;
    PORT
      LAYER M4 ;
        RECT  0 28.56 0.084 28.584 ;
    END
  END response_addr[30]
  PIN response_addr[31]
    DIRECTION OUTPUT ;
    USE SIGNAL ;
    PORT
      LAYER M4 ;
        RECT  0 28.656 0.084 28.68 ;
    END
  END response_addr[31]
  PIN response_addr[32]
    DIRECTION OUTPUT ;
    USE SIGNAL ;
    PORT
      LAYER M4 ;
        RECT  0 30.672 0.084 30.696 ;
    END
  END response_addr[32]
  PIN response_addr[33]
    DIRECTION OUTPUT ;
    USE SIGNAL ;
    PORT
      LAYER M4 ;
        RECT  0 30.768 0.084 30.792 ;
    END
  END response_addr[33]
  PIN response_addr[34]
    DIRECTION OUTPUT ;
    USE SIGNAL ;
    PORT
      LAYER M4 ;
        RECT  0 30.864 0.084 30.888 ;
    END
  END response_addr[34]
  PIN response_addr[35]
    DIRECTION OUTPUT ;
    USE SIGNAL ;
    PORT
      LAYER M4 ;
        RECT  0 30.96 0.084 30.984 ;
    END
  END response_addr[35]
  PIN response_addr[36]
    DIRECTION OUTPUT ;
    USE SIGNAL ;
    PORT
      LAYER M4 ;
        RECT  0 31.056 0.084 31.08 ;
    END
  END response_addr[36]
  PIN response_addr[37]
    DIRECTION OUTPUT ;
    USE SIGNAL ;
    PORT
      LAYER M4 ;
        RECT  0 31.152 0.084 31.176 ;
    END
  END response_addr[37]
  PIN response_addr[38]
    DIRECTION OUTPUT ;
    USE SIGNAL ;
    PORT
      LAYER M4 ;
        RECT  0 31.248 0.084 31.272 ;
    END
  END response_addr[38]
  PIN response_addr[39]
    DIRECTION OUTPUT ;
    USE SIGNAL ;
    PORT
      LAYER M4 ;
        RECT  0 31.344 0.084 31.368 ;
    END
  END response_addr[39]
  PIN response_addr[3]
    DIRECTION OUTPUT ;
    USE SIGNAL ;
    PORT
      LAYER M4 ;
        RECT  0 25.968 0.084 25.992 ;
    END
  END response_addr[3]
  PIN response_addr[40]
    DIRECTION OUTPUT ;
    USE SIGNAL ;
    PORT
      LAYER M4 ;
        RECT  0 31.44 0.084 31.464 ;
    END
  END response_addr[40]
  PIN response_addr[41]
    DIRECTION OUTPUT ;
    USE SIGNAL ;
    PORT
      LAYER M4 ;
        RECT  0 31.536 0.084 31.56 ;
    END
  END response_addr[41]
  PIN response_addr[42]
    DIRECTION OUTPUT ;
    USE SIGNAL ;
    PORT
      LAYER M4 ;
        RECT  0 31.632 0.084 31.656 ;
    END
  END response_addr[42]
  PIN response_addr[43]
    DIRECTION OUTPUT ;
    USE SIGNAL ;
    PORT
      LAYER M4 ;
        RECT  0 31.728 0.084 31.752 ;
    END
  END response_addr[43]
  PIN response_addr[4]
    DIRECTION OUTPUT ;
    USE SIGNAL ;
    PORT
      LAYER M4 ;
        RECT  0 26.064 0.084 26.088 ;
    END
  END response_addr[4]
  PIN response_addr[5]
    DIRECTION OUTPUT ;
    USE SIGNAL ;
    PORT
      LAYER M4 ;
        RECT  0 26.16 0.084 26.184 ;
    END
  END response_addr[5]
  PIN response_addr[6]
    DIRECTION OUTPUT ;
    USE SIGNAL ;
    PORT
      LAYER M4 ;
        RECT  0 26.256 0.084 26.28 ;
    END
  END response_addr[6]
  PIN response_addr[7]
    DIRECTION OUTPUT ;
    USE SIGNAL ;
    PORT
      LAYER M4 ;
        RECT  0 26.352 0.084 26.376 ;
    END
  END response_addr[7]
  PIN response_addr[8]
    DIRECTION OUTPUT ;
    USE SIGNAL ;
    PORT
      LAYER M4 ;
        RECT  0 26.448 0.084 26.472 ;
    END
  END response_addr[8]
  PIN response_addr[9]
    DIRECTION OUTPUT ;
    USE SIGNAL ;
    PORT
      LAYER M4 ;
        RECT  0 26.544 0.084 26.568 ;
    END
  END response_addr[9]
  PIN response_data[0]
    DIRECTION OUTPUT ;
    USE SIGNAL ;
    PORT
      LAYER M4 ;
        RECT  64.716 32.496 64.8 32.52 ;
    END
  END response_data[0]
  PIN response_data[100]
    DIRECTION OUTPUT ;
    USE SIGNAL ;
    PORT
      LAYER M4 ;
        RECT  64.716 35.952 64.8 35.976 ;
    END
  END response_data[100]
  PIN response_data[101]
    DIRECTION OUTPUT ;
    USE SIGNAL ;
    PORT
      LAYER M4 ;
        RECT  64.716 36.048 64.8 36.072 ;
    END
  END response_data[101]
  PIN response_data[102]
    DIRECTION OUTPUT ;
    USE SIGNAL ;
    PORT
      LAYER M4 ;
        RECT  64.716 36.144 64.8 36.168 ;
    END
  END response_data[102]
  PIN response_data[103]
    DIRECTION OUTPUT ;
    USE SIGNAL ;
    PORT
      LAYER M4 ;
        RECT  64.716 36.24 64.8 36.264 ;
    END
  END response_data[103]
  PIN response_data[104]
    DIRECTION OUTPUT ;
    USE SIGNAL ;
    PORT
      LAYER M4 ;
        RECT  64.716 36.336 64.8 36.36 ;
    END
  END response_data[104]
  PIN response_data[105]
    DIRECTION OUTPUT ;
    USE SIGNAL ;
    PORT
      LAYER M4 ;
        RECT  64.716 36.432 64.8 36.456 ;
    END
  END response_data[105]
  PIN response_data[106]
    DIRECTION OUTPUT ;
    USE SIGNAL ;
    PORT
      LAYER M4 ;
        RECT  64.716 36.528 64.8 36.552 ;
    END
  END response_data[106]
  PIN response_data[107]
    DIRECTION OUTPUT ;
    USE SIGNAL ;
    PORT
      LAYER M4 ;
        RECT  64.716 36.624 64.8 36.648 ;
    END
  END response_data[107]
  PIN response_data[108]
    DIRECTION OUTPUT ;
    USE SIGNAL ;
    PORT
      LAYER M4 ;
        RECT  64.716 36.72 64.8 36.744 ;
    END
  END response_data[108]
  PIN response_data[109]
    DIRECTION OUTPUT ;
    USE SIGNAL ;
    PORT
      LAYER M4 ;
        RECT  64.716 36.816 64.8 36.84 ;
    END
  END response_data[109]
  PIN response_data[10]
    DIRECTION OUTPUT ;
    USE SIGNAL ;
    PORT
      LAYER M4 ;
        RECT  64.716 33.456 64.8 33.48 ;
    END
  END response_data[10]
  PIN response_data[110]
    DIRECTION OUTPUT ;
    USE SIGNAL ;
    PORT
      LAYER M4 ;
        RECT  64.716 36.912 64.8 36.936 ;
    END
  END response_data[110]
  PIN response_data[111]
    DIRECTION OUTPUT ;
    USE SIGNAL ;
    PORT
      LAYER M4 ;
        RECT  64.716 37.008 64.8 37.032 ;
    END
  END response_data[111]
  PIN response_data[112]
    DIRECTION OUTPUT ;
    USE SIGNAL ;
    PORT
      LAYER M4 ;
        RECT  64.716 37.104 64.8 37.128 ;
    END
  END response_data[112]
  PIN response_data[113]
    DIRECTION OUTPUT ;
    USE SIGNAL ;
    PORT
      LAYER M4 ;
        RECT  64.716 37.2 64.8 37.224 ;
    END
  END response_data[113]
  PIN response_data[114]
    DIRECTION OUTPUT ;
    USE SIGNAL ;
    PORT
      LAYER M4 ;
        RECT  64.716 37.296 64.8 37.32 ;
    END
  END response_data[114]
  PIN response_data[115]
    DIRECTION OUTPUT ;
    USE SIGNAL ;
    PORT
      LAYER M4 ;
        RECT  64.716 37.392 64.8 37.416 ;
    END
  END response_data[115]
  PIN response_data[116]
    DIRECTION OUTPUT ;
    USE SIGNAL ;
    PORT
      LAYER M4 ;
        RECT  64.716 37.488 64.8 37.512 ;
    END
  END response_data[116]
  PIN response_data[117]
    DIRECTION OUTPUT ;
    USE SIGNAL ;
    PORT
      LAYER M4 ;
        RECT  64.716 37.584 64.8 37.608 ;
    END
  END response_data[117]
  PIN response_data[118]
    DIRECTION OUTPUT ;
    USE SIGNAL ;
    PORT
      LAYER M4 ;
        RECT  64.716 37.68 64.8 37.704 ;
    END
  END response_data[118]
  PIN response_data[119]
    DIRECTION OUTPUT ;
    USE SIGNAL ;
    PORT
      LAYER M4 ;
        RECT  64.716 37.776 64.8 37.8 ;
    END
  END response_data[119]
  PIN response_data[11]
    DIRECTION OUTPUT ;
    USE SIGNAL ;
    PORT
      LAYER M4 ;
        RECT  64.716 33.552 64.8 33.576 ;
    END
  END response_data[11]
  PIN response_data[120]
    DIRECTION OUTPUT ;
    USE SIGNAL ;
    PORT
      LAYER M4 ;
        RECT  64.716 37.872 64.8 37.896 ;
    END
  END response_data[120]
  PIN response_data[121]
    DIRECTION OUTPUT ;
    USE SIGNAL ;
    PORT
      LAYER M4 ;
        RECT  64.716 37.968 64.8 37.992 ;
    END
  END response_data[121]
  PIN response_data[122]
    DIRECTION OUTPUT ;
    USE SIGNAL ;
    PORT
      LAYER M4 ;
        RECT  64.716 38.064 64.8 38.088 ;
    END
  END response_data[122]
  PIN response_data[123]
    DIRECTION OUTPUT ;
    USE SIGNAL ;
    PORT
      LAYER M4 ;
        RECT  64.716 38.16 64.8 38.184 ;
    END
  END response_data[123]
  PIN response_data[124]
    DIRECTION OUTPUT ;
    USE SIGNAL ;
    PORT
      LAYER M4 ;
        RECT  64.716 38.256 64.8 38.28 ;
    END
  END response_data[124]
  PIN response_data[125]
    DIRECTION OUTPUT ;
    USE SIGNAL ;
    PORT
      LAYER M4 ;
        RECT  64.716 38.352 64.8 38.376 ;
    END
  END response_data[125]
  PIN response_data[126]
    DIRECTION OUTPUT ;
    USE SIGNAL ;
    PORT
      LAYER M4 ;
        RECT  64.716 38.448 64.8 38.472 ;
    END
  END response_data[126]
  PIN response_data[127]
    DIRECTION OUTPUT ;
    USE SIGNAL ;
    PORT
      LAYER M4 ;
        RECT  64.716 38.544 64.8 38.568 ;
    END
  END response_data[127]
  PIN response_data[128]
    DIRECTION OUTPUT ;
    USE SIGNAL ;
    PORT
      LAYER M4 ;
        RECT  64.716 26.352 64.8 26.376 ;
    END
  END response_data[128]
  PIN response_data[129]
    DIRECTION OUTPUT ;
    USE SIGNAL ;
    PORT
      LAYER M4 ;
        RECT  64.716 26.448 64.8 26.472 ;
    END
  END response_data[129]
  PIN response_data[12]
    DIRECTION OUTPUT ;
    USE SIGNAL ;
    PORT
      LAYER M4 ;
        RECT  64.716 33.648 64.8 33.672 ;
    END
  END response_data[12]
  PIN response_data[130]
    DIRECTION OUTPUT ;
    USE SIGNAL ;
    PORT
      LAYER M4 ;
        RECT  64.716 26.544 64.8 26.568 ;
    END
  END response_data[130]
  PIN response_data[131]
    DIRECTION OUTPUT ;
    USE SIGNAL ;
    PORT
      LAYER M4 ;
        RECT  64.716 26.64 64.8 26.664 ;
    END
  END response_data[131]
  PIN response_data[132]
    DIRECTION OUTPUT ;
    USE SIGNAL ;
    PORT
      LAYER M4 ;
        RECT  64.716 26.736 64.8 26.76 ;
    END
  END response_data[132]
  PIN response_data[133]
    DIRECTION OUTPUT ;
    USE SIGNAL ;
    PORT
      LAYER M4 ;
        RECT  64.716 26.832 64.8 26.856 ;
    END
  END response_data[133]
  PIN response_data[134]
    DIRECTION OUTPUT ;
    USE SIGNAL ;
    PORT
      LAYER M4 ;
        RECT  64.716 26.928 64.8 26.952 ;
    END
  END response_data[134]
  PIN response_data[135]
    DIRECTION OUTPUT ;
    USE SIGNAL ;
    PORT
      LAYER M4 ;
        RECT  64.716 27.024 64.8 27.048 ;
    END
  END response_data[135]
  PIN response_data[136]
    DIRECTION OUTPUT ;
    USE SIGNAL ;
    PORT
      LAYER M4 ;
        RECT  64.716 27.12 64.8 27.144 ;
    END
  END response_data[136]
  PIN response_data[137]
    DIRECTION OUTPUT ;
    USE SIGNAL ;
    PORT
      LAYER M4 ;
        RECT  64.716 27.216 64.8 27.24 ;
    END
  END response_data[137]
  PIN response_data[138]
    DIRECTION OUTPUT ;
    USE SIGNAL ;
    PORT
      LAYER M4 ;
        RECT  64.716 27.312 64.8 27.336 ;
    END
  END response_data[138]
  PIN response_data[139]
    DIRECTION OUTPUT ;
    USE SIGNAL ;
    PORT
      LAYER M4 ;
        RECT  64.716 27.408 64.8 27.432 ;
    END
  END response_data[139]
  PIN response_data[13]
    DIRECTION OUTPUT ;
    USE SIGNAL ;
    PORT
      LAYER M4 ;
        RECT  64.716 33.744 64.8 33.768 ;
    END
  END response_data[13]
  PIN response_data[140]
    DIRECTION OUTPUT ;
    USE SIGNAL ;
    PORT
      LAYER M4 ;
        RECT  64.716 27.504 64.8 27.528 ;
    END
  END response_data[140]
  PIN response_data[141]
    DIRECTION OUTPUT ;
    USE SIGNAL ;
    PORT
      LAYER M4 ;
        RECT  64.716 27.6 64.8 27.624 ;
    END
  END response_data[141]
  PIN response_data[142]
    DIRECTION OUTPUT ;
    USE SIGNAL ;
    PORT
      LAYER M4 ;
        RECT  64.716 27.696 64.8 27.72 ;
    END
  END response_data[142]
  PIN response_data[143]
    DIRECTION OUTPUT ;
    USE SIGNAL ;
    PORT
      LAYER M4 ;
        RECT  64.716 27.792 64.8 27.816 ;
    END
  END response_data[143]
  PIN response_data[144]
    DIRECTION OUTPUT ;
    USE SIGNAL ;
    PORT
      LAYER M4 ;
        RECT  64.716 27.888 64.8 27.912 ;
    END
  END response_data[144]
  PIN response_data[145]
    DIRECTION OUTPUT ;
    USE SIGNAL ;
    PORT
      LAYER M4 ;
        RECT  64.716 27.984 64.8 28.008 ;
    END
  END response_data[145]
  PIN response_data[146]
    DIRECTION OUTPUT ;
    USE SIGNAL ;
    PORT
      LAYER M4 ;
        RECT  64.716 28.08 64.8 28.104 ;
    END
  END response_data[146]
  PIN response_data[147]
    DIRECTION OUTPUT ;
    USE SIGNAL ;
    PORT
      LAYER M4 ;
        RECT  64.716 28.176 64.8 28.2 ;
    END
  END response_data[147]
  PIN response_data[148]
    DIRECTION OUTPUT ;
    USE SIGNAL ;
    PORT
      LAYER M4 ;
        RECT  64.716 28.272 64.8 28.296 ;
    END
  END response_data[148]
  PIN response_data[149]
    DIRECTION OUTPUT ;
    USE SIGNAL ;
    PORT
      LAYER M4 ;
        RECT  64.716 28.368 64.8 28.392 ;
    END
  END response_data[149]
  PIN response_data[14]
    DIRECTION OUTPUT ;
    USE SIGNAL ;
    PORT
      LAYER M4 ;
        RECT  64.716 33.84 64.8 33.864 ;
    END
  END response_data[14]
  PIN response_data[150]
    DIRECTION OUTPUT ;
    USE SIGNAL ;
    PORT
      LAYER M4 ;
        RECT  64.716 28.464 64.8 28.488 ;
    END
  END response_data[150]
  PIN response_data[151]
    DIRECTION OUTPUT ;
    USE SIGNAL ;
    PORT
      LAYER M4 ;
        RECT  64.716 28.56 64.8 28.584 ;
    END
  END response_data[151]
  PIN response_data[152]
    DIRECTION OUTPUT ;
    USE SIGNAL ;
    PORT
      LAYER M4 ;
        RECT  64.716 28.656 64.8 28.68 ;
    END
  END response_data[152]
  PIN response_data[153]
    DIRECTION OUTPUT ;
    USE SIGNAL ;
    PORT
      LAYER M4 ;
        RECT  64.716 28.752 64.8 28.776 ;
    END
  END response_data[153]
  PIN response_data[154]
    DIRECTION OUTPUT ;
    USE SIGNAL ;
    PORT
      LAYER M4 ;
        RECT  64.716 28.848 64.8 28.872 ;
    END
  END response_data[154]
  PIN response_data[155]
    DIRECTION OUTPUT ;
    USE SIGNAL ;
    PORT
      LAYER M4 ;
        RECT  64.716 28.944 64.8 28.968 ;
    END
  END response_data[155]
  PIN response_data[156]
    DIRECTION OUTPUT ;
    USE SIGNAL ;
    PORT
      LAYER M4 ;
        RECT  64.716 29.04 64.8 29.064 ;
    END
  END response_data[156]
  PIN response_data[157]
    DIRECTION OUTPUT ;
    USE SIGNAL ;
    PORT
      LAYER M4 ;
        RECT  64.716 29.136 64.8 29.16 ;
    END
  END response_data[157]
  PIN response_data[158]
    DIRECTION OUTPUT ;
    USE SIGNAL ;
    PORT
      LAYER M4 ;
        RECT  64.716 29.232 64.8 29.256 ;
    END
  END response_data[158]
  PIN response_data[159]
    DIRECTION OUTPUT ;
    USE SIGNAL ;
    PORT
      LAYER M4 ;
        RECT  64.716 29.328 64.8 29.352 ;
    END
  END response_data[159]
  PIN response_data[15]
    DIRECTION OUTPUT ;
    USE SIGNAL ;
    PORT
      LAYER M4 ;
        RECT  64.716 33.936 64.8 33.96 ;
    END
  END response_data[15]
  PIN response_data[160]
    DIRECTION OUTPUT ;
    USE SIGNAL ;
    PORT
      LAYER M4 ;
        RECT  64.716 23.28 64.8 23.304 ;
    END
  END response_data[160]
  PIN response_data[161]
    DIRECTION OUTPUT ;
    USE SIGNAL ;
    PORT
      LAYER M4 ;
        RECT  64.716 23.376 64.8 23.4 ;
    END
  END response_data[161]
  PIN response_data[162]
    DIRECTION OUTPUT ;
    USE SIGNAL ;
    PORT
      LAYER M4 ;
        RECT  64.716 23.472 64.8 23.496 ;
    END
  END response_data[162]
  PIN response_data[163]
    DIRECTION OUTPUT ;
    USE SIGNAL ;
    PORT
      LAYER M4 ;
        RECT  64.716 23.568 64.8 23.592 ;
    END
  END response_data[163]
  PIN response_data[164]
    DIRECTION OUTPUT ;
    USE SIGNAL ;
    PORT
      LAYER M4 ;
        RECT  64.716 23.664 64.8 23.688 ;
    END
  END response_data[164]
  PIN response_data[165]
    DIRECTION OUTPUT ;
    USE SIGNAL ;
    PORT
      LAYER M4 ;
        RECT  64.716 23.76 64.8 23.784 ;
    END
  END response_data[165]
  PIN response_data[166]
    DIRECTION OUTPUT ;
    USE SIGNAL ;
    PORT
      LAYER M4 ;
        RECT  64.716 23.856 64.8 23.88 ;
    END
  END response_data[166]
  PIN response_data[167]
    DIRECTION OUTPUT ;
    USE SIGNAL ;
    PORT
      LAYER M4 ;
        RECT  64.716 23.952 64.8 23.976 ;
    END
  END response_data[167]
  PIN response_data[168]
    DIRECTION OUTPUT ;
    USE SIGNAL ;
    PORT
      LAYER M4 ;
        RECT  64.716 24.048 64.8 24.072 ;
    END
  END response_data[168]
  PIN response_data[169]
    DIRECTION OUTPUT ;
    USE SIGNAL ;
    PORT
      LAYER M4 ;
        RECT  64.716 24.144 64.8 24.168 ;
    END
  END response_data[169]
  PIN response_data[16]
    DIRECTION OUTPUT ;
    USE SIGNAL ;
    PORT
      LAYER M4 ;
        RECT  64.716 34.032 64.8 34.056 ;
    END
  END response_data[16]
  PIN response_data[170]
    DIRECTION OUTPUT ;
    USE SIGNAL ;
    PORT
      LAYER M4 ;
        RECT  64.716 24.24 64.8 24.264 ;
    END
  END response_data[170]
  PIN response_data[171]
    DIRECTION OUTPUT ;
    USE SIGNAL ;
    PORT
      LAYER M4 ;
        RECT  64.716 24.336 64.8 24.36 ;
    END
  END response_data[171]
  PIN response_data[172]
    DIRECTION OUTPUT ;
    USE SIGNAL ;
    PORT
      LAYER M4 ;
        RECT  64.716 24.432 64.8 24.456 ;
    END
  END response_data[172]
  PIN response_data[173]
    DIRECTION OUTPUT ;
    USE SIGNAL ;
    PORT
      LAYER M4 ;
        RECT  64.716 24.528 64.8 24.552 ;
    END
  END response_data[173]
  PIN response_data[174]
    DIRECTION OUTPUT ;
    USE SIGNAL ;
    PORT
      LAYER M4 ;
        RECT  64.716 24.624 64.8 24.648 ;
    END
  END response_data[174]
  PIN response_data[175]
    DIRECTION OUTPUT ;
    USE SIGNAL ;
    PORT
      LAYER M4 ;
        RECT  64.716 24.72 64.8 24.744 ;
    END
  END response_data[175]
  PIN response_data[176]
    DIRECTION OUTPUT ;
    USE SIGNAL ;
    PORT
      LAYER M4 ;
        RECT  64.716 24.816 64.8 24.84 ;
    END
  END response_data[176]
  PIN response_data[177]
    DIRECTION OUTPUT ;
    USE SIGNAL ;
    PORT
      LAYER M4 ;
        RECT  64.716 24.912 64.8 24.936 ;
    END
  END response_data[177]
  PIN response_data[178]
    DIRECTION OUTPUT ;
    USE SIGNAL ;
    PORT
      LAYER M4 ;
        RECT  64.716 25.008 64.8 25.032 ;
    END
  END response_data[178]
  PIN response_data[179]
    DIRECTION OUTPUT ;
    USE SIGNAL ;
    PORT
      LAYER M4 ;
        RECT  64.716 25.104 64.8 25.128 ;
    END
  END response_data[179]
  PIN response_data[17]
    DIRECTION OUTPUT ;
    USE SIGNAL ;
    PORT
      LAYER M4 ;
        RECT  64.716 34.128 64.8 34.152 ;
    END
  END response_data[17]
  PIN response_data[180]
    DIRECTION OUTPUT ;
    USE SIGNAL ;
    PORT
      LAYER M4 ;
        RECT  64.716 25.2 64.8 25.224 ;
    END
  END response_data[180]
  PIN response_data[181]
    DIRECTION OUTPUT ;
    USE SIGNAL ;
    PORT
      LAYER M4 ;
        RECT  64.716 25.296 64.8 25.32 ;
    END
  END response_data[181]
  PIN response_data[182]
    DIRECTION OUTPUT ;
    USE SIGNAL ;
    PORT
      LAYER M4 ;
        RECT  64.716 25.392 64.8 25.416 ;
    END
  END response_data[182]
  PIN response_data[183]
    DIRECTION OUTPUT ;
    USE SIGNAL ;
    PORT
      LAYER M4 ;
        RECT  64.716 25.488 64.8 25.512 ;
    END
  END response_data[183]
  PIN response_data[184]
    DIRECTION OUTPUT ;
    USE SIGNAL ;
    PORT
      LAYER M4 ;
        RECT  64.716 25.584 64.8 25.608 ;
    END
  END response_data[184]
  PIN response_data[185]
    DIRECTION OUTPUT ;
    USE SIGNAL ;
    PORT
      LAYER M4 ;
        RECT  64.716 25.68 64.8 25.704 ;
    END
  END response_data[185]
  PIN response_data[186]
    DIRECTION OUTPUT ;
    USE SIGNAL ;
    PORT
      LAYER M4 ;
        RECT  64.716 25.776 64.8 25.8 ;
    END
  END response_data[186]
  PIN response_data[187]
    DIRECTION OUTPUT ;
    USE SIGNAL ;
    PORT
      LAYER M4 ;
        RECT  64.716 25.872 64.8 25.896 ;
    END
  END response_data[187]
  PIN response_data[188]
    DIRECTION OUTPUT ;
    USE SIGNAL ;
    PORT
      LAYER M4 ;
        RECT  64.716 25.968 64.8 25.992 ;
    END
  END response_data[188]
  PIN response_data[189]
    DIRECTION OUTPUT ;
    USE SIGNAL ;
    PORT
      LAYER M4 ;
        RECT  64.716 26.064 64.8 26.088 ;
    END
  END response_data[189]
  PIN response_data[18]
    DIRECTION OUTPUT ;
    USE SIGNAL ;
    PORT
      LAYER M4 ;
        RECT  64.716 34.224 64.8 34.248 ;
    END
  END response_data[18]
  PIN response_data[190]
    DIRECTION OUTPUT ;
    USE SIGNAL ;
    PORT
      LAYER M4 ;
        RECT  64.716 26.16 64.8 26.184 ;
    END
  END response_data[190]
  PIN response_data[191]
    DIRECTION OUTPUT ;
    USE SIGNAL ;
    PORT
      LAYER M4 ;
        RECT  64.716 26.256 64.8 26.28 ;
    END
  END response_data[191]
  PIN response_data[192]
    DIRECTION OUTPUT ;
    USE SIGNAL ;
    PORT
      LAYER M4 ;
        RECT  64.716 16.368 64.8 16.392 ;
    END
  END response_data[192]
  PIN response_data[193]
    DIRECTION OUTPUT ;
    USE SIGNAL ;
    PORT
      LAYER M4 ;
        RECT  64.716 16.464 64.8 16.488 ;
    END
  END response_data[193]
  PIN response_data[194]
    DIRECTION OUTPUT ;
    USE SIGNAL ;
    PORT
      LAYER M4 ;
        RECT  64.716 16.56 64.8 16.584 ;
    END
  END response_data[194]
  PIN response_data[195]
    DIRECTION OUTPUT ;
    USE SIGNAL ;
    PORT
      LAYER M4 ;
        RECT  64.716 16.656 64.8 16.68 ;
    END
  END response_data[195]
  PIN response_data[196]
    DIRECTION OUTPUT ;
    USE SIGNAL ;
    PORT
      LAYER M4 ;
        RECT  64.716 16.752 64.8 16.776 ;
    END
  END response_data[196]
  PIN response_data[197]
    DIRECTION OUTPUT ;
    USE SIGNAL ;
    PORT
      LAYER M4 ;
        RECT  64.716 16.848 64.8 16.872 ;
    END
  END response_data[197]
  PIN response_data[198]
    DIRECTION OUTPUT ;
    USE SIGNAL ;
    PORT
      LAYER M4 ;
        RECT  64.716 16.944 64.8 16.968 ;
    END
  END response_data[198]
  PIN response_data[199]
    DIRECTION OUTPUT ;
    USE SIGNAL ;
    PORT
      LAYER M4 ;
        RECT  64.716 17.04 64.8 17.064 ;
    END
  END response_data[199]
  PIN response_data[19]
    DIRECTION OUTPUT ;
    USE SIGNAL ;
    PORT
      LAYER M4 ;
        RECT  64.716 34.32 64.8 34.344 ;
    END
  END response_data[19]
  PIN response_data[1]
    DIRECTION OUTPUT ;
    USE SIGNAL ;
    PORT
      LAYER M4 ;
        RECT  64.716 32.592 64.8 32.616 ;
    END
  END response_data[1]
  PIN response_data[200]
    DIRECTION OUTPUT ;
    USE SIGNAL ;
    PORT
      LAYER M4 ;
        RECT  64.716 17.136 64.8 17.16 ;
    END
  END response_data[200]
  PIN response_data[201]
    DIRECTION OUTPUT ;
    USE SIGNAL ;
    PORT
      LAYER M4 ;
        RECT  64.716 17.232 64.8 17.256 ;
    END
  END response_data[201]
  PIN response_data[202]
    DIRECTION OUTPUT ;
    USE SIGNAL ;
    PORT
      LAYER M4 ;
        RECT  64.716 17.328 64.8 17.352 ;
    END
  END response_data[202]
  PIN response_data[203]
    DIRECTION OUTPUT ;
    USE SIGNAL ;
    PORT
      LAYER M4 ;
        RECT  64.716 17.424 64.8 17.448 ;
    END
  END response_data[203]
  PIN response_data[204]
    DIRECTION OUTPUT ;
    USE SIGNAL ;
    PORT
      LAYER M4 ;
        RECT  64.716 17.52 64.8 17.544 ;
    END
  END response_data[204]
  PIN response_data[205]
    DIRECTION OUTPUT ;
    USE SIGNAL ;
    PORT
      LAYER M4 ;
        RECT  64.716 17.616 64.8 17.64 ;
    END
  END response_data[205]
  PIN response_data[206]
    DIRECTION OUTPUT ;
    USE SIGNAL ;
    PORT
      LAYER M4 ;
        RECT  64.716 17.712 64.8 17.736 ;
    END
  END response_data[206]
  PIN response_data[207]
    DIRECTION OUTPUT ;
    USE SIGNAL ;
    PORT
      LAYER M4 ;
        RECT  64.716 17.808 64.8 17.832 ;
    END
  END response_data[207]
  PIN response_data[208]
    DIRECTION OUTPUT ;
    USE SIGNAL ;
    PORT
      LAYER M4 ;
        RECT  64.716 17.904 64.8 17.928 ;
    END
  END response_data[208]
  PIN response_data[209]
    DIRECTION OUTPUT ;
    USE SIGNAL ;
    PORT
      LAYER M4 ;
        RECT  64.716 18 64.8 18.024 ;
    END
  END response_data[209]
  PIN response_data[20]
    DIRECTION OUTPUT ;
    USE SIGNAL ;
    PORT
      LAYER M4 ;
        RECT  64.716 34.416 64.8 34.44 ;
    END
  END response_data[20]
  PIN response_data[210]
    DIRECTION OUTPUT ;
    USE SIGNAL ;
    PORT
      LAYER M4 ;
        RECT  64.716 18.096 64.8 18.12 ;
    END
  END response_data[210]
  PIN response_data[211]
    DIRECTION OUTPUT ;
    USE SIGNAL ;
    PORT
      LAYER M4 ;
        RECT  64.716 18.192 64.8 18.216 ;
    END
  END response_data[211]
  PIN response_data[212]
    DIRECTION OUTPUT ;
    USE SIGNAL ;
    PORT
      LAYER M4 ;
        RECT  64.716 18.288 64.8 18.312 ;
    END
  END response_data[212]
  PIN response_data[213]
    DIRECTION OUTPUT ;
    USE SIGNAL ;
    PORT
      LAYER M4 ;
        RECT  64.716 18.384 64.8 18.408 ;
    END
  END response_data[213]
  PIN response_data[214]
    DIRECTION OUTPUT ;
    USE SIGNAL ;
    PORT
      LAYER M4 ;
        RECT  64.716 18.48 64.8 18.504 ;
    END
  END response_data[214]
  PIN response_data[215]
    DIRECTION OUTPUT ;
    USE SIGNAL ;
    PORT
      LAYER M4 ;
        RECT  64.716 18.576 64.8 18.6 ;
    END
  END response_data[215]
  PIN response_data[216]
    DIRECTION OUTPUT ;
    USE SIGNAL ;
    PORT
      LAYER M4 ;
        RECT  64.716 18.672 64.8 18.696 ;
    END
  END response_data[216]
  PIN response_data[217]
    DIRECTION OUTPUT ;
    USE SIGNAL ;
    PORT
      LAYER M4 ;
        RECT  64.716 18.768 64.8 18.792 ;
    END
  END response_data[217]
  PIN response_data[218]
    DIRECTION OUTPUT ;
    USE SIGNAL ;
    PORT
      LAYER M4 ;
        RECT  64.716 18.864 64.8 18.888 ;
    END
  END response_data[218]
  PIN response_data[219]
    DIRECTION OUTPUT ;
    USE SIGNAL ;
    PORT
      LAYER M4 ;
        RECT  64.716 18.96 64.8 18.984 ;
    END
  END response_data[219]
  PIN response_data[21]
    DIRECTION OUTPUT ;
    USE SIGNAL ;
    PORT
      LAYER M4 ;
        RECT  64.716 34.512 64.8 34.536 ;
    END
  END response_data[21]
  PIN response_data[220]
    DIRECTION OUTPUT ;
    USE SIGNAL ;
    PORT
      LAYER M4 ;
        RECT  64.716 19.056 64.8 19.08 ;
    END
  END response_data[220]
  PIN response_data[221]
    DIRECTION OUTPUT ;
    USE SIGNAL ;
    PORT
      LAYER M4 ;
        RECT  64.716 19.152 64.8 19.176 ;
    END
  END response_data[221]
  PIN response_data[222]
    DIRECTION OUTPUT ;
    USE SIGNAL ;
    PORT
      LAYER M4 ;
        RECT  64.716 19.248 64.8 19.272 ;
    END
  END response_data[222]
  PIN response_data[223]
    DIRECTION OUTPUT ;
    USE SIGNAL ;
    PORT
      LAYER M4 ;
        RECT  64.716 19.344 64.8 19.368 ;
    END
  END response_data[223]
  PIN response_data[224]
    DIRECTION OUTPUT ;
    USE SIGNAL ;
    PORT
      LAYER M4 ;
        RECT  64.716 13.296 64.8 13.32 ;
    END
  END response_data[224]
  PIN response_data[225]
    DIRECTION OUTPUT ;
    USE SIGNAL ;
    PORT
      LAYER M4 ;
        RECT  64.716 13.392 64.8 13.416 ;
    END
  END response_data[225]
  PIN response_data[226]
    DIRECTION OUTPUT ;
    USE SIGNAL ;
    PORT
      LAYER M4 ;
        RECT  64.716 13.488 64.8 13.512 ;
    END
  END response_data[226]
  PIN response_data[227]
    DIRECTION OUTPUT ;
    USE SIGNAL ;
    PORT
      LAYER M4 ;
        RECT  64.716 13.584 64.8 13.608 ;
    END
  END response_data[227]
  PIN response_data[228]
    DIRECTION OUTPUT ;
    USE SIGNAL ;
    PORT
      LAYER M4 ;
        RECT  64.716 13.68 64.8 13.704 ;
    END
  END response_data[228]
  PIN response_data[229]
    DIRECTION OUTPUT ;
    USE SIGNAL ;
    PORT
      LAYER M4 ;
        RECT  64.716 13.776 64.8 13.8 ;
    END
  END response_data[229]
  PIN response_data[22]
    DIRECTION OUTPUT ;
    USE SIGNAL ;
    PORT
      LAYER M4 ;
        RECT  64.716 34.608 64.8 34.632 ;
    END
  END response_data[22]
  PIN response_data[230]
    DIRECTION OUTPUT ;
    USE SIGNAL ;
    PORT
      LAYER M4 ;
        RECT  64.716 13.872 64.8 13.896 ;
    END
  END response_data[230]
  PIN response_data[231]
    DIRECTION OUTPUT ;
    USE SIGNAL ;
    PORT
      LAYER M4 ;
        RECT  64.716 13.968 64.8 13.992 ;
    END
  END response_data[231]
  PIN response_data[232]
    DIRECTION OUTPUT ;
    USE SIGNAL ;
    PORT
      LAYER M4 ;
        RECT  64.716 14.064 64.8 14.088 ;
    END
  END response_data[232]
  PIN response_data[233]
    DIRECTION OUTPUT ;
    USE SIGNAL ;
    PORT
      LAYER M4 ;
        RECT  64.716 14.16 64.8 14.184 ;
    END
  END response_data[233]
  PIN response_data[234]
    DIRECTION OUTPUT ;
    USE SIGNAL ;
    PORT
      LAYER M4 ;
        RECT  64.716 14.256 64.8 14.28 ;
    END
  END response_data[234]
  PIN response_data[235]
    DIRECTION OUTPUT ;
    USE SIGNAL ;
    PORT
      LAYER M4 ;
        RECT  64.716 14.352 64.8 14.376 ;
    END
  END response_data[235]
  PIN response_data[236]
    DIRECTION OUTPUT ;
    USE SIGNAL ;
    PORT
      LAYER M4 ;
        RECT  64.716 14.448 64.8 14.472 ;
    END
  END response_data[236]
  PIN response_data[237]
    DIRECTION OUTPUT ;
    USE SIGNAL ;
    PORT
      LAYER M4 ;
        RECT  64.716 14.544 64.8 14.568 ;
    END
  END response_data[237]
  PIN response_data[238]
    DIRECTION OUTPUT ;
    USE SIGNAL ;
    PORT
      LAYER M4 ;
        RECT  64.716 14.64 64.8 14.664 ;
    END
  END response_data[238]
  PIN response_data[239]
    DIRECTION OUTPUT ;
    USE SIGNAL ;
    PORT
      LAYER M4 ;
        RECT  64.716 14.736 64.8 14.76 ;
    END
  END response_data[239]
  PIN response_data[23]
    DIRECTION OUTPUT ;
    USE SIGNAL ;
    PORT
      LAYER M4 ;
        RECT  64.716 34.704 64.8 34.728 ;
    END
  END response_data[23]
  PIN response_data[240]
    DIRECTION OUTPUT ;
    USE SIGNAL ;
    PORT
      LAYER M4 ;
        RECT  64.716 14.832 64.8 14.856 ;
    END
  END response_data[240]
  PIN response_data[241]
    DIRECTION OUTPUT ;
    USE SIGNAL ;
    PORT
      LAYER M4 ;
        RECT  64.716 14.928 64.8 14.952 ;
    END
  END response_data[241]
  PIN response_data[242]
    DIRECTION OUTPUT ;
    USE SIGNAL ;
    PORT
      LAYER M4 ;
        RECT  64.716 15.024 64.8 15.048 ;
    END
  END response_data[242]
  PIN response_data[243]
    DIRECTION OUTPUT ;
    USE SIGNAL ;
    PORT
      LAYER M4 ;
        RECT  64.716 15.12 64.8 15.144 ;
    END
  END response_data[243]
  PIN response_data[244]
    DIRECTION OUTPUT ;
    USE SIGNAL ;
    PORT
      LAYER M4 ;
        RECT  64.716 15.216 64.8 15.24 ;
    END
  END response_data[244]
  PIN response_data[245]
    DIRECTION OUTPUT ;
    USE SIGNAL ;
    PORT
      LAYER M4 ;
        RECT  64.716 15.312 64.8 15.336 ;
    END
  END response_data[245]
  PIN response_data[246]
    DIRECTION OUTPUT ;
    USE SIGNAL ;
    PORT
      LAYER M4 ;
        RECT  64.716 15.408 64.8 15.432 ;
    END
  END response_data[246]
  PIN response_data[247]
    DIRECTION OUTPUT ;
    USE SIGNAL ;
    PORT
      LAYER M4 ;
        RECT  64.716 15.504 64.8 15.528 ;
    END
  END response_data[247]
  PIN response_data[248]
    DIRECTION OUTPUT ;
    USE SIGNAL ;
    PORT
      LAYER M4 ;
        RECT  64.716 15.6 64.8 15.624 ;
    END
  END response_data[248]
  PIN response_data[249]
    DIRECTION OUTPUT ;
    USE SIGNAL ;
    PORT
      LAYER M4 ;
        RECT  64.716 15.696 64.8 15.72 ;
    END
  END response_data[249]
  PIN response_data[24]
    DIRECTION OUTPUT ;
    USE SIGNAL ;
    PORT
      LAYER M4 ;
        RECT  64.716 34.8 64.8 34.824 ;
    END
  END response_data[24]
  PIN response_data[250]
    DIRECTION OUTPUT ;
    USE SIGNAL ;
    PORT
      LAYER M4 ;
        RECT  64.716 15.792 64.8 15.816 ;
    END
  END response_data[250]
  PIN response_data[251]
    DIRECTION OUTPUT ;
    USE SIGNAL ;
    PORT
      LAYER M4 ;
        RECT  64.716 15.888 64.8 15.912 ;
    END
  END response_data[251]
  PIN response_data[252]
    DIRECTION OUTPUT ;
    USE SIGNAL ;
    PORT
      LAYER M4 ;
        RECT  64.716 15.984 64.8 16.008 ;
    END
  END response_data[252]
  PIN response_data[253]
    DIRECTION OUTPUT ;
    USE SIGNAL ;
    PORT
      LAYER M4 ;
        RECT  64.716 16.08 64.8 16.104 ;
    END
  END response_data[253]
  PIN response_data[254]
    DIRECTION OUTPUT ;
    USE SIGNAL ;
    PORT
      LAYER M4 ;
        RECT  64.716 16.176 64.8 16.2 ;
    END
  END response_data[254]
  PIN response_data[255]
    DIRECTION OUTPUT ;
    USE SIGNAL ;
    PORT
      LAYER M4 ;
        RECT  64.716 16.272 64.8 16.296 ;
    END
  END response_data[255]
  PIN response_data[25]
    DIRECTION OUTPUT ;
    USE SIGNAL ;
    PORT
      LAYER M4 ;
        RECT  64.716 34.896 64.8 34.92 ;
    END
  END response_data[25]
  PIN response_data[26]
    DIRECTION OUTPUT ;
    USE SIGNAL ;
    PORT
      LAYER M4 ;
        RECT  64.716 34.992 64.8 35.016 ;
    END
  END response_data[26]
  PIN response_data[27]
    DIRECTION OUTPUT ;
    USE SIGNAL ;
    PORT
      LAYER M4 ;
        RECT  64.716 35.088 64.8 35.112 ;
    END
  END response_data[27]
  PIN response_data[28]
    DIRECTION OUTPUT ;
    USE SIGNAL ;
    PORT
      LAYER M4 ;
        RECT  64.716 35.184 64.8 35.208 ;
    END
  END response_data[28]
  PIN response_data[29]
    DIRECTION OUTPUT ;
    USE SIGNAL ;
    PORT
      LAYER M4 ;
        RECT  64.716 35.28 64.8 35.304 ;
    END
  END response_data[29]
  PIN response_data[2]
    DIRECTION OUTPUT ;
    USE SIGNAL ;
    PORT
      LAYER M4 ;
        RECT  64.716 32.688 64.8 32.712 ;
    END
  END response_data[2]
  PIN response_data[30]
    DIRECTION OUTPUT ;
    USE SIGNAL ;
    PORT
      LAYER M4 ;
        RECT  64.716 35.376 64.8 35.4 ;
    END
  END response_data[30]
  PIN response_data[31]
    DIRECTION OUTPUT ;
    USE SIGNAL ;
    PORT
      LAYER M4 ;
        RECT  64.716 35.472 64.8 35.496 ;
    END
  END response_data[31]
  PIN response_data[32]
    DIRECTION OUTPUT ;
    USE SIGNAL ;
    PORT
      LAYER M4 ;
        RECT  64.716 20.208 64.8 20.232 ;
    END
  END response_data[32]
  PIN response_data[33]
    DIRECTION OUTPUT ;
    USE SIGNAL ;
    PORT
      LAYER M4 ;
        RECT  64.716 20.304 64.8 20.328 ;
    END
  END response_data[33]
  PIN response_data[34]
    DIRECTION OUTPUT ;
    USE SIGNAL ;
    PORT
      LAYER M4 ;
        RECT  64.716 20.4 64.8 20.424 ;
    END
  END response_data[34]
  PIN response_data[35]
    DIRECTION OUTPUT ;
    USE SIGNAL ;
    PORT
      LAYER M4 ;
        RECT  64.716 20.496 64.8 20.52 ;
    END
  END response_data[35]
  PIN response_data[36]
    DIRECTION OUTPUT ;
    USE SIGNAL ;
    PORT
      LAYER M4 ;
        RECT  64.716 20.592 64.8 20.616 ;
    END
  END response_data[36]
  PIN response_data[37]
    DIRECTION OUTPUT ;
    USE SIGNAL ;
    PORT
      LAYER M4 ;
        RECT  64.716 20.688 64.8 20.712 ;
    END
  END response_data[37]
  PIN response_data[38]
    DIRECTION OUTPUT ;
    USE SIGNAL ;
    PORT
      LAYER M4 ;
        RECT  64.716 20.784 64.8 20.808 ;
    END
  END response_data[38]
  PIN response_data[39]
    DIRECTION OUTPUT ;
    USE SIGNAL ;
    PORT
      LAYER M4 ;
        RECT  64.716 20.88 64.8 20.904 ;
    END
  END response_data[39]
  PIN response_data[3]
    DIRECTION OUTPUT ;
    USE SIGNAL ;
    PORT
      LAYER M4 ;
        RECT  64.716 32.784 64.8 32.808 ;
    END
  END response_data[3]
  PIN response_data[40]
    DIRECTION OUTPUT ;
    USE SIGNAL ;
    PORT
      LAYER M4 ;
        RECT  64.716 20.976 64.8 21 ;
    END
  END response_data[40]
  PIN response_data[41]
    DIRECTION OUTPUT ;
    USE SIGNAL ;
    PORT
      LAYER M4 ;
        RECT  64.716 21.072 64.8 21.096 ;
    END
  END response_data[41]
  PIN response_data[42]
    DIRECTION OUTPUT ;
    USE SIGNAL ;
    PORT
      LAYER M4 ;
        RECT  64.716 21.168 64.8 21.192 ;
    END
  END response_data[42]
  PIN response_data[43]
    DIRECTION OUTPUT ;
    USE SIGNAL ;
    PORT
      LAYER M4 ;
        RECT  64.716 21.264 64.8 21.288 ;
    END
  END response_data[43]
  PIN response_data[44]
    DIRECTION OUTPUT ;
    USE SIGNAL ;
    PORT
      LAYER M4 ;
        RECT  64.716 21.36 64.8 21.384 ;
    END
  END response_data[44]
  PIN response_data[45]
    DIRECTION OUTPUT ;
    USE SIGNAL ;
    PORT
      LAYER M4 ;
        RECT  64.716 21.456 64.8 21.48 ;
    END
  END response_data[45]
  PIN response_data[46]
    DIRECTION OUTPUT ;
    USE SIGNAL ;
    PORT
      LAYER M4 ;
        RECT  64.716 21.552 64.8 21.576 ;
    END
  END response_data[46]
  PIN response_data[47]
    DIRECTION OUTPUT ;
    USE SIGNAL ;
    PORT
      LAYER M4 ;
        RECT  64.716 21.648 64.8 21.672 ;
    END
  END response_data[47]
  PIN response_data[48]
    DIRECTION OUTPUT ;
    USE SIGNAL ;
    PORT
      LAYER M4 ;
        RECT  64.716 21.744 64.8 21.768 ;
    END
  END response_data[48]
  PIN response_data[49]
    DIRECTION OUTPUT ;
    USE SIGNAL ;
    PORT
      LAYER M4 ;
        RECT  64.716 21.84 64.8 21.864 ;
    END
  END response_data[49]
  PIN response_data[4]
    DIRECTION OUTPUT ;
    USE SIGNAL ;
    PORT
      LAYER M4 ;
        RECT  64.716 32.88 64.8 32.904 ;
    END
  END response_data[4]
  PIN response_data[50]
    DIRECTION OUTPUT ;
    USE SIGNAL ;
    PORT
      LAYER M4 ;
        RECT  64.716 21.936 64.8 21.96 ;
    END
  END response_data[50]
  PIN response_data[51]
    DIRECTION OUTPUT ;
    USE SIGNAL ;
    PORT
      LAYER M4 ;
        RECT  64.716 22.032 64.8 22.056 ;
    END
  END response_data[51]
  PIN response_data[52]
    DIRECTION OUTPUT ;
    USE SIGNAL ;
    PORT
      LAYER M4 ;
        RECT  64.716 22.128 64.8 22.152 ;
    END
  END response_data[52]
  PIN response_data[53]
    DIRECTION OUTPUT ;
    USE SIGNAL ;
    PORT
      LAYER M4 ;
        RECT  64.716 22.224 64.8 22.248 ;
    END
  END response_data[53]
  PIN response_data[54]
    DIRECTION OUTPUT ;
    USE SIGNAL ;
    PORT
      LAYER M4 ;
        RECT  64.716 22.32 64.8 22.344 ;
    END
  END response_data[54]
  PIN response_data[55]
    DIRECTION OUTPUT ;
    USE SIGNAL ;
    PORT
      LAYER M4 ;
        RECT  64.716 22.416 64.8 22.44 ;
    END
  END response_data[55]
  PIN response_data[56]
    DIRECTION OUTPUT ;
    USE SIGNAL ;
    PORT
      LAYER M4 ;
        RECT  64.716 22.512 64.8 22.536 ;
    END
  END response_data[56]
  PIN response_data[57]
    DIRECTION OUTPUT ;
    USE SIGNAL ;
    PORT
      LAYER M4 ;
        RECT  64.716 22.608 64.8 22.632 ;
    END
  END response_data[57]
  PIN response_data[58]
    DIRECTION OUTPUT ;
    USE SIGNAL ;
    PORT
      LAYER M4 ;
        RECT  64.716 22.704 64.8 22.728 ;
    END
  END response_data[58]
  PIN response_data[59]
    DIRECTION OUTPUT ;
    USE SIGNAL ;
    PORT
      LAYER M4 ;
        RECT  64.716 22.8 64.8 22.824 ;
    END
  END response_data[59]
  PIN response_data[5]
    DIRECTION OUTPUT ;
    USE SIGNAL ;
    PORT
      LAYER M4 ;
        RECT  64.716 32.976 64.8 33 ;
    END
  END response_data[5]
  PIN response_data[60]
    DIRECTION OUTPUT ;
    USE SIGNAL ;
    PORT
      LAYER M4 ;
        RECT  64.716 22.896 64.8 22.92 ;
    END
  END response_data[60]
  PIN response_data[61]
    DIRECTION OUTPUT ;
    USE SIGNAL ;
    PORT
      LAYER M4 ;
        RECT  64.716 22.992 64.8 23.016 ;
    END
  END response_data[61]
  PIN response_data[62]
    DIRECTION OUTPUT ;
    USE SIGNAL ;
    PORT
      LAYER M4 ;
        RECT  64.716 23.088 64.8 23.112 ;
    END
  END response_data[62]
  PIN response_data[63]
    DIRECTION OUTPUT ;
    USE SIGNAL ;
    PORT
      LAYER M4 ;
        RECT  64.716 23.184 64.8 23.208 ;
    END
  END response_data[63]
  PIN response_data[64]
    DIRECTION OUTPUT ;
    USE SIGNAL ;
    PORT
      LAYER M4 ;
        RECT  64.716 29.424 64.8 29.448 ;
    END
  END response_data[64]
  PIN response_data[65]
    DIRECTION OUTPUT ;
    USE SIGNAL ;
    PORT
      LAYER M4 ;
        RECT  64.716 29.52 64.8 29.544 ;
    END
  END response_data[65]
  PIN response_data[66]
    DIRECTION OUTPUT ;
    USE SIGNAL ;
    PORT
      LAYER M4 ;
        RECT  64.716 29.616 64.8 29.64 ;
    END
  END response_data[66]
  PIN response_data[67]
    DIRECTION OUTPUT ;
    USE SIGNAL ;
    PORT
      LAYER M4 ;
        RECT  64.716 29.712 64.8 29.736 ;
    END
  END response_data[67]
  PIN response_data[68]
    DIRECTION OUTPUT ;
    USE SIGNAL ;
    PORT
      LAYER M4 ;
        RECT  64.716 29.808 64.8 29.832 ;
    END
  END response_data[68]
  PIN response_data[69]
    DIRECTION OUTPUT ;
    USE SIGNAL ;
    PORT
      LAYER M4 ;
        RECT  64.716 29.904 64.8 29.928 ;
    END
  END response_data[69]
  PIN response_data[6]
    DIRECTION OUTPUT ;
    USE SIGNAL ;
    PORT
      LAYER M4 ;
        RECT  64.716 33.072 64.8 33.096 ;
    END
  END response_data[6]
  PIN response_data[70]
    DIRECTION OUTPUT ;
    USE SIGNAL ;
    PORT
      LAYER M4 ;
        RECT  64.716 30 64.8 30.024 ;
    END
  END response_data[70]
  PIN response_data[71]
    DIRECTION OUTPUT ;
    USE SIGNAL ;
    PORT
      LAYER M4 ;
        RECT  64.716 30.096 64.8 30.12 ;
    END
  END response_data[71]
  PIN response_data[72]
    DIRECTION OUTPUT ;
    USE SIGNAL ;
    PORT
      LAYER M4 ;
        RECT  64.716 30.192 64.8 30.216 ;
    END
  END response_data[72]
  PIN response_data[73]
    DIRECTION OUTPUT ;
    USE SIGNAL ;
    PORT
      LAYER M4 ;
        RECT  64.716 30.288 64.8 30.312 ;
    END
  END response_data[73]
  PIN response_data[74]
    DIRECTION OUTPUT ;
    USE SIGNAL ;
    PORT
      LAYER M4 ;
        RECT  64.716 30.384 64.8 30.408 ;
    END
  END response_data[74]
  PIN response_data[75]
    DIRECTION OUTPUT ;
    USE SIGNAL ;
    PORT
      LAYER M4 ;
        RECT  64.716 30.48 64.8 30.504 ;
    END
  END response_data[75]
  PIN response_data[76]
    DIRECTION OUTPUT ;
    USE SIGNAL ;
    PORT
      LAYER M4 ;
        RECT  64.716 30.576 64.8 30.6 ;
    END
  END response_data[76]
  PIN response_data[77]
    DIRECTION OUTPUT ;
    USE SIGNAL ;
    PORT
      LAYER M4 ;
        RECT  64.716 30.672 64.8 30.696 ;
    END
  END response_data[77]
  PIN response_data[78]
    DIRECTION OUTPUT ;
    USE SIGNAL ;
    PORT
      LAYER M4 ;
        RECT  64.716 30.768 64.8 30.792 ;
    END
  END response_data[78]
  PIN response_data[79]
    DIRECTION OUTPUT ;
    USE SIGNAL ;
    PORT
      LAYER M4 ;
        RECT  64.716 30.864 64.8 30.888 ;
    END
  END response_data[79]
  PIN response_data[7]
    DIRECTION OUTPUT ;
    USE SIGNAL ;
    PORT
      LAYER M4 ;
        RECT  64.716 33.168 64.8 33.192 ;
    END
  END response_data[7]
  PIN response_data[80]
    DIRECTION OUTPUT ;
    USE SIGNAL ;
    PORT
      LAYER M4 ;
        RECT  64.716 30.96 64.8 30.984 ;
    END
  END response_data[80]
  PIN response_data[81]
    DIRECTION OUTPUT ;
    USE SIGNAL ;
    PORT
      LAYER M4 ;
        RECT  64.716 31.056 64.8 31.08 ;
    END
  END response_data[81]
  PIN response_data[82]
    DIRECTION OUTPUT ;
    USE SIGNAL ;
    PORT
      LAYER M4 ;
        RECT  64.716 31.152 64.8 31.176 ;
    END
  END response_data[82]
  PIN response_data[83]
    DIRECTION OUTPUT ;
    USE SIGNAL ;
    PORT
      LAYER M4 ;
        RECT  64.716 31.248 64.8 31.272 ;
    END
  END response_data[83]
  PIN response_data[84]
    DIRECTION OUTPUT ;
    USE SIGNAL ;
    PORT
      LAYER M4 ;
        RECT  64.716 31.344 64.8 31.368 ;
    END
  END response_data[84]
  PIN response_data[85]
    DIRECTION OUTPUT ;
    USE SIGNAL ;
    PORT
      LAYER M4 ;
        RECT  64.716 31.44 64.8 31.464 ;
    END
  END response_data[85]
  PIN response_data[86]
    DIRECTION OUTPUT ;
    USE SIGNAL ;
    PORT
      LAYER M4 ;
        RECT  64.716 31.536 64.8 31.56 ;
    END
  END response_data[86]
  PIN response_data[87]
    DIRECTION OUTPUT ;
    USE SIGNAL ;
    PORT
      LAYER M4 ;
        RECT  64.716 31.632 64.8 31.656 ;
    END
  END response_data[87]
  PIN response_data[88]
    DIRECTION OUTPUT ;
    USE SIGNAL ;
    PORT
      LAYER M4 ;
        RECT  64.716 31.728 64.8 31.752 ;
    END
  END response_data[88]
  PIN response_data[89]
    DIRECTION OUTPUT ;
    USE SIGNAL ;
    PORT
      LAYER M4 ;
        RECT  64.716 31.824 64.8 31.848 ;
    END
  END response_data[89]
  PIN response_data[8]
    DIRECTION OUTPUT ;
    USE SIGNAL ;
    PORT
      LAYER M4 ;
        RECT  64.716 33.264 64.8 33.288 ;
    END
  END response_data[8]
  PIN response_data[90]
    DIRECTION OUTPUT ;
    USE SIGNAL ;
    PORT
      LAYER M4 ;
        RECT  64.716 31.92 64.8 31.944 ;
    END
  END response_data[90]
  PIN response_data[91]
    DIRECTION OUTPUT ;
    USE SIGNAL ;
    PORT
      LAYER M4 ;
        RECT  64.716 32.016 64.8 32.04 ;
    END
  END response_data[91]
  PIN response_data[92]
    DIRECTION OUTPUT ;
    USE SIGNAL ;
    PORT
      LAYER M4 ;
        RECT  64.716 32.112 64.8 32.136 ;
    END
  END response_data[92]
  PIN response_data[93]
    DIRECTION OUTPUT ;
    USE SIGNAL ;
    PORT
      LAYER M4 ;
        RECT  64.716 32.208 64.8 32.232 ;
    END
  END response_data[93]
  PIN response_data[94]
    DIRECTION OUTPUT ;
    USE SIGNAL ;
    PORT
      LAYER M4 ;
        RECT  64.716 32.304 64.8 32.328 ;
    END
  END response_data[94]
  PIN response_data[95]
    DIRECTION OUTPUT ;
    USE SIGNAL ;
    PORT
      LAYER M4 ;
        RECT  64.716 32.4 64.8 32.424 ;
    END
  END response_data[95]
  PIN response_data[96]
    DIRECTION OUTPUT ;
    USE SIGNAL ;
    PORT
      LAYER M4 ;
        RECT  64.716 35.568 64.8 35.592 ;
    END
  END response_data[96]
  PIN response_data[97]
    DIRECTION OUTPUT ;
    USE SIGNAL ;
    PORT
      LAYER M4 ;
        RECT  64.716 35.664 64.8 35.688 ;
    END
  END response_data[97]
  PIN response_data[98]
    DIRECTION OUTPUT ;
    USE SIGNAL ;
    PORT
      LAYER M4 ;
        RECT  64.716 35.76 64.8 35.784 ;
    END
  END response_data[98]
  PIN response_data[99]
    DIRECTION OUTPUT ;
    USE SIGNAL ;
    PORT
      LAYER M4 ;
        RECT  64.716 35.856 64.8 35.88 ;
    END
  END response_data[99]
  PIN response_data[9]
    DIRECTION OUTPUT ;
    USE SIGNAL ;
    PORT
      LAYER M4 ;
        RECT  64.716 33.36 64.8 33.384 ;
    END
  END response_data[9]
  PIN response_v[0]
    DIRECTION OUTPUT ;
    USE SIGNAL ;
    PORT
      LAYER M4 ;
        RECT  0 23.856 0.084 23.88 ;
    END
  END response_v[0]
  PIN response_v[1]
    DIRECTION OUTPUT ;
    USE SIGNAL ;
    PORT
      LAYER M4 ;
        RECT  0 23.952 0.084 23.976 ;
    END
  END response_v[1]
  PIN response_v[2]
    DIRECTION OUTPUT ;
    USE SIGNAL ;
    PORT
      LAYER M4 ;
        RECT  0 24.048 0.084 24.072 ;
    END
  END response_v[2]
  PIN response_v[3]
    DIRECTION OUTPUT ;
    USE SIGNAL ;
    PORT
      LAYER M4 ;
        RECT  0 24.144 0.084 24.168 ;
    END
  END response_v[3]
  PIN rst_n
    DIRECTION INPUT ;
    USE SIGNAL ;
    PORT
      LAYER M4 ;
        RECT  0 22.608 0.084 22.632 ;
    END
  END rst_n
  PIN VDD
    DIRECTION INOUT ;
    USE POWER ;
    PORT
      LAYER M5 ;
        RECT  61.992 2.151 62.112 41.049 ;
        RECT  56.592 2.151 56.712 41.049 ;
        RECT  51.192 2.151 51.312 41.049 ;
        RECT  45.792 2.151 45.912 41.049 ;
        RECT  40.392 2.151 40.512 41.049 ;
        RECT  34.992 2.151 35.112 41.049 ;
        RECT  29.592 2.151 29.712 41.049 ;
        RECT  24.192 2.151 24.312 41.049 ;
        RECT  18.792 2.151 18.912 41.049 ;
        RECT  13.392 2.151 13.512 41.049 ;
        RECT  7.992 2.151 8.112 41.049 ;
        RECT  2.592 2.151 2.712 41.049 ;
    END
  END VDD
  PIN VSS
    DIRECTION INOUT ;
    USE GROUND ;
    PORT
      LAYER M5 ;
        RECT  61.8 2.137 61.92 41.063 ;
        RECT  56.4 2.137 56.52 41.063 ;
        RECT  51 2.137 51.12 41.063 ;
        RECT  45.6 2.137 45.72 41.063 ;
        RECT  40.2 2.137 40.32 41.063 ;
        RECT  34.8 2.137 34.92 41.063 ;
        RECT  29.4 2.137 29.52 41.063 ;
        RECT  24 2.137 24.12 41.063 ;
        RECT  18.6 2.137 18.72 41.063 ;
        RECT  13.2 2.137 13.32 41.063 ;
        RECT  7.8 2.137 7.92 41.063 ;
        RECT  2.4 2.137 2.52 41.063 ;
    END
  END VSS
  # OT_OBS_CLOSED layer=M5 d_um=1.536 added=57
  OBS
    LAYER RVTN ;
     RECT  2.16 2.16 62.64 2.295 ;
     RECT  2.16 2.565 62.64 2.835 ;
     RECT  2.16 3.105 62.64 3.375 ;
     RECT  2.16 3.645 62.64 3.915 ;
     RECT  2.16 4.185 62.64 4.455 ;
     RECT  2.16 4.725 62.64 4.995 ;
     RECT  2.16 5.265 62.64 5.535 ;
     RECT  2.16 5.805 62.64 6.075 ;
     RECT  2.16 6.345 62.64 6.615 ;
     RECT  2.16 6.885 62.64 7.155 ;
     RECT  2.16 7.425 62.64 7.695 ;
     RECT  2.16 7.965 62.64 8.235 ;
     RECT  2.16 8.505 62.64 8.775 ;
     RECT  2.16 9.045 62.64 9.315 ;
     RECT  2.16 9.585 62.64 9.855 ;
     RECT  2.16 10.125 62.64 10.395 ;
     RECT  2.16 10.665 62.64 10.935 ;
     RECT  2.16 11.205 62.64 11.475 ;
     RECT  2.16 11.745 62.64 12.015 ;
     RECT  2.16 12.285 62.64 12.555 ;
     RECT  2.16 12.825 62.64 13.095 ;
     RECT  2.16 13.365 62.64 13.635 ;
     RECT  2.16 13.905 62.64 14.175 ;
     RECT  2.16 14.445 62.64 14.715 ;
     RECT  2.16 14.985 62.64 15.255 ;
     RECT  2.16 15.525 62.64 15.795 ;
     RECT  2.16 16.065 62.64 16.335 ;
     RECT  2.16 16.605 62.64 16.875 ;
     RECT  2.16 17.145 62.64 17.415 ;
     RECT  2.16 17.685 62.64 17.955 ;
     RECT  2.16 18.225 62.64 18.495 ;
     RECT  2.16 18.765 62.64 19.035 ;
     RECT  2.16 19.305 62.64 19.575 ;
     RECT  2.16 19.845 62.64 20.115 ;
     RECT  2.16 20.385 62.64 20.655 ;
     RECT  2.16 20.925 62.64 21.195 ;
     RECT  2.16 21.465 62.64 21.735 ;
     RECT  2.16 22.005 62.64 22.275 ;
     RECT  2.16 22.545 62.64 22.815 ;
     RECT  2.16 23.085 62.64 23.355 ;
     RECT  2.16 23.625 62.64 23.895 ;
     RECT  2.16 24.165 62.64 24.435 ;
     RECT  2.16 24.705 62.64 24.975 ;
     RECT  2.16 25.245 62.64 25.515 ;
     RECT  2.16 25.785 62.64 26.055 ;
     RECT  2.16 26.325 62.64 26.595 ;
     RECT  2.16 26.865 62.64 27.135 ;
     RECT  2.16 27.405 62.64 27.675 ;
     RECT  2.16 27.945 62.64 28.215 ;
     RECT  2.16 28.485 62.64 28.755 ;
     RECT  2.16 29.025 62.64 29.295 ;
     RECT  2.16 29.565 62.64 29.835 ;
     RECT  2.16 30.105 62.64 30.375 ;
     RECT  2.16 30.645 62.64 30.915 ;
     RECT  2.16 31.185 62.64 31.455 ;
     RECT  2.16 31.725 62.64 31.995 ;
     RECT  2.16 32.265 62.64 32.535 ;
     RECT  2.16 32.805 62.64 33.075 ;
     RECT  2.16 33.345 62.64 33.615 ;
     RECT  2.16 33.885 62.64 34.155 ;
     RECT  2.16 34.425 62.64 34.695 ;
     RECT  2.16 34.965 62.64 35.235 ;
     RECT  2.16 35.505 62.64 35.775 ;
     RECT  2.16 36.045 62.64 36.315 ;
     RECT  2.16 36.585 62.64 36.855 ;
     RECT  2.16 37.125 62.64 37.395 ;
     RECT  2.16 37.665 62.64 37.935 ;
     RECT  2.16 38.205 62.64 38.475 ;
     RECT  2.16 38.745 62.64 39.015 ;
     RECT  2.16 39.285 62.64 39.555 ;
     RECT  2.16 39.825 62.64 40.095 ;
     RECT  2.16 40.365 62.64 40.635 ;
     RECT  2.16 40.905 62.64 41.04 ;
    LAYER RVTP ;
     RECT  2.16 2.295 62.64 2.565 ;
     RECT  2.16 2.835 62.64 3.105 ;
     RECT  2.16 3.375 62.64 3.645 ;
     RECT  2.16 3.915 62.64 4.185 ;
     RECT  2.16 4.455 62.64 4.725 ;
     RECT  2.16 4.995 62.64 5.265 ;
     RECT  2.16 5.535 62.64 5.805 ;
     RECT  2.16 6.075 62.64 6.345 ;
     RECT  2.16 6.615 62.64 6.885 ;
     RECT  2.16 7.155 62.64 7.425 ;
     RECT  2.16 7.695 62.64 7.965 ;
     RECT  2.16 8.235 62.64 8.505 ;
     RECT  2.16 8.775 62.64 9.045 ;
     RECT  2.16 9.315 62.64 9.585 ;
     RECT  2.16 9.855 62.64 10.125 ;
     RECT  2.16 10.395 62.64 10.665 ;
     RECT  2.16 10.935 62.64 11.205 ;
     RECT  2.16 11.475 62.64 11.745 ;
     RECT  2.16 12.015 62.64 12.285 ;
     RECT  2.16 12.555 62.64 12.825 ;
     RECT  2.16 13.095 62.64 13.365 ;
     RECT  2.16 13.635 62.64 13.905 ;
     RECT  2.16 14.175 62.64 14.445 ;
     RECT  2.16 14.715 62.64 14.985 ;
     RECT  2.16 15.255 62.64 15.525 ;
     RECT  2.16 15.795 62.64 16.065 ;
     RECT  2.16 16.335 62.64 16.605 ;
     RECT  2.16 16.875 62.64 17.145 ;
     RECT  2.16 17.415 62.64 17.685 ;
     RECT  2.16 17.955 62.64 18.225 ;
     RECT  2.16 18.495 62.64 18.765 ;
     RECT  2.16 19.035 62.64 19.305 ;
     RECT  2.16 19.575 62.64 19.845 ;
     RECT  2.16 20.115 62.64 20.385 ;
     RECT  2.16 20.655 62.64 20.925 ;
     RECT  2.16 21.195 62.64 21.465 ;
     RECT  2.16 21.735 62.64 22.005 ;
     RECT  2.16 22.275 62.64 22.545 ;
     RECT  2.16 22.815 62.64 23.085 ;
     RECT  2.16 23.355 62.64 23.625 ;
     RECT  2.16 23.895 62.64 24.165 ;
     RECT  2.16 24.435 62.64 24.705 ;
     RECT  2.16 24.975 62.64 25.245 ;
     RECT  2.16 25.515 62.64 25.785 ;
     RECT  2.16 26.055 62.64 26.325 ;
     RECT  2.16 26.595 62.64 26.865 ;
     RECT  2.16 27.135 62.64 27.405 ;
     RECT  2.16 27.675 62.64 27.945 ;
     RECT  2.16 28.215 62.64 28.485 ;
     RECT  2.16 28.755 62.64 29.025 ;
     RECT  2.16 29.295 62.64 29.565 ;
     RECT  2.16 29.835 62.64 30.105 ;
     RECT  2.16 30.375 62.64 30.645 ;
     RECT  2.16 30.915 62.64 31.185 ;
     RECT  2.16 31.455 62.64 31.725 ;
     RECT  2.16 31.995 62.64 32.265 ;
     RECT  2.16 32.535 62.64 32.805 ;
     RECT  2.16 33.075 62.64 33.345 ;
     RECT  2.16 33.615 62.64 33.885 ;
     RECT  2.16 34.155 62.64 34.425 ;
     RECT  2.16 34.695 62.64 34.965 ;
     RECT  2.16 35.235 62.64 35.505 ;
     RECT  2.16 35.775 62.64 36.045 ;
     RECT  2.16 36.315 62.64 36.585 ;
     RECT  2.16 36.855 62.64 37.125 ;
     RECT  2.16 37.395 62.64 37.665 ;
     RECT  2.16 37.935 62.64 38.205 ;
     RECT  2.16 38.475 62.64 38.745 ;
     RECT  2.16 39.015 62.64 39.285 ;
     RECT  2.16 39.555 62.64 39.825 ;
     RECT  2.16 40.095 62.64 40.365 ;
     RECT  2.16 40.635 62.64 40.905 ;
    LAYER M1 ;
     RECT  2.16 2.151 62.64 41.049 ;
    LAYER M2 ;
     RECT  0.103 30.888 0.347 31.059 ;
     RECT  0.103 24.876 0.499 24.894 ;
     RECT  0.499 15.336 0.535 15.354 ;
     RECT  0.103 13.572 1.147 13.59 ;
     RECT  1.147 29.844 1.723 29.862 ;
     RECT  1.975 2.61 2.16 2.628 ;
     RECT  1.147 13.068 2.16 13.59 ;
     RECT  0.535 15.192 2.16 15.354 ;
     RECT  0.535 16.506 2.16 16.524 ;
     RECT  0.103 19.08 2.16 19.098 ;
     RECT  0.499 24.876 2.16 25.434 ;
     RECT  1.723 29.844 2.16 30.474 ;
     RECT  0.535 40.716 2.16 40.734 ;
     RECT  29.659 42.156 30.587 42.174 ;
     RECT  2.16 2.151 33.079 41.049 ;
     RECT  32.467 41.886 33.079 41.904 ;
     RECT  33.079 2.151 35.599 41.904 ;
     RECT  35.599 2.106 36.203 41.904 ;
     RECT  39.991 0.108 40.675 0.126 ;
     RECT  40.675 0.036 41.107 0.126 ;
     RECT  41.107 0.036 41.531 0.549 ;
     RECT  43.879 43.074 45.059 43.092 ;
     RECT  45.823 43.074 46.723 43.092 ;
     RECT  46.723 42.966 47.795 43.092 ;
     RECT  47.795 42.966 47.831 42.984 ;
     RECT  49.387 43.074 49.811 43.092 ;
     RECT  50.611 43.002 50.855 43.02 ;
     RECT  41.531 0.036 51.323 0.126 ;
     RECT  36.203 2.151 51.683 41.904 ;
     RECT  51.323 0.036 53.167 0.09 ;
     RECT  53.167 0.036 53.267 0.63 ;
     RECT  53.267 0.036 55.175 0.09 ;
     RECT  55.175 0.036 55.571 0.054 ;
     RECT  51.683 2.151 56.363 41.319 ;
     RECT  56.363 2.151 62.64 41.049 ;
     RECT  62.64 13.536 62.699 38.466 ;
     RECT  62.699 13.536 63.275 21.186 ;
     RECT  62.699 21.942 63.275 38.466 ;
     RECT  63.275 21.942 63.311 27.324 ;
     RECT  63.275 28.188 63.311 38.466 ;
     RECT  63.311 28.188 63.347 38.124 ;
     RECT  63.275 14.076 63.635 21.186 ;
     RECT  63.347 28.188 63.815 32.724 ;
     RECT  63.635 14.076 63.851 20.682 ;
     RECT  63.311 22.176 63.851 27.324 ;
     RECT  63.815 30.42 63.851 32.724 ;
     RECT  63.347 34.056 63.851 38.124 ;
     RECT  63.851 14.256 63.887 20.682 ;
     RECT  63.851 22.176 63.887 23.346 ;
     RECT  63.815 28.188 63.887 29.52 ;
     RECT  63.851 30.456 63.887 32.724 ;
     RECT  63.851 34.596 63.887 38.124 ;
     RECT  63.887 20.664 63.923 20.682 ;
     RECT  63.887 22.554 63.923 23.346 ;
     RECT  63.887 28.188 63.923 28.746 ;
     RECT  63.887 29.502 63.923 29.52 ;
     RECT  63.887 37.134 63.959 37.854 ;
     RECT  63.887 34.668 63.995 36.072 ;
     RECT  63.959 37.566 63.995 37.854 ;
     RECT  63.995 35.478 64.067 36.036 ;
     RECT  63.887 14.256 64.571 19.836 ;
     RECT  63.851 27.306 64.607 27.324 ;
     RECT  63.887 30.456 64.615 30.744 ;
     RECT  63.995 34.668 64.615 34.722 ;
     RECT  64.571 14.256 64.643 16.974 ;
     RECT  64.571 19.278 64.643 19.836 ;
     RECT  63.851 24.174 64.643 25.542 ;
     RECT  63.923 23.166 64.651 23.346 ;
     RECT  64.643 24.174 64.651 24.192 ;
     RECT  64.643 14.256 64.679 16.164 ;
     RECT  64.571 18 64.679 18.486 ;
     RECT  64.579 21.096 64.679 21.114 ;
     RECT  64.615 29.88 64.679 30.744 ;
     RECT  63.887 31.536 64.679 32.328 ;
     RECT  64.067 35.478 64.679 35.649 ;
     RECT  64.679 14.616 64.715 14.634 ;
     RECT  64.679 15.498 64.715 16.164 ;
     RECT  64.679 18 64.715 18.45 ;
     RECT  64.643 19.278 64.715 19.296 ;
     RECT  64.651 23.166 64.715 24.192 ;
     RECT  64.679 29.88 64.715 29.898 ;
     RECT  64.679 31.626 64.715 32.328 ;
     RECT  64.615 34.326 64.715 34.722 ;
     RECT  64.679 35.478 64.715 35.496 ;
     RECT  63.995 37.566 64.715 37.584 ;
     RECT  64.715 18.432 64.751 18.45 ;
     RECT  64.715 23.634 64.751 23.652 ;
     RECT  64.643 25.101 64.751 25.542 ;
     RECT  64.715 31.626 64.751 31.644 ;
     RECT  64.643 16.956 64.787 16.974 ;
     RECT  64.751 25.101 64.787 25.119 ;
     RECT  64.687 29.07 64.787 29.088 ;
     RECT  64.715 34.704 64.787 34.722 ;
    LAYER M3 ;
     RECT  40.68 0.031 40.698 0.067 ;
     RECT  55.548 0.031 55.566 0.067 ;
     RECT  33.48 0.043 33.498 0.091 ;
     RECT  53.244 0.043 53.262 0.091 ;
     RECT  54.036 0.043 54.054 0.091 ;
     RECT  55.152 0.067 55.566 0.091 ;
     RECT  39.78 0.043 39.798 0.103 ;
     RECT  40.68 0.067 41.382 0.103 ;
     RECT  33.408 0.091 33.858 0.139 ;
     RECT  35.208 0.091 35.334 0.139 ;
     RECT  39.78 0.103 41.382 0.139 ;
     RECT  46.188 0.043 46.458 0.139 ;
     RECT  57.024 0.043 57.042 0.139 ;
     RECT  39.78 0.139 41.922 0.173 ;
     RECT  42.768 0.043 42.894 0.173 ;
     RECT  33.3 0.139 33.858 0.187 ;
     RECT  37.08 0.091 37.494 0.187 ;
     RECT  38.7 0.139 38.718 0.187 ;
     RECT  40.68 0.173 41.922 0.187 ;
     RECT  46.188 0.139 46.71 0.187 ;
     RECT  35.208 0.139 35.586 0.221 ;
     RECT  37.08 0.187 38.718 0.235 ;
     RECT  39.78 0.173 39.798 0.235 ;
     RECT  51.3 0.103 51.318 0.235 ;
     RECT  52.164 0.091 52.182 0.235 ;
     RECT  37.08 0.235 39.798 0.269 ;
     RECT  51.3 0.235 52.182 0.317 ;
     RECT  37.08 0.269 37.314 0.331 ;
     RECT  52.992 0.091 55.566 0.331 ;
     RECT  40.68 0.187 42.03 0.365 ;
     RECT  52.956 0.331 55.566 0.379 ;
     RECT  47.772 0.139 47.79 0.427 ;
     RECT  36.756 0.331 37.314 0.461 ;
     RECT  38.088 0.269 39.798 0.461 ;
     RECT  40.68 0.365 41.526 0.461 ;
     RECT  42.768 0.173 42.858 0.461 ;
     RECT  47.772 0.427 48.042 0.475 ;
     RECT  49.032 0.091 49.05 0.475 ;
     RECT  51.768 0.317 52.182 0.475 ;
     RECT  52.956 0.379 56.142 0.475 ;
     RECT  42.84 0.461 42.858 0.509 ;
     RECT  46.152 0.187 46.71 0.523 ;
     RECT  40.716 0.461 41.526 0.554 ;
     RECT  11.016 0.523 11.034 0.571 ;
     RECT  46.152 0.523 46.818 0.571 ;
     RECT  44.136 0.523 44.154 0.667 ;
     RECT  47.772 0.475 49.05 0.715 ;
     RECT  46.152 0.571 46.926 0.749 ;
     RECT  33.3 0.187 34.254 0.811 ;
     RECT  10.872 0.571 11.034 1.003 ;
     RECT  10.548 1.003 11.034 1.051 ;
     RECT  44.136 0.667 44.406 1.051 ;
     RECT  10.476 1.051 11.034 1.099 ;
     RECT  44.136 1.051 44.73 1.099 ;
     RECT  7.668 1.147 7.686 1.195 ;
     RECT  47.772 0.715 49.698 1.435 ;
     RECT  50.472 0.955 50.49 1.435 ;
     RECT  38.088 0.461 38.142 1.483 ;
     RECT  43.632 1.099 44.73 1.531 ;
     RECT  47.772 1.435 50.49 1.579 ;
     RECT  6.228 0.523 6.246 1.627 ;
     RECT  6.228 1.627 6.282 1.675 ;
     RECT  6.228 1.675 6.354 1.723 ;
     RECT  7.668 1.195 7.794 1.723 ;
     RECT  9.18 1.003 9.198 1.723 ;
     RECT  10.404 1.099 11.034 1.723 ;
     RECT  11.844 1.675 11.862 1.723 ;
     RECT  38.052 1.483 38.142 1.723 ;
     RECT  35.28 0.221 35.586 1.771 ;
     RECT  35.28 1.771 35.694 2.101 ;
     RECT  36.756 0.461 37.098 2.101 ;
     RECT  1.98 1.723 2.214 2.143 ;
     RECT  32.94 0.811 34.254 2.143 ;
     RECT  35.28 2.101 37.098 2.143 ;
     RECT  39.42 0.461 39.798 2.143 ;
     RECT  40.716 0.554 41.49 2.143 ;
     RECT  45.54 1.099 45.558 2.143 ;
     RECT  47.736 1.579 50.49 2.143 ;
     RECT  51.768 0.475 56.142 2.143 ;
     RECT  57.024 0.139 57.15 2.143 ;
     RECT  1.98 2.143 2.505 2.191 ;
     RECT  3.528 0.571 3.546 2.191 ;
     RECT  6.12 1.723 7.974 2.219 ;
     RECT  9.18 1.723 12.078 2.219 ;
     RECT  37.872 1.723 38.142 2.255 ;
     RECT  38.016 2.255 38.142 2.285 ;
     RECT  6.156 2.219 7.974 2.413 ;
     RECT  13.215 2.143 13.305 2.413 ;
     RECT  18.615 2.143 18.705 2.413 ;
     RECT  24.015 2.143 24.105 2.413 ;
     RECT  29.415 2.143 29.505 2.413 ;
     RECT  45.54 2.143 45.705 2.413 ;
     RECT  61.815 2.143 61.905 2.413 ;
     RECT  1.98 2.191 3.618 2.633 ;
     RECT  46.692 0.749 46.926 2.635 ;
     RECT  47.736 2.143 57.15 2.635 ;
     RECT  2.304 2.633 3.618 2.641 ;
     RECT  43.2 1.531 44.73 2.731 ;
     RECT  45.54 2.413 45.897 2.731 ;
     RECT  9.18 2.219 9.666 2.759 ;
     RECT  2.304 2.641 3.654 2.858 ;
     RECT  43.2 2.731 45.897 2.861 ;
     RECT  43.2 2.861 44.802 3.115 ;
     RECT  46.692 2.635 57.15 3.115 ;
     RECT  42.84 3.115 44.802 3.163 ;
     RECT  10.404 2.219 11.034 3.307 ;
     RECT  42.768 3.163 44.802 3.341 ;
     RECT  2.304 2.858 3.69 3.343 ;
     RECT  46.692 3.115 57.474 3.403 ;
     RECT  2.304 3.343 4.05 3.451 ;
     RECT  2.268 3.451 4.086 3.613 ;
     RECT  4.824 3.343 4.842 3.613 ;
     RECT  2.268 3.613 4.842 3.677 ;
     RECT  6.156 2.413 8.097 3.685 ;
     RECT  10.296 3.307 11.034 3.685 ;
     RECT  2.304 3.677 4.842 3.721 ;
     RECT  9.18 2.759 9.234 3.811 ;
     RECT  9.972 3.685 11.034 3.811 ;
     RECT  2.304 3.721 5.202 3.839 ;
     RECT  42.84 3.341 44.802 4.109 ;
     RECT  46.62 3.403 57.474 4.109 ;
     RECT  9.18 3.811 11.034 4.153 ;
     RECT  9.144 4.153 11.034 4.225 ;
     RECT  9 4.225 11.034 4.379 ;
     RECT  2.415 3.839 5.202 4.559 ;
     RECT  6.156 3.685 8.226 4.651 ;
     RECT  9 4.379 10.962 4.651 ;
     RECT  5.148 4.559 5.202 4.963 ;
     RECT  6.156 4.651 10.962 4.963 ;
     RECT  2.415 4.559 4.302 5.131 ;
     RECT  5.148 4.963 10.962 5.131 ;
     RECT  11.844 2.219 11.862 5.131 ;
     RECT  5.148 5.131 11.862 5.189 ;
     RECT  2.304 5.131 4.302 5.341 ;
     RECT  5.148 5.189 10.962 5.341 ;
     RECT  43.2 4.109 44.802 5.341 ;
     RECT  45.54 2.861 45.897 5.341 ;
     RECT  43.2 5.341 45.897 5.405 ;
     RECT  2.304 5.341 10.962 5.459 ;
     RECT  11.844 5.189 11.862 5.659 ;
     RECT  2.415 5.459 10.71 5.741 ;
     RECT  39.42 2.143 41.49 5.995 ;
     RECT  11.844 5.659 12.006 6.235 ;
     RECT  2.415 5.741 10.566 6.269 ;
     RECT  43.2 5.405 44.802 6.283 ;
     RECT  45.54 5.405 45.897 6.283 ;
     RECT  2.415 6.269 10.386 6.317 ;
     RECT  3.96 6.317 10.386 6.539 ;
     RECT  3.96 6.539 10.242 6.809 ;
     RECT  3.96 6.809 10.17 6.881 ;
     RECT  3.96 6.881 8.262 8.861 ;
     RECT  2.415 6.317 3.114 8.941 ;
     RECT  3.96 8.861 4.014 8.941 ;
     RECT  4.86 8.861 8.262 8.969 ;
     RECT  9.216 6.881 10.17 9.149 ;
     RECT  43.2 6.283 45.897 9.691 ;
     RECT  46.8 4.109 57.474 9.691 ;
     RECT  43.2 9.691 57.474 10.157 ;
     RECT  2.415 8.941 4.014 10.831 ;
     RECT  9.288 9.149 10.17 10.843 ;
     RECT  43.2 10.157 46.062 10.987 ;
     RECT  46.8 10.157 57.474 10.987 ;
     RECT  43.2 10.987 57.474 11.011 ;
     RECT  32.94 2.143 37.098 11.179 ;
     RECT  38.052 2.285 38.142 11.179 ;
     RECT  42.768 11.011 57.474 11.399 ;
     RECT  9.288 10.843 10.458 11.407 ;
     RECT  42.984 11.399 57.474 11.408 ;
     RECT  9.216 11.407 10.458 11.419 ;
     RECT  11.412 6.235 12.006 11.419 ;
     RECT  32.94 11.179 38.142 11.551 ;
     RECT  39.42 5.995 41.958 11.551 ;
     RECT  9.216 11.419 12.006 11.749 ;
     RECT  4.968 8.969 8.262 11.785 ;
     RECT  9.072 11.749 12.006 11.785 ;
     RECT  4.968 11.785 12.006 11.939 ;
     RECT  43.2 11.408 57.474 11.981 ;
     RECT  32.94 11.551 41.958 11.984 ;
     RECT  2.415 10.831 4.23 11.995 ;
     RECT  4.968 11.939 10.314 11.995 ;
     RECT  2.415 11.995 10.314 12.595 ;
     RECT  11.088 11.939 12.006 12.749 ;
     RECT  2.412 12.595 10.314 12.763 ;
     RECT  11.088 12.749 11.106 12.785 ;
     RECT  43.2 11.981 43.218 13.051 ;
     RECT  43.956 11.981 57.474 13.051 ;
     RECT  39.42 11.984 41.958 13.127 ;
     RECT  32.94 11.984 38.142 13.339 ;
     RECT  2.268 12.763 10.314 13.405 ;
     RECT  43.2 13.051 57.474 13.441 ;
     RECT  58.392 2.587 58.41 13.441 ;
     RECT  63.252 13.387 63.27 13.483 ;
     RECT  61.815 2.413 62.097 13.567 ;
     RECT  63.252 13.483 63.846 13.579 ;
     RECT  2.268 13.405 10.494 13.595 ;
     RECT  43.2 13.441 58.41 13.603 ;
     RECT  61.812 13.567 62.097 13.639 ;
     RECT  63.216 13.579 63.846 13.639 ;
     RECT  61.812 13.639 63.846 13.805 ;
     RECT  63.216 13.805 63.846 13.829 ;
     RECT  64.692 13.675 64.71 13.867 ;
     RECT  39.492 13.127 41.958 13.945 ;
     RECT  64.656 13.867 64.71 14.059 ;
     RECT  39.492 13.945 42.246 14.099 ;
     RECT  63.252 13.829 63.846 14.135 ;
     RECT  64.62 14.059 64.71 14.155 ;
     RECT  43.02 13.603 58.41 14.203 ;
     RECT  43.02 14.203 58.734 14.243 ;
     RECT  60.912 13.291 60.93 14.251 ;
     RECT  61.812 13.805 62.097 14.251 ;
     RECT  32.94 13.339 38.538 14.279 ;
     RECT  2.268 13.595 10.35 14.369 ;
     RECT  63.288 14.135 63.846 14.381 ;
     RECT  39.492 14.099 42.03 14.521 ;
     RECT  60.912 14.251 62.097 14.539 ;
     RECT  0.108 13.567 0.126 14.573 ;
     RECT  39.348 14.521 42.03 14.573 ;
     RECT  43.02 14.243 58.518 14.647 ;
     RECT  39.456 14.573 42.03 14.827 ;
     RECT  42.804 14.647 58.518 14.827 ;
     RECT  63.792 14.381 63.846 14.827 ;
     RECT  64.584 14.155 64.71 14.827 ;
     RECT  2.268 14.369 10.206 14.909 ;
     RECT  60.912 14.539 62.19 14.917 ;
     RECT  39.456 14.827 58.518 14.957 ;
     RECT  63.792 14.827 64.71 14.957 ;
     RECT  60.624 14.917 62.19 14.989 ;
     RECT  39.492 14.957 58.518 15.025 ;
     RECT  1.152 13.063 1.17 15.053 ;
     RECT  2.268 14.909 10.098 15.089 ;
     RECT  63.792 14.957 63.846 15.115 ;
     RECT  60.552 14.989 62.19 15.179 ;
     RECT  60.552 15.179 60.93 15.295 ;
     RECT  0.54 15.187 0.558 15.331 ;
     RECT  63.252 15.115 63.846 15.359 ;
     RECT  60.408 15.295 60.93 15.421 ;
     RECT  0.504 15.331 0.558 15.437 ;
     RECT  61.776 15.179 62.19 15.457 ;
     RECT  61.776 15.457 62.262 15.499 ;
     RECT  61.776 15.499 62.37 15.595 ;
     RECT  32.94 14.279 35.658 15.601 ;
     RECT  0.504 15.437 0.522 15.629 ;
     RECT  61.776 15.595 62.694 15.719 ;
     RECT  60.3 15.421 60.93 15.727 ;
     RECT  39.492 15.025 58.806 15.799 ;
     RECT  59.652 15.727 60.93 15.799 ;
     RECT  2.268 15.089 10.062 15.871 ;
     RECT  32.94 15.601 36.054 15.979 ;
     RECT  36.792 14.279 38.538 15.979 ;
     RECT  64.62 14.957 64.71 15.979 ;
     RECT  15.192 15.871 15.21 15.989 ;
     RECT  63.792 15.359 63.846 15.997 ;
     RECT  64.584 15.979 64.71 15.997 ;
     RECT  39.492 15.799 60.93 16.105 ;
     RECT  61.776 15.719 62.514 16.105 ;
     RECT  18.615 2.413 18.897 16.141 ;
     RECT  15.984 16.141 16.002 16.231 ;
     RECT  17.316 16.141 18.897 16.259 ;
     RECT  15.984 16.231 16.542 16.295 ;
     RECT  39.492 16.105 62.514 16.303 ;
     RECT  16.524 16.295 16.542 16.331 ;
     RECT  63.792 15.997 64.71 16.411 ;
     RECT  15.048 16.105 15.066 16.493 ;
     RECT  0.216 16.027 0.342 16.501 ;
     RECT  2.268 15.871 10.278 16.501 ;
     RECT  13.215 2.413 13.497 16.501 ;
     RECT  12.636 16.501 13.497 16.537 ;
     RECT  12.456 16.537 13.497 16.541 ;
     RECT  39.42 16.303 62.514 16.555 ;
     RECT  63.288 16.411 64.71 16.555 ;
     RECT  18 16.259 18.897 16.565 ;
     RECT  0.216 16.501 0.558 16.589 ;
     RECT  2.124 16.501 10.278 16.589 ;
     RECT  12.456 16.541 12.474 16.589 ;
     RECT  2.268 16.589 10.278 16.601 ;
     RECT  32.94 15.979 38.538 16.603 ;
     RECT  32.94 16.603 38.61 16.609 ;
     RECT  39.42 16.555 64.71 16.609 ;
     RECT  32.94 16.609 64.71 16.951 ;
     RECT  0.144 16.891 0.162 17.069 ;
     RECT  2.304 16.601 10.278 17.179 ;
     RECT  16.38 17.491 16.542 17.609 ;
     RECT  2.304 17.179 10.35 17.645 ;
     RECT  2.304 17.645 10.278 17.707 ;
     RECT  2.196 17.707 10.278 17.753 ;
     RECT  16.524 17.609 16.542 17.851 ;
     RECT  2.304 17.753 10.278 17.915 ;
     RECT  11.16 17.659 11.178 17.915 ;
     RECT  16.524 17.851 17.622 17.915 ;
     RECT  30.996 17.947 31.014 17.989 ;
     RECT  18.615 16.565 18.897 17.995 ;
     RECT  30.744 17.989 31.014 18.029 ;
     RECT  17.316 17.915 17.622 18.031 ;
     RECT  18.54 17.995 18.897 18.031 ;
     RECT  16.524 17.915 16.542 18.059 ;
     RECT  17.316 18.031 18.954 18.121 ;
     RECT  17.316 18.121 19.602 18.157 ;
     RECT  17.316 18.157 19.962 18.185 ;
     RECT  21.096 18.121 21.114 18.193 ;
     RECT  11.268 18.031 11.286 18.221 ;
     RECT  21.096 18.193 21.258 18.221 ;
     RECT  18.615 18.185 19.962 18.301 ;
     RECT  18.615 18.301 20.142 18.419 ;
     RECT  2.34 17.915 10.278 18.455 ;
     RECT  17.316 18.185 17.622 18.661 ;
     RECT  17.172 18.661 17.622 18.689 ;
     RECT  30.888 18.029 31.014 18.76 ;
     RECT  13.215 16.541 13.497 18.763 ;
     RECT  2.34 18.455 10.098 18.769 ;
     RECT  30.888 18.76 31.626 18.797 ;
     RECT  32.94 16.951 64.782 18.811 ;
     RECT  2.268 18.769 10.098 18.841 ;
     RECT  15.984 18.391 16.002 18.959 ;
     RECT  18.615 18.419 19.998 18.959 ;
     RECT  30.888 18.797 31.05 19.075 ;
     RECT  12.744 18.763 13.497 19.099 ;
     RECT  21.24 18.221 21.258 19.111 ;
     RECT  19.836 18.959 19.998 19.201 ;
     RECT  20.916 19.111 21.258 19.201 ;
     RECT  12.564 19.099 13.497 19.265 ;
     RECT  19.836 19.201 21.258 19.265 ;
     RECT  20.376 19.265 21.258 19.301 ;
     RECT  20.988 19.301 21.258 19.337 ;
     RECT  32.76 18.811 64.782 19.339 ;
     RECT  21.24 19.337 21.258 19.381 ;
     RECT  0.108 19.075 0.126 19.469 ;
     RECT  17.172 18.689 17.334 19.499 ;
     RECT  25.056 19.471 25.074 19.517 ;
     RECT  22.644 19.111 22.662 19.535 ;
     RECT  32.688 19.339 64.782 19.543 ;
     RECT  26.784 19.483 26.802 19.613 ;
     RECT  30.636 19.075 31.05 19.627 ;
     RECT  18.615 18.959 18.897 19.651 ;
     RECT  21.24 19.381 21.33 19.651 ;
     RECT  30.636 19.627 31.338 19.651 ;
     RECT  21.24 19.651 21.798 19.771 ;
     RECT  22.572 19.741 22.59 19.771 ;
     RECT  21.24 19.771 22.59 19.805 ;
     RECT  32.22 19.543 64.782 19.867 ;
     RECT  30.456 19.651 31.338 19.885 ;
     RECT  32.148 19.867 64.782 19.885 ;
     RECT  30.456 19.885 64.782 19.913 ;
     RECT  18.396 19.651 18.897 19.915 ;
     RECT  24.015 2.413 24.297 19.921 ;
     RECT  18.396 19.915 19.35 20.011 ;
     RECT  13.215 19.265 13.497 20.047 ;
     RECT  21.24 19.805 22.266 20.075 ;
     RECT  12.996 20.047 13.497 20.093 ;
     RECT  21.24 20.075 22.014 20.309 ;
     RECT  17.784 20.011 19.35 20.345 ;
     RECT  2.232 18.841 10.098 20.491 ;
     RECT  18.36 20.345 19.35 20.491 ;
     RECT  21.24 20.309 21.87 20.491 ;
     RECT  20.88 20.491 21.87 20.525 ;
     RECT  18.36 20.491 19.962 20.669 ;
     RECT  29.415 2.413 29.697 20.683 ;
     RECT  30.528 19.913 64.782 20.683 ;
     RECT  2.196 20.491 10.098 20.849 ;
     RECT  18.615 20.669 19.962 21.001 ;
     RECT  29.415 20.683 64.782 21.101 ;
     RECT  18.615 21.001 20.034 21.119 ;
     RECT  18.615 21.119 19.35 21.155 ;
     RECT  13.215 20.093 13.497 21.163 ;
     RECT  2.268 20.849 10.098 21.299 ;
     RECT  20.88 20.525 21.258 21.425 ;
     RECT  13.215 21.163 13.59 21.451 ;
     RECT  2.304 21.299 10.098 21.541 ;
     RECT  21.24 21.425 21.258 21.541 ;
     RECT  13.215 21.451 13.842 21.929 ;
     RECT  13.215 21.929 13.497 22.027 ;
     RECT  12.708 22.027 13.497 22.073 ;
     RECT  21.24 21.541 21.906 22.081 ;
     RECT  29.415 21.101 63.63 22.171 ;
     RECT  64.512 21.101 64.782 22.171 ;
     RECT  21.24 22.081 22.05 22.199 ;
     RECT  21.348 22.199 21.366 22.205 ;
     RECT  2.304 21.541 10.242 22.603 ;
     RECT  2.268 22.603 10.242 22.775 ;
     RECT  29.415 22.171 64.782 23.117 ;
     RECT  2.304 22.775 10.242 23.521 ;
     RECT  2.232 23.521 10.242 23.557 ;
     RECT  2.232 23.557 10.422 23.597 ;
     RECT  11.34 23.521 11.358 23.597 ;
     RECT  29.415 23.117 63.63 23.851 ;
     RECT  64.512 23.117 64.782 23.851 ;
     RECT  2.232 23.597 10.242 23.885 ;
     RECT  29.415 23.851 64.782 24.077 ;
     RECT  23.616 19.921 24.297 24.125 ;
     RECT  22.104 22.207 22.122 24.241 ;
     RECT  22.104 24.241 22.194 24.395 ;
     RECT  22.176 24.395 22.194 24.475 ;
     RECT  26.784 24.709 26.802 24.899 ;
     RECT  29.415 24.077 62.766 24.907 ;
     RECT  63.576 24.077 64.782 24.907 ;
     RECT  2.268 23.885 10.242 25.015 ;
     RECT  29.415 24.907 64.782 25.079 ;
     RECT  26.604 25.015 26.622 25.085 ;
     RECT  64.584 25.079 64.782 25.124 ;
     RECT  0.108 24.871 0.126 25.141 ;
     RECT  18.615 21.155 18.897 25.483 ;
     RECT  0.108 25.141 0.558 25.805 ;
     RECT  29.415 25.079 63.846 25.861 ;
     RECT  13.215 22.073 13.497 25.951 ;
     RECT  24.015 24.125 24.297 25.951 ;
     RECT  13.104 25.951 13.497 25.997 ;
     RECT  23.904 25.951 24.297 25.997 ;
     RECT  28.908 25.861 63.846 26.015 ;
     RECT  26.784 25.819 26.802 26.141 ;
     RECT  22.176 24.475 22.338 26.249 ;
     RECT  0.144 25.805 0.558 26.251 ;
     RECT  2.232 25.015 10.242 26.293 ;
     RECT  22.176 26.249 22.194 26.365 ;
     RECT  2.196 26.293 10.242 26.381 ;
     RECT  0.144 26.251 0.63 26.573 ;
     RECT  0.144 26.573 0.162 26.621 ;
     RECT  21.96 26.365 22.194 26.761 ;
     RECT  18.615 25.483 19.422 26.779 ;
     RECT  24.015 25.997 24.297 26.779 ;
     RECT  13.215 25.997 13.497 26.923 ;
     RECT  24.015 26.779 24.498 26.923 ;
     RECT  23.904 26.923 24.498 26.969 ;
     RECT  18.615 26.779 19.818 27.031 ;
     RECT  13.104 26.923 13.497 27.067 ;
     RECT  26.784 26.923 26.802 27.101 ;
     RECT  18.615 27.031 19.926 27.149 ;
     RECT  21.636 26.761 22.194 27.175 ;
     RECT  21.636 27.175 22.59 27.211 ;
     RECT  29.415 26.015 63.846 27.211 ;
     RECT  64.584 25.124 64.746 27.211 ;
     RECT  18.615 27.149 19.422 27.239 ;
     RECT  12.744 27.067 13.497 27.307 ;
     RECT  21.636 27.211 23.202 27.329 ;
     RECT  24.015 26.969 24.498 27.329 ;
     RECT  29.415 27.211 64.746 27.329 ;
     RECT  21.636 27.329 22.194 27.365 ;
     RECT  23.04 27.329 23.058 27.365 ;
     RECT  2.304 26.381 10.242 27.499 ;
     RECT  12.744 27.307 13.662 27.599 ;
     RECT  1.152 27.691 1.17 27.787 ;
     RECT  2.268 27.499 10.242 27.787 ;
     RECT  12.744 27.599 13.497 27.869 ;
     RECT  21.42 28.021 21.438 28.111 ;
     RECT  22.176 27.365 22.194 28.111 ;
     RECT  21.42 28.111 22.194 28.175 ;
     RECT  29.415 27.329 63.882 28.183 ;
     RECT  64.62 27.329 64.746 28.183 ;
     RECT  21.528 28.175 21.546 28.205 ;
     RECT  11.34 28.291 11.358 28.409 ;
     RECT  22.284 28.291 22.302 28.445 ;
     RECT  29.415 28.183 64.746 28.589 ;
     RECT  26.748 28.921 26.766 28.957 ;
     RECT  26.208 28.957 26.766 28.973 ;
     RECT  64.656 28.589 64.746 29.065 ;
     RECT  29.415 28.589 63.918 29.323 ;
     RECT  64.656 29.065 64.782 29.323 ;
     RECT  29.415 29.323 64.782 29.335 ;
     RECT  29.052 29.335 64.782 29.405 ;
     RECT  1.152 27.787 10.242 29.461 ;
     RECT  1.152 29.461 10.278 29.795 ;
     RECT  1.152 29.795 10.242 29.867 ;
     RECT  26.208 28.973 26.226 30.269 ;
     RECT  11.304 29.911 11.322 30.451 ;
     RECT  1.728 29.867 10.242 30.479 ;
     RECT  11.304 30.451 11.466 30.605 ;
     RECT  27.864 30.541 27.882 30.605 ;
     RECT  11.448 30.605 11.466 30.653 ;
     RECT  11.484 30.712 11.502 30.749 ;
     RECT  27.324 30.685 27.342 30.749 ;
     RECT  0.108 30.859 0.126 30.883 ;
     RECT  29.415 29.405 64.782 30.941 ;
     RECT  2.268 30.479 10.242 30.991 ;
     RECT  1.152 30.907 1.242 31.085 ;
     RECT  13.215 27.869 13.497 31.243 ;
     RECT  24.015 27.329 24.297 31.243 ;
     RECT  2.268 30.991 10.386 31.261 ;
     RECT  1.224 31.085 1.242 31.277 ;
     RECT  26.784 31.147 26.802 31.277 ;
     RECT  13.104 31.243 13.497 31.289 ;
     RECT  23.904 31.243 24.297 31.289 ;
     RECT  64.656 30.941 64.782 31.661 ;
     RECT  0.108 30.883 0.342 31.757 ;
     RECT  0.108 31.757 0.126 31.853 ;
     RECT  2.268 31.261 10.674 31.891 ;
     RECT  29.415 30.941 63.882 32.093 ;
     RECT  29.415 32.093 32.31 32.099 ;
     RECT  29.415 32.099 31.986 32.189 ;
     RECT  33.084 32.093 63.882 32.233 ;
     RECT  33.084 32.233 63.918 32.333 ;
     RECT  2.268 31.891 10.89 32.341 ;
     RECT  2.268 32.341 11.07 32.431 ;
     RECT  25.884 32.431 25.902 32.467 ;
     RECT  2.268 32.431 11.322 32.477 ;
     RECT  25.668 32.467 25.902 32.477 ;
     RECT  2.268 32.477 10.89 32.495 ;
     RECT  25.668 32.477 25.686 32.525 ;
     RECT  33.66 32.333 63.918 32.576 ;
     RECT  33.984 32.576 63.918 32.621 ;
     RECT  64.692 31.661 64.782 32.731 ;
     RECT  33.984 32.621 63.882 32.813 ;
     RECT  2.304 32.495 10.89 32.909 ;
     RECT  34.02 32.813 63.882 32.909 ;
     RECT  64.62 32.731 64.782 32.909 ;
     RECT  27.756 32.827 27.774 32.999 ;
     RECT  34.524 32.909 63.882 33.035 ;
     RECT  2.34 32.909 10.89 33.053 ;
     RECT  26.784 32.299 26.802 33.053 ;
     RECT  29.415 32.189 31.914 33.067 ;
     RECT  2.34 33.053 5.418 33.269 ;
     RECT  34.596 33.035 63.882 33.389 ;
     RECT  2.34 33.269 5.166 33.539 ;
     RECT  6.264 33.053 10.89 33.547 ;
     RECT  2.415 33.539 5.094 33.575 ;
     RECT  29.415 33.067 32.13 33.643 ;
     RECT  64.764 32.909 64.782 33.739 ;
     RECT  27.72 33.595 27.738 33.809 ;
     RECT  29.415 33.643 32.634 33.809 ;
     RECT  6.264 33.547 11.394 33.817 ;
     RECT  6.264 33.817 12.042 33.961 ;
     RECT  29.415 33.809 32.49 33.965 ;
     RECT  6.264 33.961 12.258 34.115 ;
     RECT  34.596 33.389 63.846 34.219 ;
     RECT  64.62 33.739 64.782 34.397 ;
     RECT  34.092 34.219 63.846 34.591 ;
     RECT  34.092 34.591 63.882 34.663 ;
     RECT  64.764 34.397 64.782 34.727 ;
     RECT  34.092 34.663 63.99 34.735 ;
     RECT  33.948 34.735 63.99 34.781 ;
     RECT  34.524 34.781 63.99 35.033 ;
     RECT  34.596 35.033 63.99 35.179 ;
     RECT  33.084 34.555 33.102 35.213 ;
     RECT  34.596 35.179 64.71 35.501 ;
     RECT  34.596 35.501 64.674 35.654 ;
     RECT  34.596 35.654 64.062 35.693 ;
     RECT  34.596 35.693 62.766 35.755 ;
     RECT  63.828 35.693 64.062 35.807 ;
     RECT  34.524 35.755 62.766 35.851 ;
     RECT  34.308 35.851 62.766 35.885 ;
     RECT  34.308 35.885 62.73 35.969 ;
     RECT  34.308 35.969 57.762 35.995 ;
     RECT  33.876 35.995 57.762 36.005 ;
     RECT  33.876 36.005 57.546 36.029 ;
     RECT  33.876 36.029 57.366 36.239 ;
     RECT  34.308 36.239 57.366 36.269 ;
     RECT  28.584 36.235 28.602 36.275 ;
     RECT  34.815 36.269 57.366 36.509 ;
     RECT  6.264 34.115 10.674 36.617 ;
     RECT  63.864 35.807 64.062 36.653 ;
     RECT  58.536 35.969 62.73 36.751 ;
     RECT  63.864 36.653 63.954 36.751 ;
     RECT  34.815 36.509 54.018 36.779 ;
     RECT  42.732 36.779 54.018 36.851 ;
     RECT  42.732 36.851 43.722 36.923 ;
     RECT  6.804 36.617 10.674 36.931 ;
     RECT  11.592 34.115 12.258 36.931 ;
     RECT  34.815 36.779 41.742 36.941 ;
     RECT  42.732 36.923 43.038 36.989 ;
     RECT  54.864 36.509 57.366 37.049 ;
     RECT  34.815 36.941 41.598 37.051 ;
     RECT  28.332 36.355 28.35 37.085 ;
     RECT  54.864 37.049 55.458 37.193 ;
     RECT  58.536 36.751 63.954 37.193 ;
     RECT  44.46 36.851 54.018 37.229 ;
     RECT  53.964 37.229 54.018 37.277 ;
     RECT  34.704 37.051 41.598 37.319 ;
     RECT  54.864 37.193 55.17 37.319 ;
     RECT  34.704 37.319 40.497 37.327 ;
     RECT  34.596 37.327 40.497 37.373 ;
     RECT  44.46 37.229 52.686 37.373 ;
     RECT  6.804 36.931 12.258 37.399 ;
     RECT  56.304 37.049 57.294 37.421 ;
     RECT  54 37.277 54.018 37.435 ;
     RECT  54.864 37.319 54.954 37.435 ;
     RECT  2.415 33.575 3.582 37.469 ;
     RECT  6.732 37.399 12.258 37.517 ;
     RECT  34.815 37.373 40.497 37.589 ;
     RECT  45.576 37.373 51.297 37.589 ;
     RECT  64.692 37.483 64.71 37.589 ;
     RECT  27.036 33.925 27.054 37.613 ;
     RECT  34.815 37.589 39.294 37.625 ;
     RECT  40.032 37.589 40.497 37.625 ;
     RECT  58.644 37.193 63.954 37.625 ;
     RECT  61.56 37.625 63.954 37.831 ;
     RECT  56.415 37.421 57.294 37.895 ;
     RECT  61.56 37.831 63.99 37.901 ;
     RECT  41.544 37.319 41.598 38.155 ;
     RECT  61.56 37.901 62.334 38.165 ;
     RECT  52.2 37.373 52.686 38.189 ;
     RECT  6.804 37.517 12.258 38.201 ;
     RECT  44.46 37.373 44.622 38.203 ;
     RECT  56.415 37.895 56.697 38.203 ;
     RECT  34.815 37.625 39.15 38.237 ;
     RECT  41.328 38.155 41.598 38.237 ;
     RECT  61.596 38.165 62.334 38.285 ;
     RECT  52.488 38.189 52.686 38.399 ;
     RECT  55.8 38.203 56.697 38.399 ;
     RECT  61.815 38.285 62.334 38.435 ;
     RECT  6.84 38.201 12.258 38.471 ;
     RECT  63.288 37.901 63.99 38.477 ;
     RECT  54 37.435 54.954 38.479 ;
     RECT  43.956 38.203 44.622 38.515 ;
     RECT  54 38.479 55.602 38.525 ;
     RECT  63.972 38.477 63.99 38.573 ;
     RECT  40.215 37.625 40.497 38.632 ;
     RECT  41.256 38.551 41.274 38.632 ;
     RECT  40.215 38.632 41.274 38.677 ;
     RECT  39.888 38.677 41.274 38.717 ;
     RECT  54 38.525 54.954 38.741 ;
     RECT  34.815 38.237 37.602 38.777 ;
     RECT  50.148 37.589 51.297 38.779 ;
     RECT  43.02 36.989 43.038 38.827 ;
     RECT  6.876 38.471 12.258 38.975 ;
     RECT  7.02 38.975 12.258 39.011 ;
     RECT  42.768 38.827 43.038 39.019 ;
     RECT  40.068 38.717 41.274 39.149 ;
     RECT  45.576 37.589 49.014 39.181 ;
     RECT  50.112 38.779 51.297 39.181 ;
     RECT  38.448 38.237 39.15 39.217 ;
     RECT  43.776 38.515 44.622 39.217 ;
     RECT  45.576 39.181 51.297 39.217 ;
     RECT  40.215 39.149 41.274 39.355 ;
     RECT  42.156 39.019 43.038 39.355 ;
     RECT  43.776 39.217 51.297 39.355 ;
     RECT  56.415 38.399 56.697 39.355 ;
     RECT  37.584 38.777 37.602 39.403 ;
     RECT  38.448 39.217 39.33 39.403 ;
     RECT  54 38.741 54.882 39.487 ;
     RECT  34.815 38.777 36.846 39.581 ;
     RECT  36.18 39.581 36.846 39.589 ;
     RECT  37.584 39.403 39.33 39.589 ;
     RECT  7.056 39.011 12.258 39.623 ;
     RECT  57.528 39.355 57.546 39.749 ;
     RECT  40.215 39.355 51.297 39.787 ;
     RECT  52.668 38.399 52.686 39.865 ;
     RECT  3.564 37.469 3.582 39.883 ;
     RECT  4.428 33.575 5.094 39.883 ;
     RECT  29.415 33.965 31.914 39.883 ;
     RECT  36.18 39.589 39.33 39.883 ;
     RECT  40.215 39.787 51.822 39.883 ;
     RECT  54 39.487 55.062 39.883 ;
     RECT  56.16 39.355 56.697 39.883 ;
     RECT  3.564 39.883 5.094 39.931 ;
     RECT  53.532 39.883 55.17 39.991 ;
     RECT  56.16 39.883 57.33 39.991 ;
     RECT  52.56 39.865 52.686 40.021 ;
     RECT  53.532 39.991 57.33 40.021 ;
     RECT  36.18 39.883 51.822 40.135 ;
     RECT  52.56 40.021 57.33 40.135 ;
     RECT  5.94 40.171 5.958 40.289 ;
     RECT  27.288 39.883 27.306 40.289 ;
     RECT  3.492 39.931 5.094 40.297 ;
     RECT  7.416 39.623 12.258 40.325 ;
     RECT  2.415 37.469 2.697 40.333 ;
     RECT  3.492 40.297 5.562 40.333 ;
     RECT  36.18 40.135 57.33 40.36 ;
     RECT  2.415 40.333 5.562 40.405 ;
     RECT  33.3 39.883 33.318 40.405 ;
     RECT  29.415 39.883 32.454 40.459 ;
     RECT  33.192 40.405 33.318 40.459 ;
     RECT  36.144 40.36 57.33 40.507 ;
     RECT  36.144 40.507 57.474 40.555 ;
     RECT  58.644 37.625 59.13 40.555 ;
     RECT  2.196 40.405 5.562 40.559 ;
     RECT  29.415 40.459 33.318 40.559 ;
     RECT  34.815 39.581 35.37 40.651 ;
     RECT  5.076 40.559 5.562 40.667 ;
     RECT  2.196 40.559 4.158 40.703 ;
     RECT  5.4 40.667 5.562 40.703 ;
     RECT  34.776 40.651 35.37 40.711 ;
     RECT  36.144 40.555 59.13 40.711 ;
     RECT  34.776 40.711 59.13 40.739 ;
     RECT  13.215 31.289 13.497 40.787 ;
     RECT  18.615 27.239 18.897 40.787 ;
     RECT  24.015 31.289 24.297 40.787 ;
     RECT  61.815 38.435 62.097 40.787 ;
     RECT  34.776 40.739 58.662 40.829 ;
     RECT  5.4 40.703 5.418 40.865 ;
     RECT  7.488 40.325 8.586 40.865 ;
     RECT  57.816 40.829 57.834 40.865 ;
     RECT  27.36 40.837 27.378 40.877 ;
     RECT  34.776 40.829 35.406 40.877 ;
     RECT  36.468 40.829 56.898 40.877 ;
     RECT  2.196 40.703 2.934 40.901 ;
     RECT  58.644 40.829 58.662 40.937 ;
     RECT  2.196 40.901 2.826 40.973 ;
     RECT  34.776 40.877 35.37 40.973 ;
     RECT  36.468 40.877 38.97 40.973 ;
     RECT  39.816 40.877 56.898 40.973 ;
     RECT  9.36 40.325 12.258 40.981 ;
     RECT  39.816 40.973 56.505 41.009 ;
     RECT  2.196 40.973 2.574 41.021 ;
     RECT  26.352 40.441 26.37 41.021 ;
     RECT  36.468 40.973 38.898 41.021 ;
     RECT  39.816 41.009 40.806 41.021 ;
     RECT  41.58 41.009 43.362 41.021 ;
     RECT  44.136 41.009 56.505 41.021 ;
     RECT  7.56 40.865 8.586 41.032 ;
     RECT  13.215 40.787 13.305 41.057 ;
     RECT  18.615 40.787 18.705 41.057 ;
     RECT  24.015 40.787 24.105 41.057 ;
     RECT  29.415 40.559 32.814 41.057 ;
     RECT  34.815 40.973 35.37 41.057 ;
     RECT  50.544 41.021 56.505 41.057 ;
     RECT  61.815 40.787 61.905 41.057 ;
     RECT  41.58 41.021 41.886 41.069 ;
     RECT  50.544 41.057 56.394 41.099 ;
     RECT  2.376 41.021 2.574 41.213 ;
     RECT  2.556 41.213 2.574 41.261 ;
     RECT  30.096 41.057 32.814 41.296 ;
     RECT  33.588 40.747 33.606 41.296 ;
     RECT  0.54 40.711 0.558 41.357 ;
     RECT  50.688 41.099 56.394 41.357 ;
     RECT  44.424 41.021 49.518 41.369 ;
     RECT  42.66 41.021 43.362 41.405 ;
     RECT  48.132 41.369 49.518 41.549 ;
     RECT  7.56 41.032 8.55 41.597 ;
     RECT  9.36 40.981 12.33 41.645 ;
     RECT  37.44 41.021 38.07 41.645 ;
     RECT  38.88 41.021 38.898 41.645 ;
     RECT  40.176 41.021 40.806 41.645 ;
     RECT  48.132 41.549 48.51 41.645 ;
     RECT  9.36 41.645 12.258 41.693 ;
     RECT  42.66 41.405 42.75 41.741 ;
     RECT  55.296 41.357 56.394 41.885 ;
     RECT  55.296 41.885 55.71 41.933 ;
     RECT  42.66 41.741 42.678 42.029 ;
     RECT  50.688 41.357 54.126 42.029 ;
     RECT  30.096 41.296 33.606 42.077 ;
     RECT  36.468 41.021 36.486 42.077 ;
     RECT  44.424 41.369 47.394 42.077 ;
     RECT  30.528 42.077 31.518 42.125 ;
     RECT  7.56 41.597 7.65 42.173 ;
     RECT  9.36 41.693 11.862 42.173 ;
     RECT  37.584 41.645 38.07 42.173 ;
     RECT  30.564 42.125 31.518 42.179 ;
     RECT  8.46 41.597 8.55 42.221 ;
     RECT  10.8 42.173 11.61 42.221 ;
     RECT  32.436 42.077 33.606 42.221 ;
     RECT  37.584 42.173 37.674 42.221 ;
     RECT  44.424 42.077 45.954 42.221 ;
     RECT  8.532 42.221 8.55 42.269 ;
     RECT  44.424 42.221 45.774 42.509 ;
     RECT  29.664 42.151 29.682 42.571 ;
     RECT  32.436 42.221 33.318 42.605 ;
     RECT  35.28 41.057 35.37 42.605 ;
     RECT  11.088 42.221 11.502 42.653 ;
     RECT  41.58 41.069 41.598 42.653 ;
     RECT  29.124 42.571 29.682 42.667 ;
     RECT  37.656 42.221 37.674 42.701 ;
     RECT  44.424 42.509 45.09 42.701 ;
     RECT  47.088 42.077 47.394 42.763 ;
     RECT  50.688 42.029 53.55 42.763 ;
     RECT  29.088 42.667 29.682 42.797 ;
     RECT  32.472 42.605 33.318 42.797 ;
     RECT  35.28 42.605 35.298 42.797 ;
     RECT  36.36 42.667 36.378 42.811 ;
     RECT  33.084 42.797 33.318 42.845 ;
     RECT  36.252 42.811 36.378 42.845 ;
     RECT  50.616 42.763 53.55 42.845 ;
     RECT  52.452 42.845 53.55 42.893 ;
     RECT  36.252 42.845 36.27 42.907 ;
     RECT  30.672 42.179 31.518 42.941 ;
     RECT  33.3 42.845 33.318 42.941 ;
     RECT  36.144 42.907 36.27 42.941 ;
     RECT  44.424 42.701 45.054 42.941 ;
     RECT  53.028 42.893 53.55 42.941 ;
     RECT  47.088 42.763 47.538 42.952 ;
     RECT  48.384 41.645 48.51 42.952 ;
     RECT  29.124 42.797 29.682 42.955 ;
     RECT  40.176 41.645 40.374 42.955 ;
     RECT  46.728 42.952 48.51 42.989 ;
     RECT  53.028 42.941 53.046 42.989 ;
     RECT  50.616 42.845 51.282 43.025 ;
     RECT  7.632 42.173 7.65 43.037 ;
     RECT  30.888 42.941 31.518 43.037 ;
     RECT  34.776 42.907 34.794 43.037 ;
     RECT  36.144 42.941 36.162 43.037 ;
     RECT  47.088 42.989 48.51 43.037 ;
     RECT  49.5 41.549 49.518 43.051 ;
     RECT  10.872 42.955 10.89 43.085 ;
     RECT  29.124 42.955 29.79 43.085 ;
     RECT  31.392 43.037 31.518 43.085 ;
     RECT  39.924 42.955 40.41 43.085 ;
     RECT  47.088 43.037 47.79 43.085 ;
     RECT  55.296 41.933 55.314 43.085 ;
     RECT  45.036 42.941 45.054 43.097 ;
     RECT  45.828 43.051 45.846 43.097 ;
     RECT  47.52 43.085 47.79 43.097 ;
     RECT  49.392 43.051 49.806 43.097 ;
     RECT  27.828 43.003 27.846 43.133 ;
     RECT  43.884 43.069 43.902 43.133 ;
     RECT  47.52 43.097 47.718 43.133 ;
     RECT  51.264 43.025 51.282 43.133 ;
     RECT  26.748 43.051 26.766 43.181 ;
     RECT  47.592 43.133 47.61 43.181 ;
    LAYER M4 ;
     RECT  0.084 30.672 0.097 30.696 ;
     RECT  0.06 30.696 0.097 30.768 ;
     RECT  0.084 30.768 0.097 30.792 ;
     RECT  0.06 30.792 0.097 30.864 ;
     RECT  0.084 30.864 0.097 30.888 ;
     RECT  0.06 30.888 0.097 30.96 ;
     RECT  0.084 30.96 0.097 30.984 ;
     RECT  0.06 30.984 0.097 31.056 ;
     RECT  0.084 31.056 0.097 31.08 ;
     RECT  0.06 31.08 0.097 31.152 ;
     RECT  0.084 31.152 0.097 31.176 ;
     RECT  0.06 31.176 0.097 31.248 ;
     RECT  0.084 31.248 0.097 31.272 ;
     RECT  0.06 31.272 0.097 31.344 ;
     RECT  0.084 31.344 0.097 31.368 ;
     RECT  0.06 31.368 0.097 31.44 ;
     RECT  0.084 31.44 0.097 31.464 ;
     RECT  0.06 31.464 0.097 31.536 ;
     RECT  0.084 31.536 0.097 31.56 ;
     RECT  0.06 31.56 0.097 31.632 ;
     RECT  0.084 31.632 0.097 31.656 ;
     RECT  0.06 31.656 0.097 31.728 ;
     RECT  0.084 31.728 0.097 31.752 ;
     RECT  0.084 14.448 0.133 14.472 ;
     RECT  0.06 14.472 0.133 14.544 ;
     RECT  0.084 14.544 0.133 14.568 ;
     RECT  0.06 14.568 0.133 14.64 ;
     RECT  0.084 14.64 0.133 14.664 ;
     RECT  0.06 14.664 0.133 14.736 ;
     RECT  0.084 14.736 0.133 14.76 ;
     RECT  0.06 14.76 0.133 14.832 ;
     RECT  0.084 14.832 0.133 14.856 ;
     RECT  0.06 14.856 0.133 14.928 ;
     RECT  0.084 14.928 0.133 14.952 ;
     RECT  0.06 14.952 0.133 15.024 ;
     RECT  0.084 15.024 0.133 15.048 ;
     RECT  0.06 15.048 0.133 15.12 ;
     RECT  0.084 15.12 0.133 15.144 ;
     RECT  0.06 15.144 0.133 15.216 ;
     RECT  0.084 15.216 0.133 15.24 ;
     RECT  0.06 15.24 0.133 15.312 ;
     RECT  0.084 15.312 0.133 15.336 ;
     RECT  0.06 15.336 0.133 15.408 ;
     RECT  0.084 15.408 0.133 15.432 ;
     RECT  0.06 15.432 0.133 15.504 ;
     RECT  0.084 15.504 0.133 15.528 ;
     RECT  0.06 15.528 0.133 15.6 ;
     RECT  0.084 15.6 0.133 15.624 ;
     RECT  0.06 15.624 0.133 15.696 ;
     RECT  0.084 15.696 0.133 15.72 ;
     RECT  0.06 15.72 0.133 15.792 ;
     RECT  0.084 15.792 0.133 15.816 ;
     RECT  0.06 15.816 0.133 15.888 ;
     RECT  0.084 15.888 0.133 15.912 ;
     RECT  0.06 15.912 0.133 15.984 ;
     RECT  0.084 15.984 0.133 16.008 ;
     RECT  0.06 16.008 0.133 16.08 ;
     RECT  0.084 16.08 0.133 16.104 ;
     RECT  0.06 16.104 0.133 16.176 ;
     RECT  0.084 16.176 0.133 16.2 ;
     RECT  0.06 16.2 0.133 16.272 ;
     RECT  0.084 16.272 0.133 16.296 ;
     RECT  0.06 16.296 0.133 16.368 ;
     RECT  0.084 16.368 0.133 16.392 ;
     RECT  0.06 16.392 0.133 16.464 ;
     RECT  0.084 16.464 0.133 16.488 ;
     RECT  0.06 16.488 0.133 16.56 ;
     RECT  0.084 16.56 0.133 16.584 ;
     RECT  0.06 16.584 0.133 16.656 ;
     RECT  0.084 16.656 0.133 16.68 ;
     RECT  0.06 16.68 0.133 16.752 ;
     RECT  0.084 16.752 0.133 16.776 ;
     RECT  0.06 16.776 0.133 16.848 ;
     RECT  0.084 16.848 0.133 16.872 ;
     RECT  0.06 16.872 0.133 16.944 ;
     RECT  0.084 16.944 0.133 16.968 ;
     RECT  0.06 16.968 0.133 17.04 ;
     RECT  0.084 17.04 0.133 17.064 ;
     RECT  0.06 17.064 0.133 17.136 ;
     RECT  0.084 17.136 0.133 17.16 ;
     RECT  0.06 17.16 0.133 17.232 ;
     RECT  0.084 17.232 0.133 17.256 ;
     RECT  0.06 17.256 0.133 17.328 ;
     RECT  0.084 17.328 0.133 17.352 ;
     RECT  0.06 17.352 0.133 17.424 ;
     RECT  0.084 17.424 0.133 17.448 ;
     RECT  0.084 19.44 0.133 19.464 ;
     RECT  0.06 19.464 0.133 19.536 ;
     RECT  0.084 19.536 0.133 19.56 ;
     RECT  0.06 19.56 0.133 19.632 ;
     RECT  0.084 19.632 0.133 19.656 ;
     RECT  0.06 19.656 0.133 19.728 ;
     RECT  0.084 19.728 0.133 19.752 ;
     RECT  0.06 19.752 0.133 19.824 ;
     RECT  0.084 19.824 0.133 19.848 ;
     RECT  0.06 19.848 0.133 19.92 ;
     RECT  0.084 19.92 0.133 19.944 ;
     RECT  0.06 19.944 0.133 20.016 ;
     RECT  0.084 20.016 0.133 20.04 ;
     RECT  0.06 20.04 0.133 20.112 ;
     RECT  0.084 20.112 0.133 20.136 ;
     RECT  0.06 20.136 0.133 20.208 ;
     RECT  0.084 20.208 0.133 20.232 ;
     RECT  0.06 20.232 0.133 20.304 ;
     RECT  0.084 20.304 0.133 20.328 ;
     RECT  0.06 20.328 0.133 20.4 ;
     RECT  0.084 20.4 0.133 20.424 ;
     RECT  0.06 20.424 0.133 20.496 ;
     RECT  0.084 20.496 0.133 20.52 ;
     RECT  0.084 22.032 0.133 22.056 ;
     RECT  0.06 22.056 0.133 22.608 ;
     RECT  0.084 22.608 0.133 22.632 ;
     RECT  0.084 23.856 0.133 23.88 ;
     RECT  0.06 23.88 0.133 23.952 ;
     RECT  0.084 23.952 0.133 23.976 ;
     RECT  0.06 23.976 0.133 24.048 ;
     RECT  0.084 24.048 0.133 24.072 ;
     RECT  0.06 24.072 0.133 24.144 ;
     RECT  0.084 24.144 0.133 24.168 ;
     RECT  0.084 25.68 0.133 25.704 ;
     RECT  0.06 25.704 0.133 25.776 ;
     RECT  0.084 25.776 0.133 25.8 ;
     RECT  0.06 25.8 0.133 25.872 ;
     RECT  0.084 25.872 0.133 25.896 ;
     RECT  0.06 25.896 0.133 25.968 ;
     RECT  0.084 25.968 0.133 25.992 ;
     RECT  0.06 25.992 0.133 26.064 ;
     RECT  0.084 26.064 0.133 26.088 ;
     RECT  0.06 26.088 0.133 26.16 ;
     RECT  0.084 26.16 0.133 26.184 ;
     RECT  0.06 26.184 0.133 26.256 ;
     RECT  0.084 26.256 0.133 26.28 ;
     RECT  0.06 26.28 0.133 26.352 ;
     RECT  0.084 26.352 0.133 26.376 ;
     RECT  0.06 26.376 0.133 26.448 ;
     RECT  0.084 26.448 0.133 26.472 ;
     RECT  0.06 26.472 0.133 26.544 ;
     RECT  0.084 26.544 0.133 26.568 ;
     RECT  0.06 26.568 0.133 26.64 ;
     RECT  0.084 26.64 0.133 26.664 ;
     RECT  0.06 26.664 0.133 26.736 ;
     RECT  0.084 26.736 0.133 26.76 ;
     RECT  0.06 26.76 0.133 26.832 ;
     RECT  0.084 26.832 0.133 26.856 ;
     RECT  0.06 26.856 0.133 26.928 ;
     RECT  0.084 26.928 0.133 26.952 ;
     RECT  0.06 26.952 0.133 27.024 ;
     RECT  0.084 27.024 0.133 27.048 ;
     RECT  0.06 27.048 0.133 27.12 ;
     RECT  0.084 27.12 0.133 27.144 ;
     RECT  0.06 27.144 0.133 27.216 ;
     RECT  0.084 27.216 0.133 27.24 ;
     RECT  0.06 27.24 0.133 27.312 ;
     RECT  0.084 27.312 0.133 27.336 ;
     RECT  0.06 27.336 0.133 27.408 ;
     RECT  0.084 27.408 0.133 27.432 ;
     RECT  0.06 27.432 0.133 27.504 ;
     RECT  0.084 27.504 0.133 27.528 ;
     RECT  0.06 27.528 0.133 27.6 ;
     RECT  0.084 27.6 0.133 27.624 ;
     RECT  0.06 27.624 0.133 27.696 ;
     RECT  0.084 27.696 0.133 27.72 ;
     RECT  0.06 27.72 0.133 27.792 ;
     RECT  0.084 27.792 0.133 27.816 ;
     RECT  0.06 27.816 0.133 27.888 ;
     RECT  0.084 27.888 0.133 27.912 ;
     RECT  0.06 27.912 0.133 27.984 ;
     RECT  0.084 27.984 0.133 28.008 ;
     RECT  0.06 28.008 0.133 28.08 ;
     RECT  0.084 28.08 0.133 28.104 ;
     RECT  0.06 28.104 0.133 28.176 ;
     RECT  0.084 28.176 0.133 28.2 ;
     RECT  0.06 28.2 0.133 28.272 ;
     RECT  0.084 28.272 0.133 28.296 ;
     RECT  0.06 28.296 0.133 28.368 ;
     RECT  0.084 28.368 0.133 28.392 ;
     RECT  0.06 28.392 0.133 28.464 ;
     RECT  0.084 28.464 0.133 28.488 ;
     RECT  0.06 28.488 0.133 28.56 ;
     RECT  0.084 28.56 0.133 28.584 ;
     RECT  0.06 28.584 0.133 28.656 ;
     RECT  0.084 28.656 0.133 28.68 ;
     RECT  0.084 2.64 0.179 2.664 ;
     RECT  0.06 2.664 0.179 2.736 ;
     RECT  0.084 2.736 0.179 2.76 ;
     RECT  0.06 2.76 0.179 2.832 ;
     RECT  0.084 2.832 0.179 2.856 ;
     RECT  0.06 2.856 0.179 2.928 ;
     RECT  0.084 2.928 0.179 2.952 ;
     RECT  0.179 2.736 0.181 2.952 ;
     RECT  0.133 14.208 0.181 17.448 ;
     RECT  0.133 22.032 0.181 24.168 ;
     RECT  0.133 25.632 0.181 29.352 ;
     RECT  0.181 2.736 0.227 3.432 ;
     RECT  0.181 13.632 0.229 17.448 ;
     RECT  0.133 19.344 0.229 20.52 ;
     RECT  0.181 21.696 0.229 24.168 ;
     RECT  0.229 13.632 0.277 18.024 ;
     RECT  0.277 13.584 0.517 18.024 ;
     RECT  1.925 1.728 2.225 1.752 ;
     RECT  2.141 40.992 2.245 41.016 ;
     RECT  0.517 12.816 2.252 18.024 ;
     RECT  0.227 2.832 2.257 3.432 ;
     RECT  2.257 2.832 2.293 3.672 ;
     RECT  2.252 12.768 2.293 18.024 ;
     RECT  0.229 19.296 2.293 24.168 ;
     RECT  0.181 25.536 2.293 29.352 ;
     RECT  0.097 30.672 2.293 31.848 ;
     RECT  2.245 40.704 2.341 41.016 ;
     RECT  2.293 2.148 2.408 3.672 ;
     RECT  0.133 5.136 2.408 5.16 ;
     RECT  2.293 12.768 2.408 24.504 ;
     RECT  2.293 25.536 2.408 31.848 ;
     RECT  2.341 40.704 2.408 41.208 ;
     RECT  2.408 2.148 2.427 41.208 ;
     RECT  2.427 2.148 2.512 41.256 ;
     RECT  2.512 2.418 2.585 41.256 ;
     RECT  2.585 2.418 2.704 40.782 ;
     RECT  2.704 2.784 3.277 6.312 ;
     RECT  3.277 3.36 3.491 6.312 ;
     RECT  2.053 0.576 3.557 0.6 ;
     RECT  2.704 9.648 3.587 9.672 ;
     RECT  3.491 3.408 3.731 6.312 ;
     RECT  2.704 11.376 3.841 32.232 ;
     RECT  3.836 9.456 3.877 9.48 ;
     RECT  3.731 3.6 3.923 6.312 ;
     RECT  3.877 8.832 3.923 9.48 ;
     RECT  3.923 3.6 3.953 5.64 ;
     RECT  3.841 11.376 3.973 32.376 ;
     RECT  2.704 33.648 3.973 33.816 ;
     RECT  3.953 4.512 4.019 5.64 ;
     RECT  2.704 39.888 4.129 39.96 ;
     RECT  3.973 11.376 4.261 33.816 ;
     RECT  4.019 4.8 4.307 5.64 ;
     RECT  4.129 39.888 4.307 40.68 ;
     RECT  3.923 8.832 4.313 8.856 ;
     RECT  4.261 10.848 4.453 33.816 ;
     RECT  4.453 10.512 4.597 33.816 ;
     RECT  4.307 40.272 4.643 40.68 ;
     RECT  4.643 40.272 4.709 40.296 ;
     RECT  2.704 37.44 4.741 37.464 ;
     RECT  4.597 10.512 4.789 34.776 ;
     RECT  4.789 9.936 4.835 34.776 ;
     RECT  4.309 7.152 4.921 7.176 ;
     RECT  4.835 34.752 5.027 34.776 ;
     RECT  4.835 9.936 5.069 33.096 ;
     RECT  4.921 6.192 5.073 7.176 ;
     RECT  4.307 4.8 5.173 4.824 ;
     RECT  5.069 12.144 5.213 33.096 ;
     RECT  5.213 33.024 5.267 33.096 ;
     RECT  5.069 9.936 5.329 10.872 ;
     RECT  5.173 4.704 5.353 4.824 ;
     RECT  5.073 6.192 5.353 8.184 ;
     RECT  5.267 33.024 5.573 33.048 ;
     RECT  5.213 12.144 5.692 32.04 ;
     RECT  5.353 4.704 5.749 8.184 ;
     RECT  5.329 9.936 5.749 10.632 ;
     RECT  5.692 12.528 6.005 32.04 ;
     RECT  5.749 4.704 6.113 10.632 ;
     RECT  6.065 1.728 6.14 1.752 ;
     RECT  4.741 36.624 6.181 37.464 ;
     RECT  6.14 1.728 6.253 2.28 ;
     RECT  6.217 0.528 6.323 0.552 ;
     RECT  5.749 35.136 6.373 35.16 ;
     RECT  6.005 12.528 6.419 29.784 ;
     RECT  6.113 4.704 6.541 9.096 ;
     RECT  6.541 4.416 6.563 9.096 ;
     RECT  6.419 13.392 6.563 29.784 ;
     RECT  6.563 4.416 6.689 8.856 ;
     RECT  6.181 36.624 6.709 37.704 ;
     RECT  6.661 38.832 6.709 38.856 ;
     RECT  6.689 4.416 6.721 8.808 ;
     RECT  6.253 1.632 6.757 2.28 ;
     RECT  6.373 34.896 6.901 35.16 ;
     RECT  6.757 1.632 6.949 2.904 ;
     RECT  6.721 4.176 6.949 8.808 ;
     RECT  6.901 34.896 6.976 35.304 ;
     RECT  6.976 34.848 6.997 35.304 ;
     RECT  6.997 33.936 7.045 35.304 ;
     RECT  6.709 36.624 7.045 38.856 ;
     RECT  7.045 36.624 7.117 39.528 ;
     RECT  7.045 33.84 7.153 35.304 ;
     RECT  7.153 33.84 7.189 35.448 ;
     RECT  7.189 33.264 7.261 35.448 ;
     RECT  6.005 30.768 7.297 31.944 ;
     RECT  7.261 33.264 7.297 35.544 ;
     RECT  7.117 36.624 7.297 39.576 ;
     RECT  7.429 43.056 7.477 43.08 ;
     RECT  7.477 42.96 7.505 43.08 ;
     RECT  6.949 1.632 7.525 8.808 ;
     RECT  6.563 13.392 7.525 22.296 ;
     RECT  7.505 42.144 7.525 43.08 ;
     RECT  7.297 30.768 7.549 39.576 ;
     RECT  7.285 40.56 7.549 40.584 ;
     RECT  7.525 42.048 7.667 43.08 ;
     RECT  7.549 30.768 7.669 40.584 ;
     RECT  7.667 42.048 7.669 43.032 ;
     RECT  7.525 1.152 7.697 8.808 ;
     RECT  7.697 1.2 7.805 8.808 ;
     RECT  7.805 1.728 7.808 8.808 ;
     RECT  6.113 10.608 7.808 10.632 ;
     RECT  7.525 12.528 7.808 22.296 ;
     RECT  6.563 23.376 7.808 29.784 ;
     RECT  7.669 30.768 7.808 43.032 ;
     RECT  7.808 1.728 7.985 43.032 ;
     RECT  7.985 2.418 8.104 43.032 ;
     RECT  8.104 25.968 8.165 43.032 ;
     RECT  8.104 10.608 8.243 10.776 ;
     RECT  8.165 42.192 8.243 43.032 ;
     RECT  8.243 10.752 8.339 10.776 ;
     RECT  8.165 25.968 8.339 41.016 ;
     RECT  8.339 34.896 8.381 41.016 ;
     RECT  8.381 35.04 8.531 41.016 ;
     RECT  8.531 35.328 8.561 41.016 ;
     RECT  8.561 35.52 8.627 41.016 ;
     RECT  8.243 42.192 8.819 42.264 ;
     RECT  8.104 11.808 8.963 23.592 ;
     RECT  8.627 35.52 9.107 40.248 ;
     RECT  9.107 36.432 9.217 40.248 ;
     RECT  9.157 2.88 9.245 2.904 ;
     RECT  8.963 11.808 9.349 22.056 ;
     RECT  9.349 42.144 9.413 42.168 ;
     RECT  9.169 1.008 9.521 1.032 ;
     RECT  9.349 11.424 9.539 22.056 ;
     RECT  9.521 1.008 9.604 1.752 ;
     RECT  9.217 36.48 9.641 40.248 ;
     RECT  9.641 36.528 9.701 40.248 ;
     RECT  9.604 1.008 9.721 1.8 ;
     RECT  8.104 4.128 9.749 6.84 ;
     RECT  9.701 36.528 9.785 40.44 ;
     RECT  9.539 11.424 9.821 20.04 ;
     RECT  9.749 4.128 9.827 6.648 ;
     RECT  9.821 15.888 9.827 20.04 ;
     RECT  9.785 36.528 9.827 39.912 ;
     RECT  9.827 4.128 9.857 6.552 ;
     RECT  9.827 15.888 9.875 19.128 ;
     RECT  8.339 25.968 9.923 33.624 ;
     RECT  9.827 36.576 9.929 39.912 ;
     RECT  9.821 11.424 9.965 14.856 ;
     RECT  9.929 36.576 9.965 37.272 ;
     RECT  9.875 15.984 10.019 19.128 ;
     RECT  10.019 15.984 10.037 18.072 ;
     RECT  9.923 25.968 10.067 29.784 ;
     RECT  9.413 41.568 10.069 42.168 ;
     RECT  9.965 36.816 10.108 37.272 ;
     RECT  10.108 36.816 10.109 36.84 ;
     RECT  9.857 4.128 10.115 6.408 ;
     RECT  10.037 16.56 10.115 18.072 ;
     RECT  9.923 30.816 10.153 33.624 ;
     RECT  10.067 29.712 10.163 29.784 ;
     RECT  10.153 30.816 10.163 33.048 ;
     RECT  9.929 38.592 10.163 39.912 ;
     RECT  10.163 30.912 10.181 33.048 ;
     RECT  10.069 41.472 10.189 42.168 ;
     RECT  10.115 5.328 10.211 6.312 ;
     RECT  9.965 11.424 10.259 14.52 ;
     RECT  9.539 21.168 10.259 22.056 ;
     RECT  10.163 38.64 10.289 39.912 ;
     RECT  10.259 11.424 10.325 13.128 ;
     RECT  10.289 38.64 10.325 39.384 ;
     RECT  10.259 14.112 10.355 14.52 ;
     RECT  10.115 16.56 10.361 17.688 ;
     RECT  10.325 38.688 10.397 39.384 ;
     RECT  10.211 5.472 10.403 6.312 ;
     RECT  10.325 11.424 10.403 11.688 ;
     RECT  10.355 14.496 10.403 14.52 ;
     RECT  10.163 29.76 10.403 29.784 ;
     RECT  10.403 11.424 10.429 11.448 ;
     RECT  10.465 3.408 10.549 4.056 ;
     RECT  10.189 42.144 10.549 42.168 ;
     RECT  10.556 41.04 10.643 41.064 ;
     RECT  10.397 39.312 10.649 39.384 ;
     RECT  10.181 31.248 10.685 33.048 ;
     RECT  10.403 5.472 10.765 5.736 ;
     RECT  10.549 42.144 10.834 43.032 ;
     RECT  9.721 1.008 10.861 1.752 ;
     RECT  10.685 32.352 10.945 33.048 ;
     RECT  10.861 0.576 11.005 1.752 ;
     RECT  10.834 42.144 11.027 43.08 ;
     RECT  11.027 42.144 11.075 42.984 ;
     RECT  10.429 10.848 11.123 11.448 ;
     RECT  10.825 40.752 11.123 40.776 ;
     RECT  10.361 17.664 11.189 17.688 ;
     RECT  10.549 3.984 11.219 4.056 ;
     RECT  10.019 19.104 11.257 19.128 ;
     RECT  10.259 21.6 11.269 22.056 ;
     RECT  11.219 4.032 11.315 4.056 ;
     RECT  11.075 42.144 11.317 42.792 ;
     RECT  11.257 18.192 11.341 19.128 ;
     RECT  10.945 32.352 11.377 32.472 ;
     RECT  10.685 31.248 11.393 31.32 ;
     RECT  11.123 10.848 11.411 10.872 ;
     RECT  11.393 30.624 11.477 31.32 ;
     RECT  11.401 5.136 11.507 5.16 ;
     RECT  11.477 30.72 11.513 31.32 ;
     RECT  11.513 31.248 11.555 31.32 ;
     RECT  11.401 6.24 11.699 6.264 ;
     RECT  11.377 32.352 11.699 32.376 ;
     RECT  11.005 0.528 11.795 1.752 ;
     RECT  11.317 42.096 11.795 42.792 ;
     RECT  11.795 1.104 11.987 1.752 ;
     RECT  10.649 39.36 12.083 39.384 ;
     RECT  11.987 1.728 12.089 1.752 ;
     RECT  11.977 5.664 12.179 5.688 ;
     RECT  11.617 40.464 12.179 40.488 ;
     RECT  11.795 42.096 12.229 42.264 ;
     RECT  12.229 41.664 12.275 42.264 ;
     RECT  12.275 41.664 12.284 41.688 ;
     RECT  12.284 41.616 12.467 41.688 ;
     RECT  10.361 16.56 12.62 16.584 ;
     RECT  11.341 19.104 12.661 19.128 ;
     RECT  12.661 18.144 12.985 19.128 ;
     RECT  12.62 16.512 13.208 16.584 ;
     RECT  12.985 18.144 13.208 20.088 ;
     RECT  11.269 21.168 13.208 22.056 ;
     RECT  8.963 23.568 13.208 23.592 ;
     RECT  10.067 25.968 13.208 28.2 ;
     RECT  11.555 31.248 13.208 31.272 ;
     RECT  13.208 2.148 13.312 41.052 ;
     RECT  13.312 2.418 13.504 40.782 ;
     RECT  13.504 21.168 13.601 21.48 ;
     RECT  13.504 18.144 17.197 18.792 ;
     RECT  13.504 20.064 17.317 20.088 ;
     RECT  13.601 21.264 17.317 21.48 ;
     RECT  17.197 17.856 17.389 18.792 ;
     RECT  15.037 16.464 18.608 16.488 ;
     RECT  17.389 17.856 18.608 18.696 ;
     RECT  17.317 20.064 18.608 21.48 ;
     RECT  13.504 23.568 18.608 23.592 ;
     RECT  13.504 25.968 18.608 28.2 ;
     RECT  13.504 31.248 18.608 31.272 ;
     RECT  18.608 2.148 18.712 41.052 ;
     RECT  18.712 2.418 18.904 40.782 ;
     RECT  18.904 19.92 19.379 20.52 ;
     RECT  18.904 18.192 19.957 18.216 ;
     RECT  19.957 18.192 19.973 19.176 ;
     RECT  19.973 19.152 20.044 19.176 ;
     RECT  18.904 23.568 21.349 23.592 ;
     RECT  21.308 22.176 21.395 22.2 ;
     RECT  18.904 25.968 21.557 28.2 ;
     RECT  19.379 20.496 21.881 20.52 ;
     RECT  22.237 19.776 24.008 19.8 ;
     RECT  21.349 23.568 24.008 23.64 ;
     RECT  21.557 25.968 24.008 27.336 ;
     RECT  18.904 31.248 24.008 31.272 ;
     RECT  24.008 2.148 24.112 41.052 ;
     RECT  24.112 2.418 24.304 40.782 ;
     RECT  24.304 25.968 25.861 26.952 ;
     RECT  25.628 32.496 25.873 32.52 ;
     RECT  25.765 37.344 26.053 37.368 ;
     RECT  25.957 30.24 26.237 30.264 ;
     RECT  26.149 40.848 26.245 40.872 ;
     RECT  26.245 40.416 26.341 40.872 ;
     RECT  26.341 40.416 26.425 41.016 ;
     RECT  24.304 31.248 26.533 31.272 ;
     RECT  25.873 32.448 26.629 32.52 ;
     RECT  25.861 25.056 26.633 26.952 ;
     RECT  26.437 28.176 26.737 28.2 ;
     RECT  26.693 43.056 26.737 43.08 ;
     RECT  24.304 19.488 26.773 19.512 ;
     RECT  26.633 25.824 26.773 26.952 ;
     RECT  26.629 32.448 26.773 33.048 ;
     RECT  26.773 19.488 26.813 19.608 ;
     RECT  26.533 30.72 26.813 31.272 ;
     RECT  26.053 37.344 26.821 37.608 ;
     RECT  26.425 40.416 26.917 40.872 ;
     RECT  26.821 37.056 27.065 37.608 ;
     RECT  26.737 28.176 27.109 28.968 ;
     RECT  26.737 43.056 27.301 43.176 ;
     RECT  26.917 39.552 27.388 40.872 ;
     RECT  27.388 39.552 27.493 40.92 ;
     RECT  26.773 32.304 27.709 33.048 ;
     RECT  26.813 30.72 27.853 31.176 ;
     RECT  27.301 42.96 27.973 43.176 ;
     RECT  27.973 42.816 28.261 43.176 ;
     RECT  27.065 37.056 28.361 37.368 ;
     RECT  28.453 38.496 28.645 38.52 ;
     RECT  27.493 39.552 28.645 41.784 ;
     RECT  24.304 23.568 28.837 23.64 ;
     RECT  28.837 22.752 29.029 23.64 ;
     RECT  28.645 38.496 29.077 41.784 ;
     RECT  28.261 42.768 29.077 43.176 ;
     RECT  27.853 30.576 29.221 31.176 ;
     RECT  26.813 19.584 29.408 19.608 ;
     RECT  28.741 20.88 29.408 20.904 ;
     RECT  29.029 22.752 29.408 24.408 ;
     RECT  26.773 25.824 29.408 27.096 ;
     RECT  27.109 28.176 29.408 29.4 ;
     RECT  29.221 30.576 29.408 31.224 ;
     RECT  27.709 32.304 29.408 33.624 ;
     RECT  28.573 36.24 29.408 36.264 ;
     RECT  28.361 37.344 29.408 37.368 ;
     RECT  29.077 38.496 29.408 43.176 ;
     RECT  29.408 2.148 29.512 43.176 ;
     RECT  29.512 2.418 29.704 43.176 ;
     RECT  29.704 38.496 29.801 43.176 ;
     RECT  29.704 20.592 29.873 24.408 ;
     RECT  29.873 20.592 29.987 21.912 ;
     RECT  29.704 30.576 30.017 31.224 ;
     RECT  29.873 22.944 30.629 24.408 ;
     RECT  29.704 25.824 30.629 27.096 ;
     RECT  29.704 37.344 30.853 37.368 ;
     RECT  29.801 38.496 30.853 38.568 ;
     RECT  30.709 18 30.877 18.024 ;
     RECT  29.704 19.104 30.877 19.608 ;
     RECT  30.629 25.872 30.953 27.096 ;
     RECT  30.877 18 30.985 19.608 ;
     RECT  29.987 20.592 31.057 20.712 ;
     RECT  29.987 21.84 31.057 21.912 ;
     RECT  30.629 22.944 31.057 24.072 ;
     RECT  29.704 28.176 31.097 28.968 ;
     RECT  31.097 28.272 31.189 28.968 ;
     RECT  30.017 30.576 31.189 31.176 ;
     RECT  29.704 32.304 31.189 33.624 ;
     RECT  31.189 32.304 31.277 34.584 ;
     RECT  30.985 17.952 31.309 19.608 ;
     RECT  31.057 20.592 31.309 21.912 ;
     RECT  31.189 28.272 31.417 31.176 ;
     RECT  31.057 22.896 31.813 24.072 ;
     RECT  31.309 17.952 31.957 21.912 ;
     RECT  31.813 22.896 31.957 24.792 ;
     RECT  31.957 17.952 32.053 24.792 ;
     RECT  32.053 17.136 32.397 24.792 ;
     RECT  30.953 25.872 32.397 26.664 ;
     RECT  31.417 28.272 32.425 31.992 ;
     RECT  31.277 32.976 32.425 34.584 ;
     RECT  32.397 17.136 32.437 26.664 ;
     RECT  32.425 28.272 32.645 34.584 ;
     RECT  32.437 17.136 32.677 27.24 ;
     RECT  32.677 16.368 32.713 27.24 ;
     RECT  32.645 28.272 32.713 33.192 ;
     RECT  32.713 16.368 32.869 33.192 ;
     RECT  29.704 36.24 32.917 36.264 ;
     RECT  32.485 0.096 32.929 0.12 ;
     RECT  32.645 34.464 33.013 34.584 ;
     RECT  32.293 9.12 33.041 9.144 ;
     RECT  33.013 34.464 33.073 35.016 ;
     RECT  32.917 36.24 33.157 36.312 ;
     RECT  30.853 37.344 33.157 38.568 ;
     RECT  32.929 0.096 33.436 0.84 ;
     RECT  33.217 9.648 33.491 9.672 ;
     RECT  33.436 0.048 33.605 0.84 ;
     RECT  33.253 11.424 33.689 11.448 ;
     RECT  33.157 36.24 33.829 38.568 ;
     RECT  29.801 39.552 33.829 43.176 ;
     RECT  33.073 34.464 33.865 35.208 ;
     RECT  33.829 36.24 33.865 43.176 ;
     RECT  33.865 11.952 33.925 11.976 ;
     RECT  33.157 13.104 33.925 13.128 ;
     RECT  33.865 34.464 34.037 43.176 ;
     RECT  32.869 15.408 34.069 33.192 ;
     RECT  34.069 14.688 34.117 33.192 ;
     RECT  34.037 34.224 34.117 43.176 ;
     RECT  34.309 10.848 34.693 10.872 ;
     RECT  33.925 11.952 34.693 13.128 ;
     RECT  33.605 0.048 34.789 1.752 ;
     RECT  34.789 0.048 34.808 1.8 ;
     RECT  34.501 3.648 34.808 3.672 ;
     RECT  33.733 5.232 34.808 5.256 ;
     RECT  34.693 10.848 34.808 13.128 ;
     RECT  34.117 14.688 34.808 43.176 ;
     RECT  34.808 0.048 35.104 43.176 ;
     RECT  35.104 15.936 35.363 43.176 ;
     RECT  35.104 11.376 35.555 13.56 ;
     RECT  35.104 0.048 35.705 1.992 ;
     RECT  35.363 16.368 36.325 43.176 ;
     RECT  35.104 14.688 36.757 14.952 ;
     RECT  35.705 1.968 36.817 1.992 ;
     RECT  35.104 3.648 36.817 3.672 ;
     RECT  36.757 14.544 36.889 14.952 ;
     RECT  36.325 15.984 36.889 43.176 ;
     RECT  35.555 11.952 37.033 13.56 ;
     RECT  36.889 14.544 37.033 43.176 ;
     RECT  37.033 11.952 37.333 43.176 ;
     RECT  37.333 11.28 37.429 43.176 ;
     RECT  35.705 0.048 37.669 0.84 ;
     RECT  36.817 1.968 37.669 3.672 ;
     RECT  37.669 0.048 39.809 3.672 ;
     RECT  39.809 0.096 40.208 3.672 ;
     RECT  35.104 5.232 40.208 5.256 ;
     RECT  38.077 7.104 40.208 7.128 ;
     RECT  39.625 9.504 40.208 9.528 ;
     RECT  37.429 11.184 40.208 43.176 ;
     RECT  40.208 0.096 40.504 43.176 ;
     RECT  40.504 0.096 40.885 3.672 ;
     RECT  40.504 5.232 41.569 5.256 ;
     RECT  40.504 7.104 41.569 7.128 ;
     RECT  40.504 11.184 41.717 43.176 ;
     RECT  41.569 5.232 41.891 7.128 ;
     RECT  41.717 14.4 43.193 43.176 ;
     RECT  41.891 5.232 43.333 6.024 ;
     RECT  41.891 7.104 43.333 7.128 ;
     RECT  40.885 0.048 43.945 3.672 ;
     RECT  43.945 0.048 44.197 3.72 ;
     RECT  41.717 11.184 44.197 13.368 ;
     RECT  44.197 10.656 44.629 13.368 ;
     RECT  43.193 14.496 44.629 43.176 ;
     RECT  40.504 9.36 44.917 9.528 ;
     RECT  44.629 10.656 44.917 43.176 ;
     RECT  44.197 0.048 45.608 4.008 ;
     RECT  43.333 5.232 45.608 7.128 ;
     RECT  44.917 9.36 45.608 43.176 ;
     RECT  45.608 0.048 45.904 43.176 ;
     RECT  45.904 14.64 46.403 43.176 ;
     RECT  45.904 5.472 46.865 6.024 ;
     RECT  45.904 0.048 47.257 3.96 ;
     RECT  46.865 6 47.461 6.024 ;
     RECT  45.904 7.104 47.461 7.128 ;
     RECT  45.904 9.36 47.519 13.608 ;
     RECT  46.403 14.64 47.519 43.128 ;
     RECT  47.519 9.36 47.581 43.128 ;
     RECT  47.257 0.048 47.603 4.296 ;
     RECT  47.461 6 47.987 7.128 ;
     RECT  47.581 9.36 48.275 43.176 ;
     RECT  47.987 6.528 48.445 7.128 ;
     RECT  47.603 0.048 49.093 3.72 ;
     RECT  48.275 9.36 49.237 10.824 ;
     RECT  48.445 6.528 49.285 7.416 ;
     RECT  49.237 9.36 49.34 10.872 ;
     RECT  49.34 9.36 49.381 11.16 ;
     RECT  49.381 9.264 49.484 11.16 ;
     RECT  48.275 12.24 49.484 43.176 ;
     RECT  49.484 9.264 49.673 43.176 ;
     RECT  49.285 6.528 50.713 6.552 ;
     RECT  49.093 0.048 51.008 4.68 ;
     RECT  50.713 6.528 51.008 6.648 ;
     RECT  49.673 9.264 51.008 10.104 ;
     RECT  49.673 11.136 51.008 43.176 ;
     RECT  51.008 0.048 51.304 43.176 ;
     RECT  51.304 11.136 51.443 43.176 ;
     RECT  51.304 0.048 51.725 5.112 ;
     RECT  51.725 0.048 52.307 3.72 ;
     RECT  51.304 8.544 52.643 10.104 ;
     RECT  51.725 5.088 52.787 5.112 ;
     RECT  51.443 11.136 52.787 43.08 ;
     RECT  52.787 11.136 53.171 37.416 ;
     RECT  51.304 6.624 53.221 6.648 ;
     RECT  52.643 8.544 53.221 8.568 ;
     RECT  53.221 6.624 53.309 8.568 ;
     RECT  53.309 7.968 53.417 8.568 ;
     RECT  52.307 0.048 53.461 3.432 ;
     RECT  53.171 11.376 53.525 37.416 ;
     RECT  53.461 0.048 53.548 3.96 ;
     RECT  52.787 38.448 53.561 43.08 ;
     RECT  53.309 6.624 53.651 6.648 ;
     RECT  52.643 10.08 53.765 10.104 ;
     RECT  53.548 0.048 53.813 3.336 ;
     RECT  53.765 9.696 53.849 10.104 ;
     RECT  53.849 10.08 53.909 10.104 ;
     RECT  53.909 10.08 53.993 10.248 ;
     RECT  53.561 38.448 54.131 42.024 ;
     RECT  54.131 39.504 54.137 42.024 ;
     RECT  53.417 8.544 54.209 8.568 ;
     RECT  53.813 2.256 54.371 3.336 ;
     RECT  53.525 12.336 54.601 37.416 ;
     RECT  54.131 38.448 54.601 38.52 ;
     RECT  54.371 2.592 54.637 3.336 ;
     RECT  54.469 6.816 54.659 6.84 ;
     RECT  54.601 12.336 54.707 38.52 ;
     RECT  54.707 12.336 55.073 37.416 ;
     RECT  53.813 0.048 55.141 1.128 ;
     RECT  53.561 43.056 55.325 43.08 ;
     RECT  55.141 0.048 55.571 1.176 ;
     RECT  54.637 2.592 55.645 3.432 ;
     RECT  55.571 0.048 55.649 0.936 ;
     RECT  54.137 39.504 55.721 41.928 ;
     RECT  55.073 13.536 55.789 37.416 ;
     RECT  54.707 38.496 55.789 38.52 ;
     RECT  53.993 10.08 55.897 10.104 ;
     RECT  55.789 13.536 56.149 38.52 ;
     RECT  55.721 39.504 56.149 41.88 ;
     RECT  55.649 0.048 56.195 0.6 ;
     RECT  56.195 0.048 56.339 0.504 ;
     RECT  56.149 13.536 56.405 41.88 ;
     RECT  55.645 2.016 56.408 3.432 ;
     RECT  54.385 8.976 56.408 9 ;
     RECT  55.897 10.08 56.408 10.248 ;
     RECT  55.073 12.336 56.408 12.36 ;
     RECT  56.405 13.536 56.408 41.052 ;
     RECT  56.408 2.016 56.512 41.052 ;
     RECT  56.339 0.048 56.531 0.408 ;
     RECT  56.512 2.016 56.627 40.968 ;
     RECT  56.627 2.418 56.704 40.968 ;
     RECT  56.531 0.048 56.819 0.36 ;
     RECT  56.704 13.104 56.845 37.128 ;
     RECT  56.704 8.976 56.867 9 ;
     RECT  56.704 38.736 56.909 40.968 ;
     RECT  56.704 10.224 56.953 10.248 ;
     RECT  56.909 38.736 56.963 40.728 ;
     RECT  56.819 0.048 57.053 0.312 ;
     RECT  56.963 39.36 57.059 40.728 ;
     RECT  56.845 13.584 57.197 37.128 ;
     RECT  57.197 13.584 57.251 37.032 ;
     RECT  57.251 13.584 57.341 36.888 ;
     RECT  57.053 0.096 57.395 0.312 ;
     RECT  56.704 2.592 57.485 3.144 ;
     RECT  57.059 39.36 57.601 40.68 ;
     RECT  57.395 0.096 57.683 0.12 ;
     RECT  57.601 40.128 57.845 40.68 ;
     RECT  57.845 40.128 58.211 40.584 ;
     RECT  57.485 2.592 58.421 2.616 ;
     RECT  58.211 40.56 58.931 40.584 ;
     RECT  57.341 13.584 59.123 36.84 ;
     RECT  59.123 14.688 60.181 36.84 ;
     RECT  60.181 14.688 60.265 37.08 ;
     RECT  59.123 13.584 60.901 13.608 ;
     RECT  60.265 14.688 61.765 36.84 ;
     RECT  61.585 38.256 61.765 38.28 ;
     RECT  60.901 13.296 61.808 13.608 ;
     RECT  61.765 14.688 61.808 38.28 ;
     RECT  61.808 2.148 61.912 41.052 ;
     RECT  61.912 2.418 62.104 40.782 ;
     RECT  62.104 13.296 62.741 38.28 ;
     RECT  62.741 20.208 63.277 38.28 ;
     RECT  62.741 13.296 63.817 19.08 ;
     RECT  63.277 20.208 63.817 38.472 ;
     RECT  63.817 13.296 63.961 38.472 ;
     RECT  63.961 13.296 64.716 13.32 ;
     RECT  63.961 13.32 64.764 13.392 ;
     RECT  63.961 13.392 64.716 13.416 ;
     RECT  63.961 13.416 64.764 13.488 ;
     RECT  63.961 13.488 64.716 13.512 ;
     RECT  63.961 13.512 64.764 13.584 ;
     RECT  63.961 13.584 64.716 13.608 ;
     RECT  63.961 13.608 64.764 13.68 ;
     RECT  63.961 13.68 64.716 13.704 ;
     RECT  63.961 13.704 64.764 13.776 ;
     RECT  63.961 13.776 64.716 13.8 ;
     RECT  63.961 13.8 64.764 13.872 ;
     RECT  63.961 13.872 64.716 13.896 ;
     RECT  63.961 13.896 64.764 13.968 ;
     RECT  63.961 13.968 64.716 13.992 ;
     RECT  63.961 13.992 64.764 14.064 ;
     RECT  63.961 14.064 64.716 14.088 ;
     RECT  63.961 14.088 64.764 14.16 ;
     RECT  63.961 14.16 64.716 14.184 ;
     RECT  63.961 14.184 64.764 14.256 ;
     RECT  63.961 14.256 64.716 14.28 ;
     RECT  63.961 14.28 64.764 14.352 ;
     RECT  63.961 14.352 64.716 14.376 ;
     RECT  63.961 14.376 64.764 14.448 ;
     RECT  63.961 14.448 64.716 14.472 ;
     RECT  63.961 14.472 64.764 14.544 ;
     RECT  63.961 14.544 64.716 14.568 ;
     RECT  63.961 14.568 64.764 14.64 ;
     RECT  63.961 14.64 64.716 14.664 ;
     RECT  63.961 14.664 64.764 14.736 ;
     RECT  63.961 14.736 64.716 14.76 ;
     RECT  63.961 14.76 64.764 14.832 ;
     RECT  63.961 14.832 64.716 14.856 ;
     RECT  63.961 14.856 64.764 14.928 ;
     RECT  63.961 14.928 64.716 14.952 ;
     RECT  63.961 14.952 64.764 15.024 ;
     RECT  63.961 15.024 64.716 15.048 ;
     RECT  63.961 15.048 64.764 15.12 ;
     RECT  63.961 15.12 64.716 15.144 ;
     RECT  63.961 15.144 64.764 15.216 ;
     RECT  63.961 15.216 64.716 15.24 ;
     RECT  63.961 15.24 64.764 15.312 ;
     RECT  63.961 15.312 64.716 15.336 ;
     RECT  63.961 15.336 64.764 15.408 ;
     RECT  63.961 15.408 64.716 15.432 ;
     RECT  63.961 15.432 64.764 15.504 ;
     RECT  63.961 15.504 64.716 15.528 ;
     RECT  63.961 15.528 64.764 15.6 ;
     RECT  63.961 15.6 64.716 15.624 ;
     RECT  63.961 15.624 64.764 15.696 ;
     RECT  63.961 15.696 64.716 15.72 ;
     RECT  63.961 15.72 64.764 15.792 ;
     RECT  63.961 15.792 64.716 15.816 ;
     RECT  63.961 15.816 64.764 15.888 ;
     RECT  63.961 15.888 64.716 15.912 ;
     RECT  63.961 15.912 64.764 15.984 ;
     RECT  63.961 15.984 64.716 16.008 ;
     RECT  63.961 16.008 64.764 16.08 ;
     RECT  63.961 16.08 64.716 16.104 ;
     RECT  63.961 16.104 64.764 16.176 ;
     RECT  63.961 16.176 64.716 16.2 ;
     RECT  63.961 16.2 64.764 16.272 ;
     RECT  63.961 16.272 64.716 16.296 ;
     RECT  63.961 16.296 64.764 16.368 ;
     RECT  63.961 16.368 64.716 16.392 ;
     RECT  63.961 16.392 64.764 16.464 ;
     RECT  63.961 16.464 64.716 16.488 ;
     RECT  63.961 16.488 64.764 16.56 ;
     RECT  63.961 16.56 64.716 16.584 ;
     RECT  63.961 16.584 64.764 16.656 ;
     RECT  63.961 16.656 64.716 16.68 ;
     RECT  63.961 16.68 64.764 16.752 ;
     RECT  63.961 16.752 64.716 16.776 ;
     RECT  63.961 16.776 64.764 16.848 ;
     RECT  63.961 16.848 64.716 16.872 ;
     RECT  63.961 16.872 64.764 16.944 ;
     RECT  63.961 16.944 64.716 16.968 ;
     RECT  63.961 16.968 64.764 17.04 ;
     RECT  63.961 17.04 64.716 17.064 ;
     RECT  63.961 17.064 64.764 17.136 ;
     RECT  63.961 17.136 64.716 17.16 ;
     RECT  63.961 17.16 64.764 17.232 ;
     RECT  63.961 17.232 64.716 17.256 ;
     RECT  63.961 17.256 64.764 17.328 ;
     RECT  63.961 17.328 64.716 17.352 ;
     RECT  63.961 17.352 64.764 17.424 ;
     RECT  63.961 17.424 64.716 17.448 ;
     RECT  63.961 17.448 64.764 17.52 ;
     RECT  63.961 17.52 64.716 17.544 ;
     RECT  63.961 17.544 64.764 17.616 ;
     RECT  63.961 17.616 64.716 17.64 ;
     RECT  63.961 17.64 64.764 17.712 ;
     RECT  63.961 17.712 64.716 17.736 ;
     RECT  63.961 17.736 64.764 17.808 ;
     RECT  63.961 17.808 64.716 17.832 ;
     RECT  63.961 17.832 64.764 17.904 ;
     RECT  63.961 17.904 64.716 17.928 ;
     RECT  63.961 17.928 64.764 18 ;
     RECT  63.961 18 64.716 18.024 ;
     RECT  63.961 18.024 64.764 18.096 ;
     RECT  63.961 18.096 64.716 18.12 ;
     RECT  63.961 18.12 64.764 18.192 ;
     RECT  63.961 18.192 64.716 18.216 ;
     RECT  63.961 18.216 64.764 18.288 ;
     RECT  63.961 18.288 64.716 18.312 ;
     RECT  63.961 18.312 64.764 18.384 ;
     RECT  63.961 18.384 64.716 18.408 ;
     RECT  63.961 18.408 64.764 18.48 ;
     RECT  63.961 18.48 64.716 18.504 ;
     RECT  63.961 18.504 64.764 18.576 ;
     RECT  63.961 18.576 64.716 18.6 ;
     RECT  63.961 18.6 64.764 18.672 ;
     RECT  63.961 18.672 64.716 18.696 ;
     RECT  63.961 18.696 64.764 18.768 ;
     RECT  63.961 18.768 64.716 18.792 ;
     RECT  63.961 18.792 64.764 18.864 ;
     RECT  63.961 18.864 64.716 18.888 ;
     RECT  63.961 18.888 64.764 18.96 ;
     RECT  63.961 18.96 64.716 18.984 ;
     RECT  63.961 18.984 64.764 19.056 ;
     RECT  63.961 19.056 64.716 19.08 ;
     RECT  63.961 19.08 64.764 19.152 ;
     RECT  63.961 19.152 64.716 19.176 ;
     RECT  63.961 19.176 64.764 19.248 ;
     RECT  63.961 19.248 64.716 19.272 ;
     RECT  63.961 19.272 64.764 19.344 ;
     RECT  63.961 19.344 64.716 19.368 ;
     RECT  63.961 19.368 64.764 20.208 ;
     RECT  63.961 20.208 64.716 20.232 ;
     RECT  63.961 20.232 64.764 20.304 ;
     RECT  63.961 20.304 64.716 20.328 ;
     RECT  63.961 20.328 64.764 20.4 ;
     RECT  63.961 20.4 64.716 20.424 ;
     RECT  63.961 20.424 64.764 20.496 ;
     RECT  63.961 20.496 64.716 20.52 ;
     RECT  63.961 20.52 64.764 20.592 ;
     RECT  63.961 20.592 64.716 20.616 ;
     RECT  63.961 20.616 64.764 20.688 ;
     RECT  63.961 20.688 64.716 20.712 ;
     RECT  63.961 20.712 64.764 20.784 ;
     RECT  63.961 20.784 64.716 20.808 ;
     RECT  63.961 20.808 64.764 20.88 ;
     RECT  63.961 20.88 64.716 20.904 ;
     RECT  63.961 20.904 64.764 20.976 ;
     RECT  63.961 20.976 64.716 21 ;
     RECT  63.961 21 64.764 21.072 ;
     RECT  63.961 21.072 64.716 21.096 ;
     RECT  63.961 21.096 64.764 21.168 ;
     RECT  63.961 21.168 64.716 21.192 ;
     RECT  63.961 21.192 64.764 21.264 ;
     RECT  63.961 21.264 64.716 21.288 ;
     RECT  63.961 21.288 64.764 21.36 ;
     RECT  63.961 21.36 64.716 21.384 ;
     RECT  63.961 21.384 64.764 21.456 ;
     RECT  63.961 21.456 64.716 21.48 ;
     RECT  63.961 21.48 64.764 21.552 ;
     RECT  63.961 21.552 64.716 21.576 ;
     RECT  63.961 21.576 64.764 21.648 ;
     RECT  63.961 21.648 64.716 21.672 ;
     RECT  63.961 21.672 64.764 21.744 ;
     RECT  63.961 21.744 64.716 21.768 ;
     RECT  63.961 21.768 64.764 21.84 ;
     RECT  63.961 21.84 64.716 21.864 ;
     RECT  63.961 21.864 64.764 21.936 ;
     RECT  63.961 21.936 64.716 21.96 ;
     RECT  63.961 21.96 64.764 22.032 ;
     RECT  63.961 22.032 64.716 22.056 ;
     RECT  63.961 22.056 64.764 22.128 ;
     RECT  63.961 22.128 64.716 22.152 ;
     RECT  63.961 22.152 64.764 22.224 ;
     RECT  63.961 22.224 64.716 22.248 ;
     RECT  63.961 22.248 64.764 22.32 ;
     RECT  63.961 22.32 64.716 22.344 ;
     RECT  63.961 22.344 64.764 22.416 ;
     RECT  63.961 22.416 64.716 22.44 ;
     RECT  63.961 22.44 64.764 22.512 ;
     RECT  63.961 22.512 64.716 22.536 ;
     RECT  63.961 22.536 64.764 22.608 ;
     RECT  63.961 22.608 64.716 22.632 ;
     RECT  63.961 22.632 64.764 22.704 ;
     RECT  63.961 22.704 64.716 22.728 ;
     RECT  63.961 22.728 64.764 22.8 ;
     RECT  63.961 22.8 64.716 22.824 ;
     RECT  63.961 22.824 64.764 22.896 ;
     RECT  63.961 22.896 64.716 22.92 ;
     RECT  63.961 22.92 64.764 22.992 ;
     RECT  63.961 22.992 64.716 23.016 ;
     RECT  63.961 23.016 64.764 23.088 ;
     RECT  63.961 23.088 64.716 23.112 ;
     RECT  63.961 23.112 64.764 23.184 ;
     RECT  63.961 23.184 64.716 23.208 ;
     RECT  63.961 23.208 64.764 23.28 ;
     RECT  63.961 23.28 64.716 23.304 ;
     RECT  63.961 23.304 64.764 23.376 ;
     RECT  63.961 23.376 64.716 23.4 ;
     RECT  63.961 23.4 64.764 23.472 ;
     RECT  63.961 23.472 64.716 23.496 ;
     RECT  63.961 23.496 64.764 23.568 ;
     RECT  63.961 23.568 64.716 23.592 ;
     RECT  63.961 23.592 64.764 23.664 ;
     RECT  63.961 23.664 64.716 23.688 ;
     RECT  63.961 23.688 64.764 23.76 ;
     RECT  63.961 23.76 64.716 23.784 ;
     RECT  63.961 23.784 64.764 23.856 ;
     RECT  63.961 23.856 64.716 23.88 ;
     RECT  63.961 23.88 64.764 23.952 ;
     RECT  63.961 23.952 64.716 23.976 ;
     RECT  63.961 23.976 64.764 24.048 ;
     RECT  63.961 24.048 64.716 24.072 ;
     RECT  63.961 24.072 64.764 24.144 ;
     RECT  63.961 24.144 64.716 24.168 ;
     RECT  63.961 24.168 64.764 24.24 ;
     RECT  63.961 24.24 64.716 24.264 ;
     RECT  63.961 24.264 64.764 24.336 ;
     RECT  63.961 24.336 64.716 24.36 ;
     RECT  63.961 24.36 64.764 24.432 ;
     RECT  63.961 24.432 64.716 24.456 ;
     RECT  63.961 24.456 64.764 24.528 ;
     RECT  63.961 24.528 64.716 24.552 ;
     RECT  63.961 24.552 64.764 24.624 ;
     RECT  63.961 24.624 64.716 24.648 ;
     RECT  63.961 24.648 64.764 24.72 ;
     RECT  63.961 24.72 64.716 24.744 ;
     RECT  63.961 24.744 64.764 24.816 ;
     RECT  63.961 24.816 64.716 24.84 ;
     RECT  63.961 24.84 64.764 24.912 ;
     RECT  63.961 24.912 64.716 24.936 ;
     RECT  63.961 24.936 64.764 25.008 ;
     RECT  63.961 25.008 64.716 25.032 ;
     RECT  63.961 25.032 64.764 25.104 ;
     RECT  63.961 25.104 64.716 25.128 ;
     RECT  63.961 25.128 64.764 25.2 ;
     RECT  63.961 25.2 64.716 25.224 ;
     RECT  63.961 25.224 64.764 25.296 ;
     RECT  63.961 25.296 64.716 25.32 ;
     RECT  63.961 25.32 64.764 25.392 ;
     RECT  63.961 25.392 64.716 25.416 ;
     RECT  63.961 25.416 64.764 25.488 ;
     RECT  63.961 25.488 64.716 25.512 ;
     RECT  63.961 25.512 64.764 25.584 ;
     RECT  63.961 25.584 64.716 25.608 ;
     RECT  63.961 25.608 64.764 25.68 ;
     RECT  63.961 25.68 64.716 25.704 ;
     RECT  63.961 25.704 64.764 25.776 ;
     RECT  63.961 25.776 64.716 25.8 ;
     RECT  63.961 25.8 64.764 25.872 ;
     RECT  63.961 25.872 64.716 25.896 ;
     RECT  63.961 25.896 64.764 25.968 ;
     RECT  63.961 25.968 64.716 25.992 ;
     RECT  63.961 25.992 64.764 26.064 ;
     RECT  63.961 26.064 64.716 26.088 ;
     RECT  63.961 26.088 64.764 26.16 ;
     RECT  63.961 26.16 64.716 26.184 ;
     RECT  63.961 26.184 64.764 26.256 ;
     RECT  63.961 26.256 64.716 26.28 ;
     RECT  63.961 26.28 64.764 26.352 ;
     RECT  63.961 26.352 64.716 26.376 ;
     RECT  63.961 26.376 64.764 26.448 ;
     RECT  63.961 26.448 64.716 26.472 ;
     RECT  63.961 26.472 64.764 26.544 ;
     RECT  63.961 26.544 64.716 26.568 ;
     RECT  63.961 26.568 64.764 26.64 ;
     RECT  63.961 26.64 64.716 26.664 ;
     RECT  63.961 26.664 64.764 26.736 ;
     RECT  63.961 26.736 64.716 26.76 ;
     RECT  63.961 26.76 64.764 26.832 ;
     RECT  63.961 26.832 64.716 26.856 ;
     RECT  63.961 26.856 64.764 26.928 ;
     RECT  63.961 26.928 64.716 26.952 ;
     RECT  63.961 26.952 64.764 27.024 ;
     RECT  63.961 27.024 64.716 27.048 ;
     RECT  63.961 27.048 64.764 27.12 ;
     RECT  63.961 27.12 64.716 27.144 ;
     RECT  63.961 27.144 64.764 27.216 ;
     RECT  63.961 27.216 64.716 27.24 ;
     RECT  63.961 27.24 64.764 27.312 ;
     RECT  63.961 27.312 64.716 27.336 ;
     RECT  63.961 27.336 64.764 27.408 ;
     RECT  63.961 27.408 64.716 27.432 ;
     RECT  63.961 27.432 64.764 27.504 ;
     RECT  63.961 27.504 64.716 27.528 ;
     RECT  63.961 27.528 64.764 27.6 ;
     RECT  63.961 27.6 64.716 27.624 ;
     RECT  63.961 27.624 64.764 27.696 ;
     RECT  63.961 27.696 64.716 27.72 ;
     RECT  63.961 27.72 64.764 27.792 ;
     RECT  63.961 27.792 64.716 27.816 ;
     RECT  63.961 27.816 64.764 27.888 ;
     RECT  63.961 27.888 64.716 27.912 ;
     RECT  63.961 27.912 64.764 27.984 ;
     RECT  63.961 27.984 64.716 28.008 ;
     RECT  63.961 28.008 64.764 28.08 ;
     RECT  63.961 28.08 64.716 28.104 ;
     RECT  63.961 28.104 64.764 28.176 ;
     RECT  63.961 28.176 64.716 28.2 ;
     RECT  63.961 28.2 64.764 28.272 ;
     RECT  63.961 28.272 64.716 28.296 ;
     RECT  63.961 28.296 64.764 28.368 ;
     RECT  63.961 28.368 64.716 28.392 ;
     RECT  63.961 28.392 64.764 28.464 ;
     RECT  63.961 28.464 64.716 28.488 ;
     RECT  63.961 28.488 64.764 28.56 ;
     RECT  63.961 28.56 64.716 28.584 ;
     RECT  63.961 28.584 64.764 28.656 ;
     RECT  63.961 28.656 64.716 28.68 ;
     RECT  63.961 28.68 64.764 28.752 ;
     RECT  63.961 28.752 64.716 28.776 ;
     RECT  63.961 28.776 64.764 28.848 ;
     RECT  63.961 28.848 64.716 28.872 ;
     RECT  63.961 28.872 64.764 28.944 ;
     RECT  63.961 28.944 64.716 28.968 ;
     RECT  63.961 28.968 64.764 29.04 ;
     RECT  63.961 29.04 64.716 29.064 ;
     RECT  63.961 29.064 64.764 29.136 ;
     RECT  63.961 29.136 64.716 29.16 ;
     RECT  63.961 29.16 64.764 29.232 ;
     RECT  63.961 29.232 64.716 29.256 ;
     RECT  63.961 29.256 64.764 29.328 ;
     RECT  63.961 29.328 64.716 29.352 ;
     RECT  63.961 29.352 64.764 29.424 ;
     RECT  63.961 29.424 64.716 29.448 ;
     RECT  63.961 29.448 64.764 29.52 ;
     RECT  63.961 29.52 64.716 29.544 ;
     RECT  63.961 29.544 64.764 29.616 ;
     RECT  63.961 29.616 64.716 29.64 ;
     RECT  63.961 29.64 64.764 29.712 ;
     RECT  63.961 29.712 64.716 29.736 ;
     RECT  63.961 29.736 64.764 29.808 ;
     RECT  63.961 29.808 64.716 29.832 ;
     RECT  63.961 29.832 64.764 29.904 ;
     RECT  63.961 29.904 64.716 29.928 ;
     RECT  63.961 29.928 64.764 30 ;
     RECT  63.961 30 64.716 30.024 ;
     RECT  63.961 30.024 64.764 30.096 ;
     RECT  63.961 30.096 64.716 30.12 ;
     RECT  63.961 30.12 64.764 30.192 ;
     RECT  63.961 30.192 64.716 30.216 ;
     RECT  63.961 30.216 64.764 30.288 ;
     RECT  63.961 30.288 64.716 30.312 ;
     RECT  63.961 30.312 64.764 30.384 ;
     RECT  63.961 30.384 64.716 30.408 ;
     RECT  63.961 30.408 64.764 30.48 ;
     RECT  63.961 30.48 64.716 30.504 ;
     RECT  63.961 30.504 64.764 30.576 ;
     RECT  63.961 30.576 64.716 30.6 ;
     RECT  63.961 30.6 64.764 30.672 ;
     RECT  63.961 30.672 64.716 30.696 ;
     RECT  63.961 30.696 64.764 30.768 ;
     RECT  63.961 30.768 64.716 30.792 ;
     RECT  63.961 30.792 64.764 30.864 ;
     RECT  63.961 30.864 64.716 30.888 ;
     RECT  63.961 30.888 64.764 30.96 ;
     RECT  63.961 30.96 64.716 30.984 ;
     RECT  63.961 30.984 64.764 31.056 ;
     RECT  63.961 31.056 64.716 31.08 ;
     RECT  63.961 31.08 64.764 31.152 ;
     RECT  63.961 31.152 64.716 31.176 ;
     RECT  63.961 31.176 64.764 31.248 ;
     RECT  63.961 31.248 64.716 31.272 ;
     RECT  63.961 31.272 64.764 31.344 ;
     RECT  63.961 31.344 64.716 31.368 ;
     RECT  63.961 31.368 64.764 31.44 ;
     RECT  63.961 31.44 64.716 31.464 ;
     RECT  63.961 31.464 64.764 31.536 ;
     RECT  63.961 31.536 64.716 31.56 ;
     RECT  63.961 31.56 64.764 31.632 ;
     RECT  63.961 31.632 64.716 31.656 ;
     RECT  63.961 31.656 64.764 31.728 ;
     RECT  63.961 31.728 64.716 31.752 ;
     RECT  63.961 31.752 64.764 31.824 ;
     RECT  63.961 31.824 64.716 31.848 ;
     RECT  63.961 31.848 64.764 31.92 ;
     RECT  63.961 31.92 64.716 31.944 ;
     RECT  63.961 31.944 64.764 32.016 ;
     RECT  63.961 32.016 64.716 32.04 ;
     RECT  63.961 32.04 64.764 32.112 ;
     RECT  63.961 32.112 64.716 32.136 ;
     RECT  63.961 32.136 64.764 32.208 ;
     RECT  63.961 32.208 64.716 32.232 ;
     RECT  63.961 32.232 64.764 32.304 ;
     RECT  63.961 32.304 64.716 32.328 ;
     RECT  63.961 32.328 64.764 32.4 ;
     RECT  63.961 32.4 64.716 32.424 ;
     RECT  63.961 32.424 64.764 32.496 ;
     RECT  63.961 32.496 64.716 32.52 ;
     RECT  63.961 32.52 64.764 32.592 ;
     RECT  63.961 32.592 64.716 32.616 ;
     RECT  63.961 32.616 64.764 32.688 ;
     RECT  63.961 32.688 64.716 32.712 ;
     RECT  63.961 32.712 64.764 32.784 ;
     RECT  63.961 32.784 64.716 32.808 ;
     RECT  63.961 32.808 64.764 32.88 ;
     RECT  63.961 32.88 64.716 32.904 ;
     RECT  63.961 32.904 64.764 32.976 ;
     RECT  63.961 32.976 64.716 33 ;
     RECT  63.961 33 64.764 33.072 ;
     RECT  63.961 33.072 64.716 33.096 ;
     RECT  63.961 33.096 64.764 33.168 ;
     RECT  63.961 33.168 64.716 33.192 ;
     RECT  63.961 33.192 64.764 33.264 ;
     RECT  63.961 33.264 64.716 33.288 ;
     RECT  63.961 33.288 64.764 33.36 ;
     RECT  63.961 33.36 64.716 33.384 ;
     RECT  63.961 33.384 64.764 33.456 ;
     RECT  63.961 33.456 64.716 33.48 ;
     RECT  63.961 33.48 64.764 33.552 ;
     RECT  63.961 33.552 64.716 33.576 ;
     RECT  63.961 33.576 64.764 33.648 ;
     RECT  63.961 33.648 64.716 33.672 ;
     RECT  63.961 33.672 64.764 33.744 ;
     RECT  63.961 33.744 64.716 33.768 ;
     RECT  63.961 33.768 64.764 33.84 ;
     RECT  63.961 33.84 64.716 33.864 ;
     RECT  63.961 33.864 64.764 33.936 ;
     RECT  63.961 33.936 64.716 33.96 ;
     RECT  63.961 33.96 64.764 34.032 ;
     RECT  63.961 34.032 64.716 34.056 ;
     RECT  63.961 34.056 64.764 34.128 ;
     RECT  63.961 34.128 64.716 34.152 ;
     RECT  63.961 34.152 64.764 34.224 ;
     RECT  63.961 34.224 64.716 34.248 ;
     RECT  63.961 34.248 64.764 34.32 ;
     RECT  63.961 34.32 64.716 34.344 ;
     RECT  63.961 34.344 64.764 34.416 ;
     RECT  63.961 34.416 64.716 34.44 ;
     RECT  63.961 34.44 64.764 34.512 ;
     RECT  63.961 34.512 64.716 34.536 ;
     RECT  63.961 34.536 64.764 34.608 ;
     RECT  63.961 34.608 64.716 34.632 ;
     RECT  63.961 34.632 64.764 34.704 ;
     RECT  63.961 34.704 64.716 34.728 ;
     RECT  63.961 34.728 64.764 34.8 ;
     RECT  63.961 34.8 64.716 34.824 ;
     RECT  63.961 34.824 64.764 34.896 ;
     RECT  63.961 34.896 64.716 34.92 ;
     RECT  63.961 34.92 64.764 34.992 ;
     RECT  63.961 34.992 64.716 35.016 ;
     RECT  63.961 35.016 64.764 35.088 ;
     RECT  63.961 35.088 64.716 35.112 ;
     RECT  63.961 35.112 64.764 35.184 ;
     RECT  63.961 35.184 64.716 35.208 ;
     RECT  63.961 35.208 64.764 35.28 ;
     RECT  63.961 35.28 64.716 35.304 ;
     RECT  63.961 35.304 64.764 35.376 ;
     RECT  63.961 35.376 64.716 35.4 ;
     RECT  63.961 35.4 64.764 35.472 ;
     RECT  63.961 35.472 64.716 35.496 ;
     RECT  63.961 35.496 64.764 35.568 ;
     RECT  63.961 35.568 64.716 35.592 ;
     RECT  63.961 35.592 64.764 35.664 ;
     RECT  63.961 35.664 64.716 35.688 ;
     RECT  63.961 35.688 64.764 35.76 ;
     RECT  63.961 35.76 64.716 35.784 ;
     RECT  63.961 35.784 64.764 35.856 ;
     RECT  63.961 35.856 64.716 35.88 ;
     RECT  63.961 35.88 64.764 35.952 ;
     RECT  63.961 35.952 64.716 35.976 ;
     RECT  63.961 35.976 64.764 36.048 ;
     RECT  63.961 36.048 64.716 36.072 ;
     RECT  63.961 36.072 64.764 36.144 ;
     RECT  63.961 36.144 64.716 36.168 ;
     RECT  63.961 36.168 64.764 36.24 ;
     RECT  63.961 36.24 64.716 36.264 ;
     RECT  63.961 36.264 64.764 36.336 ;
     RECT  63.961 36.336 64.716 36.36 ;
     RECT  63.961 36.36 64.764 36.432 ;
     RECT  63.961 36.432 64.716 36.456 ;
     RECT  63.961 36.456 64.764 36.528 ;
     RECT  63.961 36.528 64.716 36.552 ;
     RECT  63.961 36.552 64.764 36.624 ;
     RECT  63.961 36.624 64.716 36.648 ;
     RECT  63.961 36.648 64.764 36.72 ;
     RECT  63.961 36.72 64.716 36.744 ;
     RECT  63.961 36.744 64.764 36.816 ;
     RECT  63.961 36.816 64.716 36.84 ;
     RECT  63.961 36.84 64.764 36.912 ;
     RECT  63.961 36.912 64.716 36.936 ;
     RECT  63.961 36.936 64.764 37.008 ;
     RECT  63.961 37.008 64.716 37.032 ;
     RECT  63.961 37.032 64.764 37.104 ;
     RECT  63.961 37.104 64.716 37.128 ;
     RECT  63.961 37.128 64.764 37.2 ;
     RECT  63.961 37.2 64.716 37.224 ;
     RECT  63.961 37.224 64.764 37.296 ;
     RECT  63.961 37.296 64.716 37.32 ;
     RECT  63.961 37.32 64.764 37.392 ;
     RECT  63.961 37.392 64.716 37.416 ;
     RECT  63.961 37.416 64.764 37.488 ;
     RECT  63.961 37.488 64.716 37.512 ;
     RECT  63.961 37.512 64.764 37.584 ;
     RECT  63.961 37.584 64.716 37.608 ;
     RECT  63.961 37.608 64.764 37.68 ;
     RECT  63.961 37.68 64.716 37.704 ;
     RECT  63.961 37.704 64.764 37.776 ;
     RECT  63.961 37.776 64.716 37.8 ;
     RECT  63.961 37.8 64.764 37.872 ;
     RECT  63.961 37.872 64.716 37.896 ;
     RECT  63.961 37.896 64.764 37.968 ;
     RECT  63.961 37.968 64.716 37.992 ;
     RECT  63.961 37.992 64.764 38.064 ;
     RECT  63.961 38.064 64.716 38.088 ;
     RECT  63.961 38.088 64.764 38.16 ;
     RECT  63.961 38.16 64.716 38.184 ;
     RECT  63.961 38.184 64.764 38.256 ;
     RECT  63.961 38.256 64.716 38.28 ;
     RECT  63.961 38.28 64.764 38.352 ;
     RECT  63.961 38.352 64.716 38.376 ;
     RECT  63.961 38.376 64.764 38.448 ;
     RECT  63.961 38.448 64.716 38.472 ;
     RECT  63.961 38.472 64.764 38.544 ;
     RECT  63.961 38.544 64.716 38.568 ;
    LAYER M5 ;
     RECT  32.232 0.016 32.304 0.084 ;
     RECT  32.328 0.016 32.4 0.084 ;
     RECT  32.424 0.016 32.496 0.084 ;
     RECT  32.52 0.016 32.592 0.084 ;
     RECT  32.616 0.016 32.688 0.084 ;
     RECT  32.712 0.016 32.784 0.084 ;
     RECT  32.808 0.016 32.88 0.084 ;
     RECT  32.904 0.016 32.976 0.084 ;
     RECT  33 0.016 33.072 0.084 ;
     RECT  33.096 0.016 33.168 0.084 ;
     RECT  33.192 0.016 33.264 0.084 ;
     RECT  33.288 0.016 33.36 0.084 ;
     RECT  33.384 0.016 33.456 0.084 ;
     RECT  33.48 0.016 33.552 0.084 ;
     RECT  33.576 0.016 33.648 0.084 ;
     RECT  33.672 0.016 33.744 0.084 ;
     RECT  33.768 0.016 33.84 0.084 ;
     RECT  33.864 0.016 33.936 0.084 ;
     RECT  33.96 0.016 34.032 0.084 ;
     RECT  34.056 0.016 34.128 0.084 ;
     RECT  34.152 0.016 34.224 0.084 ;
     RECT  34.248 0.016 34.32 0.084 ;
     RECT  34.344 0.016 34.416 0.084 ;
     RECT  34.44 0.016 34.512 0.084 ;
     RECT  34.536 0.016 34.608 0.084 ;
     RECT  34.632 0.016 34.704 0.084 ;
     RECT  34.728 0.016 34.8 0.084 ;
     RECT  34.824 0.016 34.896 0.084 ;
     RECT  34.92 0.016 34.992 0.084 ;
     RECT  35.016 0.016 35.088 0.084 ;
     RECT  35.112 0.016 35.184 0.084 ;
     RECT  35.208 0.016 35.28 0.084 ;
     RECT  35.304 0.016 35.376 0.084 ;
     RECT  35.4 0.016 35.472 0.084 ;
     RECT  35.496 0.016 35.568 0.084 ;
     RECT  35.592 0.016 35.664 0.084 ;
     RECT  35.688 0.016 35.76 0.084 ;
     RECT  35.784 0.016 35.856 0.084 ;
     RECT  35.88 0.016 35.952 0.084 ;
     RECT  35.976 0.016 36.048 0.084 ;
     RECT  36.072 0.016 36.144 0.084 ;
     RECT  36.168 0.016 36.24 0.084 ;
     RECT  36.264 0.016 36.336 0.084 ;
     RECT  36.36 0.016 36.432 0.084 ;
     RECT  36.456 0.016 36.528 0.084 ;
     RECT  36.552 0.016 36.624 0.084 ;
     RECT  36.648 0.016 36.72 0.084 ;
     RECT  36.744 0.016 36.816 0.084 ;
     RECT  36.84 0.016 36.912 0.084 ;
     RECT  36.936 0.016 37.008 0.084 ;
     RECT  37.032 0.016 37.104 0.084 ;
     RECT  37.128 0.016 37.2 0.084 ;
     RECT  37.224 0.016 37.296 0.084 ;
     RECT  37.32 0.016 37.392 0.084 ;
     RECT  37.416 0.016 37.488 0.084 ;
     RECT  37.512 0.016 37.584 0.084 ;
     RECT  37.608 0.016 37.68 0.084 ;
     RECT  37.704 0.016 37.776 0.084 ;
     RECT  37.8 0.016 37.872 0.084 ;
     RECT  37.896 0.016 37.968 0.084 ;
     RECT  37.992 0.016 38.064 0.084 ;
     RECT  38.088 0.016 38.16 0.084 ;
     RECT  38.184 0.016 38.256 0.084 ;
     RECT  38.28 0.016 38.352 0.084 ;
     RECT  38.376 0.016 38.448 0.084 ;
     RECT  38.472 0.016 38.544 0.084 ;
     RECT  38.568 0.016 38.64 0.084 ;
     RECT  38.664 0.016 38.736 0.084 ;
     RECT  38.76 0.016 38.832 0.084 ;
     RECT  38.856 0.016 38.928 0.084 ;
     RECT  38.952 0.016 39.024 0.084 ;
     RECT  39.048 0.016 39.12 0.084 ;
     RECT  39.144 0.016 39.216 0.084 ;
     RECT  39.24 0.016 39.312 0.084 ;
     RECT  39.336 0.016 39.408 0.084 ;
     RECT  39.432 0.016 39.504 0.084 ;
     RECT  39.528 0.016 39.6 0.084 ;
     RECT  39.624 0.016 39.696 0.084 ;
     RECT  39.72 0.016 39.792 0.084 ;
     RECT  39.816 0.016 39.888 0.084 ;
     RECT  39.912 0.016 39.984 0.084 ;
     RECT  40.008 0.016 40.08 0.084 ;
     RECT  40.104 0.016 40.176 0.084 ;
     RECT  40.2 0.016 40.272 0.084 ;
     RECT  40.296 0.016 40.368 0.084 ;
     RECT  40.392 0.016 40.464 0.084 ;
     RECT  40.488 0.016 40.56 0.084 ;
     RECT  40.584 0.016 40.656 0.084 ;
     RECT  40.68 0.016 40.752 0.084 ;
     RECT  40.776 0.016 40.848 0.084 ;
     RECT  40.872 0.016 40.944 0.084 ;
     RECT  40.968 0.016 41.04 0.084 ;
     RECT  41.064 0.016 41.136 0.084 ;
     RECT  41.16 0.016 41.232 0.084 ;
     RECT  41.256 0.016 41.328 0.084 ;
     RECT  41.352 0.016 41.424 0.084 ;
     RECT  41.448 0.016 41.52 0.084 ;
     RECT  41.544 0.016 41.616 0.084 ;
     RECT  41.64 0.016 41.712 0.084 ;
     RECT  41.736 0.016 41.808 0.084 ;
     RECT  41.832 0.016 41.904 0.084 ;
     RECT  41.928 0.016 42 0.084 ;
     RECT  42.024 0.016 42.096 0.084 ;
     RECT  42.12 0.016 42.192 0.084 ;
     RECT  42.216 0.016 42.288 0.084 ;
     RECT  42.312 0.016 42.384 0.084 ;
     RECT  42.408 0.016 42.48 0.084 ;
     RECT  42.504 0.016 42.576 0.084 ;
     RECT  42.6 0.016 42.672 0.084 ;
     RECT  42.696 0.016 42.768 0.084 ;
     RECT  42.792 0.016 42.864 0.084 ;
     RECT  42.888 0.016 42.96 0.084 ;
     RECT  42.984 0.016 43.056 0.084 ;
     RECT  43.08 0.016 43.152 0.084 ;
     RECT  43.176 0.016 43.248 0.084 ;
     RECT  43.272 0.016 43.344 0.084 ;
     RECT  43.368 0.016 43.44 0.084 ;
     RECT  43.464 0.016 43.536 0.084 ;
     RECT  43.56 0.016 43.632 0.084 ;
     RECT  43.656 0.016 43.728 0.084 ;
     RECT  43.752 0.016 43.824 0.084 ;
     RECT  43.848 0.016 43.92 0.084 ;
     RECT  43.944 0.016 44.016 0.084 ;
     RECT  44.04 0.016 44.112 0.084 ;
     RECT  44.136 0.016 44.208 0.084 ;
     RECT  44.232 0.016 44.304 0.084 ;
     RECT  44.328 0.016 44.4 0.084 ;
     RECT  44.424 0.016 44.496 0.084 ;
     RECT  44.52 0.016 44.592 0.084 ;
     RECT  44.616 0.016 44.688 0.084 ;
     RECT  44.712 0.016 44.784 0.084 ;
     RECT  44.808 0.016 44.88 0.084 ;
     RECT  44.904 0.016 44.976 0.084 ;
     RECT  45 0.016 45.072 0.084 ;
     RECT  45.096 0.016 45.168 0.084 ;
     RECT  45.192 0.016 45.264 0.084 ;
     RECT  45.288 0.016 45.36 0.084 ;
     RECT  45.384 0.016 45.456 0.084 ;
     RECT  45.48 0.016 45.552 0.084 ;
     RECT  45.576 0.016 45.648 0.084 ;
     RECT  45.672 0.016 45.744 0.084 ;
     RECT  45.768 0.016 45.84 0.084 ;
     RECT  45.864 0.016 45.936 0.084 ;
     RECT  45.96 0.016 46.032 0.084 ;
     RECT  46.056 0.016 46.128 0.084 ;
     RECT  46.152 0.016 46.224 0.084 ;
     RECT  46.248 0.016 46.32 0.084 ;
     RECT  46.344 0.016 46.416 0.084 ;
     RECT  46.44 0.016 46.512 0.084 ;
     RECT  46.536 0.016 46.608 0.084 ;
     RECT  46.632 0.016 46.704 0.084 ;
     RECT  46.728 0.016 46.8 0.084 ;
     RECT  46.824 0.016 46.896 0.084 ;
     RECT  46.92 0.016 46.992 0.084 ;
     RECT  47.016 0.016 47.088 0.084 ;
     RECT  47.112 0.016 47.184 0.084 ;
     RECT  47.208 0.016 47.28 0.084 ;
     RECT  47.304 0.016 47.376 0.084 ;
     RECT  47.4 0.016 47.472 0.084 ;
     RECT  47.496 0.016 47.568 0.084 ;
     RECT  47.592 0.016 47.664 0.084 ;
     RECT  47.688 0.016 47.76 0.084 ;
     RECT  47.784 0.016 47.856 0.084 ;
     RECT  47.88 0.016 47.952 0.084 ;
     RECT  47.976 0.016 48.048 0.084 ;
     RECT  48.072 0.016 48.144 0.084 ;
     RECT  48.168 0.016 48.24 0.084 ;
     RECT  48.264 0.016 48.336 0.084 ;
     RECT  48.36 0.016 48.432 0.084 ;
     RECT  48.456 0.016 48.528 0.084 ;
     RECT  48.552 0.016 48.624 0.084 ;
     RECT  48.648 0.016 48.72 0.084 ;
     RECT  48.744 0.016 48.816 0.084 ;
     RECT  48.84 0.016 48.912 0.084 ;
     RECT  48.936 0.016 49.008 0.084 ;
     RECT  49.032 0.016 49.104 0.084 ;
     RECT  49.128 0.016 49.2 0.084 ;
     RECT  49.224 0.016 49.296 0.084 ;
     RECT  49.32 0.016 49.392 0.084 ;
     RECT  49.416 0.016 49.488 0.084 ;
     RECT  49.512 0.016 49.584 0.084 ;
     RECT  49.608 0.016 49.68 0.084 ;
     RECT  49.704 0.016 49.776 0.084 ;
     RECT  49.8 0.016 49.872 0.084 ;
     RECT  49.896 0.016 49.968 0.084 ;
     RECT  49.992 0.016 50.064 0.084 ;
     RECT  50.088 0.016 50.16 0.084 ;
     RECT  50.184 0.016 50.256 0.084 ;
     RECT  50.28 0.016 50.352 0.084 ;
     RECT  50.376 0.016 50.448 0.084 ;
     RECT  50.472 0.016 50.544 0.084 ;
     RECT  50.568 0.016 51.408 0.084 ;
     RECT  51.432 0.016 51.504 0.084 ;
     RECT  51.528 0.016 51.6 0.084 ;
     RECT  51.624 0.016 51.696 0.084 ;
     RECT  51.72 0.016 51.792 0.084 ;
     RECT  51.816 0.016 51.888 0.084 ;
     RECT  51.912 0.016 51.984 0.084 ;
     RECT  52.008 0.016 52.08 0.084 ;
     RECT  52.104 0.016 52.176 0.084 ;
     RECT  52.2 0.016 52.272 0.084 ;
     RECT  52.296 0.016 52.368 0.084 ;
     RECT  52.392 0.016 52.464 0.084 ;
     RECT  52.488 0.016 52.56 0.084 ;
     RECT  52.584 0.016 52.656 0.084 ;
     RECT  52.68 0.016 52.752 0.084 ;
     RECT  52.776 0.016 52.848 0.084 ;
     RECT  52.872 0.016 52.944 0.084 ;
     RECT  52.968 0.016 53.04 0.084 ;
     RECT  53.064 0.016 53.136 0.084 ;
     RECT  53.16 0.016 53.232 0.084 ;
     RECT  53.256 0.016 53.328 0.084 ;
     RECT  53.352 0.016 53.424 0.084 ;
     RECT  53.448 0.016 53.52 0.084 ;
     RECT  53.544 0.016 53.616 0.084 ;
     RECT  53.64 0.016 53.712 0.084 ;
     RECT  53.736 0.016 53.808 0.084 ;
     RECT  53.832 0.016 53.904 0.084 ;
     RECT  53.928 0.016 54 0.084 ;
     RECT  54.024 0.016 54.096 0.084 ;
     RECT  54.12 0.016 54.192 0.084 ;
     RECT  54.216 0.016 54.288 0.084 ;
     RECT  54.312 0.016 54.384 0.084 ;
     RECT  54.408 0.016 54.48 0.084 ;
     RECT  54.504 0.016 54.576 0.084 ;
     RECT  54.6 0.016 54.672 0.084 ;
     RECT  54.696 0.016 54.768 0.084 ;
     RECT  54.792 0.016 54.864 0.084 ;
     RECT  54.888 0.016 54.96 0.084 ;
     RECT  54.984 0.016 55.056 0.084 ;
     RECT  55.08 0.016 55.152 0.084 ;
     RECT  55.176 0.016 55.248 0.084 ;
     RECT  55.272 0.016 55.344 0.084 ;
     RECT  55.368 0.016 55.44 0.084 ;
     RECT  55.464 0.016 55.536 0.084 ;
     RECT  55.56 0.016 55.632 0.084 ;
     RECT  55.656 0.016 55.728 0.084 ;
     RECT  55.752 0.016 55.824 0.084 ;
     RECT  55.848 0.016 55.92 0.084 ;
     RECT  55.944 0.016 56.016 0.084 ;
     RECT  56.04 0.016 56.112 0.084 ;
     RECT  56.136 0.016 56.208 0.084 ;
     RECT  56.232 0.016 56.304 0.084 ;
     RECT  56.328 0.016 56.4 0.084 ;
     RECT  56.424 0.016 56.496 0.084 ;
     RECT  56.52 0.016 56.592 0.084 ;
     RECT  56.616 0.016 56.688 0.084 ;
     RECT  56.712 0.016 56.784 0.084 ;
     RECT  56.808 0.016 56.88 0.084 ;
     RECT  56.904 0.016 56.976 0.084 ;
     RECT  57 0.016 57.072 0.084 ;
     RECT  57.096 0.016 57.168 0.084 ;
     RECT  57.192 0.016 57.264 0.084 ;
     RECT  57.288 0.016 57.36 0.084 ;
     RECT  57.384 0.016 57.456 0.084 ;
     RECT  32.208 0.084 57.48 0.085 ;
     RECT  6.12 0.016 6.192 0.084 ;
     RECT  6.216 0.016 6.288 0.084 ;
     RECT  6.312 0.016 6.384 0.084 ;
     RECT  6.408 0.016 6.48 0.084 ;
     RECT  6.504 0.016 6.576 0.084 ;
     RECT  6.6 0.016 6.672 0.084 ;
     RECT  6.696 0.016 6.768 0.084 ;
     RECT  6.792 0.016 6.864 0.084 ;
     RECT  6.888 0.016 6.96 0.084 ;
     RECT  6.984 0.016 7.056 0.084 ;
     RECT  7.08 0.016 7.152 0.084 ;
     RECT  7.176 0.016 7.248 0.084 ;
     RECT  7.272 0.016 7.344 0.084 ;
     RECT  7.368 0.016 7.44 0.084 ;
     RECT  7.464 0.016 7.536 0.084 ;
     RECT  7.56 0.016 7.632 0.084 ;
     RECT  7.656 0.016 7.728 0.084 ;
     RECT  7.752 0.016 7.824 0.084 ;
     RECT  7.848 0.016 7.92 0.084 ;
     RECT  6.096 0.084 7.944 1.763 ;
     RECT  1.896 0.016 1.968 0.084 ;
     RECT  1.992 0.016 2.064 0.084 ;
     RECT  2.088 0.016 2.16 0.084 ;
     RECT  1.872 0.084 2.184 2.137 ;
     RECT  1.872 2.137 2.52 2.151 ;
     RECT  6.192 1.763 7.944 2.151 ;
     RECT  13.2 2.137 13.32 2.151 ;
     RECT  18.6 2.137 18.72 2.151 ;
     RECT  24 2.137 24.12 2.151 ;
     RECT  29.4 2.137 29.52 2.151 ;
     RECT  61.8 2.137 61.92 2.151 ;
     RECT  6.192 2.151 8.112 2.291 ;
     RECT  0.144 2.629 0.168 2.725 ;
     RECT  1.872 2.151 2.712 2.773 ;
     RECT  1.872 2.773 3.24 2.915 ;
     RECT  6.768 2.291 8.112 2.915 ;
     RECT  9.192 0.016 9.264 0.084 ;
     RECT  9.288 0.016 9.36 0.084 ;
     RECT  9.384 0.016 9.456 0.084 ;
     RECT  9.48 0.016 9.552 0.084 ;
     RECT  9.576 0.016 9.648 0.084 ;
     RECT  9.672 0.016 9.744 0.084 ;
     RECT  9.768 0.016 9.84 0.084 ;
     RECT  9.864 0.016 9.936 0.084 ;
     RECT  9.96 0.016 10.032 0.084 ;
     RECT  10.056 0.016 10.128 0.084 ;
     RECT  10.152 0.016 10.224 0.084 ;
     RECT  10.248 0.016 10.32 0.084 ;
     RECT  10.344 0.016 10.416 0.084 ;
     RECT  10.44 0.016 10.512 0.084 ;
     RECT  10.536 0.016 10.608 0.084 ;
     RECT  10.632 0.016 10.704 0.084 ;
     RECT  10.728 0.016 10.8 0.084 ;
     RECT  10.824 0.016 10.896 0.084 ;
     RECT  10.92 0.016 10.992 0.084 ;
     RECT  11.016 0.016 11.088 0.084 ;
     RECT  11.112 0.016 11.184 0.084 ;
     RECT  11.208 0.016 11.28 0.084 ;
     RECT  11.304 0.016 11.376 0.084 ;
     RECT  11.4 0.016 11.472 0.084 ;
     RECT  11.496 0.016 11.568 0.084 ;
     RECT  11.592 0.016 11.664 0.084 ;
     RECT  11.688 0.016 11.76 0.084 ;
     RECT  11.784 0.016 11.856 0.084 ;
     RECT  11.88 0.016 11.952 0.084 ;
     RECT  11.976 0.016 12.048 0.084 ;
     RECT  12.072 0.016 12.144 0.084 ;
     RECT  9.168 0.084 12.168 2.915 ;
     RECT  2.304 2.915 3.24 3.349 ;
     RECT  2.304 3.349 3.48 3.397 ;
     RECT  0.144 2.725 0.216 3.443 ;
     RECT  6.96 2.915 8.112 3.443 ;
     RECT  7.44 3.443 8.112 4.213 ;
     RECT  7.44 4.213 8.232 4.405 ;
     RECT  9.264 2.915 12.168 4.405 ;
     RECT  2.304 3.397 3.72 4.501 ;
     RECT  7.44 4.405 12.168 4.501 ;
     RECT  6.864 4.501 12.168 4.789 ;
     RECT  5.184 4.693 5.208 4.981 ;
     RECT  0.144 3.443 0.168 5.171 ;
     RECT  2.304 4.501 4.008 5.605 ;
     RECT  5.184 4.981 5.496 5.605 ;
     RECT  6.528 4.789 12.168 5.699 ;
     RECT  2.304 5.605 5.496 5.989 ;
     RECT  6.528 5.699 11.688 5.989 ;
     RECT  2.304 5.989 11.688 6.275 ;
     RECT  2.304 6.275 11.4 10.883 ;
     RECT  2.304 10.883 11.112 11.459 ;
     RECT  2.304 11.459 10.392 11.699 ;
     RECT  2.304 11.699 10.248 12.659 ;
     RECT  0.528 12.805 0.552 13.573 ;
     RECT  0.288 13.573 0.552 13.621 ;
     RECT  2.304 12.659 10.152 13.669 ;
     RECT  32.208 0.085 57.672 14.005 ;
     RECT  2.304 13.669 10.248 14.101 ;
     RECT  0.192 13.621 0.552 14.197 ;
     RECT  32.208 14.005 57.72 14.197 ;
     RECT  61.8 2.151 62.112 14.245 ;
     RECT  32.208 14.197 58.632 14.437 ;
     RECT  2.304 14.101 10.344 14.485 ;
     RECT  2.304 14.485 10.392 14.867 ;
     RECT  0.144 14.197 0.552 14.963 ;
     RECT  0.144 14.963 0.216 15.923 ;
     RECT  2.4 14.867 10.392 15.973 ;
     RECT  61.8 14.245 62.52 16.019 ;
     RECT  32.208 14.437 59.112 16.357 ;
     RECT  18.6 2.151 18.912 16.453 ;
     RECT  13.2 2.151 13.512 16.501 ;
     RECT  61.8 16.019 62.112 16.645 ;
     RECT  32.208 16.357 59.256 16.741 ;
     RECT  0.144 15.923 0.168 16.933 ;
     RECT  32.208 16.741 59.592 16.979 ;
     RECT  0.144 16.933 0.216 16.981 ;
     RECT  32.208 16.979 59.256 17.125 ;
     RECT  0.144 16.981 0.504 17.411 ;
     RECT  17.664 16.453 18.912 17.891 ;
     RECT  60.96 16.645 62.112 17.989 ;
     RECT  0.24 17.411 0.504 18.035 ;
     RECT  12.672 16.501 13.512 18.179 ;
     RECT  2.304 15.973 10.392 18.181 ;
     RECT  32.064 17.125 59.256 18.181 ;
     RECT  32.064 18.181 59.688 18.757 ;
     RECT  29.4 2.151 29.712 19.093 ;
     RECT  30.72 17.989 30.744 19.093 ;
     RECT  0.48 18.035 0.504 19.285 ;
     RECT  0.24 19.285 0.504 19.333 ;
     RECT  32.064 18.757 59.784 19.477 ;
     RECT  60.912 17.989 62.112 19.477 ;
     RECT  29.4 19.093 30.744 19.573 ;
     RECT  32.064 19.477 62.112 19.573 ;
     RECT  29.4 19.573 62.112 19.715 ;
     RECT  18.6 17.891 18.912 19.909 ;
     RECT  19.968 19.141 19.992 19.909 ;
     RECT  0.144 19.333 0.504 20.389 ;
     RECT  29.4 19.715 59.928 20.435 ;
     RECT  18.6 19.909 19.992 20.531 ;
     RECT  17.328 18.757 17.352 20.629 ;
     RECT  18.6 20.531 18.912 20.629 ;
     RECT  17.328 20.629 18.912 20.675 ;
     RECT  29.4 20.435 59.784 20.869 ;
     RECT  28.752 20.869 59.784 21.155 ;
     RECT  2.304 18.181 11.304 21.203 ;
     RECT  13.2 18.179 13.512 21.445 ;
     RECT  17.616 20.675 18.912 21.491 ;
     RECT  32.4 21.155 59.784 21.589 ;
     RECT  60.912 19.715 62.112 21.589 ;
     RECT  12.864 21.445 13.512 21.635 ;
     RECT  32.4 21.589 62.112 21.683 ;
     RECT  0.144 20.389 0.552 21.779 ;
     RECT  32.496 21.683 62.112 22.741 ;
     RECT  32.352 22.741 62.112 22.789 ;
     RECT  28.752 21.155 31.32 23.125 ;
     RECT  32.352 22.789 62.568 23.125 ;
     RECT  28.752 23.125 62.568 23.173 ;
     RECT  0.144 21.779 0.168 23.269 ;
     RECT  0.144 23.269 0.216 23.411 ;
     RECT  0.192 23.411 0.216 23.987 ;
     RECT  28.752 23.173 62.664 24.419 ;
     RECT  61.8 24.419 62.664 25.139 ;
     RECT  61.8 25.139 62.112 25.525 ;
     RECT  0.192 25.525 0.216 25.621 ;
     RECT  28.752 24.419 60.696 25.861 ;
     RECT  61.68 25.525 62.112 25.861 ;
     RECT  28.752 25.861 62.112 26.051 ;
     RECT  0.144 25.621 0.216 26.101 ;
     RECT  28.752 26.051 60.552 26.101 ;
     RECT  24 2.151 24.312 26.293 ;
     RECT  0.144 26.101 0.264 26.675 ;
     RECT  21.36 22.165 21.384 26.819 ;
     RECT  24 26.293 24.504 26.819 ;
     RECT  0.144 26.675 0.216 26.963 ;
     RECT  61.68 26.051 62.112 27.395 ;
     RECT  25.872 25.045 25.896 28.165 ;
     RECT  27.888 26.101 60.552 29.077 ;
     RECT  0.144 26.963 0.168 29.363 ;
     RECT  25.872 28.165 26.472 29.365 ;
     RECT  27.888 29.077 60.648 29.365 ;
     RECT  2.304 21.203 10.392 29.795 ;
     RECT  11.424 30.613 11.448 30.709 ;
     RECT  0.288 30.757 0.312 30.899 ;
     RECT  25.872 29.365 60.648 30.899 ;
     RECT  11.424 30.709 11.496 31.285 ;
     RECT  2.4 29.795 10.344 31.475 ;
     RECT  0.144 31.429 0.168 31.715 ;
     RECT  11.424 31.285 11.544 32.341 ;
     RECT  2.4 31.475 10.296 32.437 ;
     RECT  11.424 32.341 11.688 32.437 ;
     RECT  25.872 30.899 60.552 32.485 ;
     RECT  25.68 32.485 60.552 33.733 ;
     RECT  61.8 27.395 62.112 33.733 ;
     RECT  25.68 33.733 62.112 33.923 ;
     RECT  2.4 32.437 11.688 34.787 ;
     RECT  25.68 33.923 60.552 34.835 ;
     RECT  5.76 34.787 11.688 35.171 ;
     RECT  25.68 34.835 60.456 35.363 ;
     RECT  25.68 35.363 59.112 35.795 ;
     RECT  60.192 35.363 60.456 35.939 ;
     RECT  60.192 35.939 60.36 35.987 ;
     RECT  2.4 34.787 4.776 36.659 ;
     RECT  60.192 35.987 60.216 37.091 ;
     RECT  6.192 35.171 11.688 37.715 ;
     RECT  6.672 37.715 11.688 38.867 ;
     RECT  7.248 38.867 11.688 39.155 ;
     RECT  7.296 39.155 11.688 39.349 ;
     RECT  2.4 36.659 4.632 39.923 ;
     RECT  25.68 35.795 58.92 39.923 ;
     RECT  3.696 39.923 4.632 39.971 ;
     RECT  7.296 39.349 12.072 40.453 ;
     RECT  25.68 39.923 54.84 40.499 ;
     RECT  55.824 39.923 58.92 40.547 ;
     RECT  7.296 40.453 12.168 40.595 ;
     RECT  55.824 40.547 57.912 40.595 ;
     RECT  58.896 40.547 58.92 40.595 ;
     RECT  25.68 40.499 53.976 40.643 ;
     RECT  4.608 39.971 4.632 40.691 ;
     RECT  25.68 40.643 53.352 40.691 ;
     RECT  2.4 39.923 2.712 40.693 ;
     RECT  55.824 40.595 57.048 40.739 ;
     RECT  25.68 40.691 52.824 40.787 ;
     RECT  2.256 40.693 2.712 40.981 ;
     RECT  2.16 40.981 2.712 41.049 ;
     RECT  13.2 21.635 13.512 41.049 ;
     RECT  18.6 21.491 18.912 41.049 ;
     RECT  24 26.819 24.312 41.049 ;
     RECT  55.824 40.739 56.712 41.049 ;
     RECT  61.8 33.923 62.112 41.049 ;
     RECT  2.16 41.049 2.52 41.063 ;
     RECT  13.2 41.049 13.32 41.063 ;
     RECT  18.6 41.049 18.72 41.063 ;
     RECT  24 41.049 24.12 41.063 ;
     RECT  55.824 41.049 56.52 41.063 ;
     RECT  61.8 41.049 61.92 41.063 ;
     RECT  55.824 41.063 55.848 41.123 ;
     RECT  25.68 40.787 52.44 41.267 ;
     RECT  7.44 40.595 12.168 41.605 ;
     RECT  25.68 41.267 51.528 41.747 ;
     RECT  7.44 41.605 12.456 43.091 ;
     RECT  2.16 41.063 2.472 43.116 ;
     RECT  2.184 43.116 2.256 43.152 ;
     RECT  2.28 43.116 2.352 43.152 ;
     RECT  2.376 43.116 2.448 43.152 ;
     RECT  7.536 43.091 12.456 43.116 ;
     RECT  7.56 43.116 7.632 43.152 ;
     RECT  7.656 43.116 7.728 43.152 ;
     RECT  7.752 43.116 7.824 43.152 ;
     RECT  7.848 43.116 7.92 43.152 ;
     RECT  7.944 43.116 8.016 43.152 ;
     RECT  8.04 43.116 8.112 43.152 ;
     RECT  8.136 43.116 8.208 43.152 ;
     RECT  8.232 43.116 8.304 43.152 ;
     RECT  8.328 43.116 8.4 43.152 ;
     RECT  8.424 43.116 8.496 43.152 ;
     RECT  8.52 43.116 8.592 43.152 ;
     RECT  8.616 43.116 8.688 43.152 ;
     RECT  8.712 43.116 8.784 43.152 ;
     RECT  8.808 43.116 8.88 43.152 ;
     RECT  8.904 43.116 8.976 43.152 ;
     RECT  9 43.116 9.072 43.152 ;
     RECT  9.096 43.116 9.168 43.152 ;
     RECT  9.192 43.116 9.264 43.152 ;
     RECT  9.288 43.116 9.36 43.152 ;
     RECT  9.384 43.116 9.456 43.152 ;
     RECT  9.48 43.116 9.552 43.152 ;
     RECT  9.576 43.116 9.648 43.152 ;
     RECT  9.672 43.116 9.744 43.152 ;
     RECT  9.768 43.116 9.84 43.152 ;
     RECT  9.864 43.116 9.936 43.152 ;
     RECT  9.96 43.116 10.032 43.152 ;
     RECT  10.056 43.116 10.128 43.152 ;
     RECT  10.152 43.116 10.224 43.152 ;
     RECT  10.248 43.116 10.32 43.152 ;
     RECT  10.344 43.116 10.416 43.152 ;
     RECT  10.44 43.116 10.512 43.152 ;
     RECT  10.536 43.116 10.608 43.152 ;
     RECT  10.632 43.116 10.704 43.152 ;
     RECT  10.728 43.116 10.8 43.152 ;
     RECT  10.824 43.116 10.896 43.152 ;
     RECT  10.92 43.116 10.992 43.152 ;
     RECT  11.016 43.116 11.088 43.152 ;
     RECT  11.112 43.116 11.184 43.152 ;
     RECT  11.208 43.116 11.28 43.152 ;
     RECT  11.304 43.116 11.376 43.152 ;
     RECT  11.4 43.116 11.472 43.152 ;
     RECT  11.496 43.116 11.568 43.152 ;
     RECT  11.592 43.116 11.664 43.152 ;
     RECT  11.688 43.116 11.76 43.152 ;
     RECT  11.784 43.116 11.856 43.152 ;
     RECT  11.88 43.116 11.952 43.152 ;
     RECT  11.976 43.116 12.048 43.152 ;
     RECT  12.072 43.116 12.144 43.152 ;
     RECT  12.168 43.116 12.24 43.152 ;
     RECT  12.264 43.116 12.336 43.152 ;
     RECT  12.36 43.116 12.432 43.152 ;
     RECT  25.68 41.747 51.432 43.116 ;
     RECT  25.704 43.116 25.776 43.152 ;
     RECT  25.8 43.116 25.872 43.152 ;
     RECT  25.896 43.116 25.968 43.152 ;
     RECT  25.992 43.116 26.064 43.152 ;
     RECT  26.088 43.116 26.16 43.152 ;
     RECT  26.184 43.116 26.256 43.152 ;
     RECT  26.28 43.116 26.352 43.152 ;
     RECT  26.376 43.116 26.448 43.152 ;
     RECT  26.472 43.116 26.544 43.152 ;
     RECT  26.568 43.116 26.64 43.152 ;
     RECT  26.664 43.116 26.736 43.152 ;
     RECT  26.76 43.116 26.832 43.152 ;
     RECT  26.856 43.116 26.928 43.152 ;
     RECT  26.952 43.116 27.024 43.152 ;
     RECT  27.048 43.116 27.12 43.152 ;
     RECT  27.144 43.116 27.216 43.152 ;
     RECT  27.24 43.116 27.312 43.152 ;
     RECT  27.336 43.116 27.408 43.152 ;
     RECT  27.432 43.116 27.504 43.152 ;
     RECT  27.528 43.116 27.6 43.152 ;
     RECT  27.624 43.116 27.696 43.152 ;
     RECT  27.72 43.116 27.792 43.152 ;
     RECT  27.816 43.116 27.888 43.152 ;
     RECT  27.912 43.116 27.984 43.152 ;
     RECT  28.008 43.116 28.08 43.152 ;
     RECT  28.104 43.116 28.176 43.152 ;
     RECT  28.2 43.116 28.272 43.152 ;
     RECT  28.296 43.116 28.368 43.152 ;
     RECT  28.392 43.116 28.464 43.152 ;
     RECT  28.488 43.116 28.56 43.152 ;
     RECT  28.584 43.116 28.656 43.152 ;
     RECT  28.68 43.116 28.752 43.152 ;
     RECT  28.776 43.116 28.848 43.152 ;
     RECT  28.872 43.116 28.944 43.152 ;
     RECT  28.968 43.116 29.04 43.152 ;
     RECT  29.064 43.116 29.136 43.152 ;
     RECT  29.16 43.116 29.232 43.152 ;
     RECT  29.256 43.116 29.328 43.152 ;
     RECT  29.352 43.116 29.424 43.152 ;
     RECT  29.448 43.116 29.52 43.152 ;
     RECT  29.544 43.116 29.616 43.152 ;
     RECT  29.64 43.116 29.712 43.152 ;
     RECT  29.736 43.116 29.808 43.152 ;
     RECT  29.832 43.116 29.904 43.152 ;
     RECT  29.928 43.116 30 43.152 ;
     RECT  30.024 43.116 30.096 43.152 ;
     RECT  30.12 43.116 30.192 43.152 ;
     RECT  30.216 43.116 30.288 43.152 ;
     RECT  30.312 43.116 30.384 43.152 ;
     RECT  30.408 43.116 30.48 43.152 ;
     RECT  30.504 43.116 30.576 43.152 ;
     RECT  30.6 43.116 30.672 43.152 ;
     RECT  30.696 43.116 30.768 43.152 ;
     RECT  30.792 43.116 30.864 43.152 ;
     RECT  30.888 43.116 30.96 43.152 ;
     RECT  30.984 43.116 31.056 43.152 ;
     RECT  31.08 43.116 31.152 43.152 ;
     RECT  31.176 43.116 31.248 43.152 ;
     RECT  31.272 43.116 31.344 43.152 ;
     RECT  31.368 43.116 31.44 43.152 ;
     RECT  31.464 43.116 31.536 43.152 ;
     RECT  31.56 43.116 31.632 43.152 ;
     RECT  31.656 43.116 31.728 43.152 ;
     RECT  31.752 43.116 31.824 43.152 ;
     RECT  31.848 43.116 31.92 43.152 ;
     RECT  31.944 43.116 32.016 43.152 ;
     RECT  32.04 43.116 32.112 43.152 ;
     RECT  32.136 43.116 32.208 43.152 ;
     RECT  32.232 43.116 32.304 43.152 ;
     RECT  32.328 43.116 32.4 43.152 ;
     RECT  32.424 43.116 32.496 43.152 ;
     RECT  32.52 43.116 32.592 43.152 ;
     RECT  32.616 43.116 32.688 43.152 ;
     RECT  32.712 43.116 32.784 43.152 ;
     RECT  32.808 43.116 32.88 43.152 ;
     RECT  32.904 43.116 32.976 43.152 ;
     RECT  33 43.116 33.072 43.152 ;
     RECT  33.096 43.116 33.168 43.152 ;
     RECT  33.192 43.116 33.264 43.152 ;
     RECT  33.288 43.116 33.36 43.152 ;
     RECT  33.384 43.116 33.456 43.152 ;
     RECT  33.48 43.116 33.552 43.152 ;
     RECT  33.576 43.116 33.648 43.152 ;
     RECT  33.672 43.116 33.744 43.152 ;
     RECT  33.768 43.116 33.84 43.152 ;
     RECT  33.864 43.116 33.936 43.152 ;
     RECT  33.96 43.116 34.032 43.152 ;
     RECT  34.056 43.116 34.128 43.152 ;
     RECT  34.152 43.116 34.224 43.152 ;
     RECT  34.248 43.116 34.32 43.152 ;
     RECT  34.344 43.116 34.416 43.152 ;
     RECT  34.44 43.116 34.512 43.152 ;
     RECT  34.536 43.116 34.608 43.152 ;
     RECT  34.632 43.116 34.704 43.152 ;
     RECT  34.728 43.116 34.8 43.152 ;
     RECT  34.824 43.116 34.896 43.152 ;
     RECT  34.92 43.116 34.992 43.152 ;
     RECT  35.016 43.116 35.088 43.152 ;
     RECT  35.112 43.116 35.184 43.152 ;
     RECT  35.208 43.116 35.28 43.152 ;
     RECT  35.304 43.116 35.376 43.152 ;
     RECT  35.4 43.116 35.472 43.152 ;
     RECT  35.496 43.116 35.568 43.152 ;
     RECT  35.592 43.116 35.664 43.152 ;
     RECT  35.688 43.116 35.76 43.152 ;
     RECT  35.784 43.116 35.856 43.152 ;
     RECT  35.88 43.116 35.952 43.152 ;
     RECT  35.976 43.116 36.048 43.152 ;
     RECT  36.072 43.116 36.144 43.152 ;
     RECT  36.168 43.116 36.24 43.152 ;
     RECT  36.264 43.116 36.336 43.152 ;
     RECT  36.36 43.116 36.432 43.152 ;
     RECT  36.456 43.116 36.528 43.152 ;
     RECT  36.552 43.116 36.624 43.152 ;
     RECT  36.648 43.116 36.72 43.152 ;
     RECT  36.744 43.116 36.816 43.152 ;
     RECT  36.84 43.116 36.912 43.152 ;
     RECT  36.936 43.116 37.008 43.152 ;
     RECT  37.032 43.116 37.104 43.152 ;
     RECT  37.128 43.116 37.2 43.152 ;
     RECT  37.224 43.116 37.296 43.152 ;
     RECT  37.32 43.116 37.392 43.152 ;
     RECT  37.416 43.116 37.488 43.152 ;
     RECT  37.512 43.116 37.584 43.152 ;
     RECT  37.608 43.116 37.68 43.152 ;
     RECT  37.704 43.116 37.776 43.152 ;
     RECT  37.8 43.116 37.872 43.152 ;
     RECT  37.896 43.116 37.968 43.152 ;
     RECT  37.992 43.116 38.064 43.152 ;
     RECT  38.088 43.116 38.16 43.152 ;
     RECT  38.184 43.116 38.256 43.152 ;
     RECT  38.28 43.116 38.352 43.152 ;
     RECT  38.376 43.116 38.448 43.152 ;
     RECT  38.472 43.116 38.544 43.152 ;
     RECT  38.568 43.116 38.64 43.152 ;
     RECT  38.664 43.116 38.736 43.152 ;
     RECT  38.76 43.116 38.832 43.152 ;
     RECT  38.856 43.116 38.928 43.152 ;
     RECT  38.952 43.116 39.024 43.152 ;
     RECT  39.048 43.116 39.12 43.152 ;
     RECT  39.144 43.116 39.216 43.152 ;
     RECT  39.24 43.116 39.312 43.152 ;
     RECT  39.336 43.116 39.408 43.152 ;
     RECT  39.432 43.116 39.504 43.152 ;
     RECT  39.528 43.116 39.6 43.152 ;
     RECT  39.624 43.116 39.696 43.152 ;
     RECT  39.72 43.116 39.792 43.152 ;
     RECT  39.816 43.116 39.888 43.152 ;
     RECT  39.912 43.116 39.984 43.152 ;
     RECT  40.008 43.116 40.08 43.152 ;
     RECT  40.104 43.116 40.176 43.152 ;
     RECT  40.2 43.116 40.272 43.152 ;
     RECT  40.296 43.116 40.368 43.152 ;
     RECT  40.392 43.116 40.464 43.152 ;
     RECT  40.488 43.116 40.56 43.152 ;
     RECT  40.584 43.116 40.656 43.152 ;
     RECT  40.68 43.116 40.752 43.152 ;
     RECT  40.776 43.116 40.848 43.152 ;
     RECT  40.872 43.116 40.944 43.152 ;
     RECT  40.968 43.116 41.04 43.152 ;
     RECT  41.064 43.116 41.136 43.152 ;
     RECT  41.16 43.116 41.232 43.152 ;
     RECT  41.256 43.116 41.328 43.152 ;
     RECT  41.352 43.116 41.424 43.152 ;
     RECT  41.448 43.116 41.52 43.152 ;
     RECT  41.544 43.116 41.616 43.152 ;
     RECT  41.64 43.116 41.712 43.152 ;
     RECT  41.736 43.116 41.808 43.152 ;
     RECT  41.832 43.116 41.904 43.152 ;
     RECT  41.928 43.116 42 43.152 ;
     RECT  42.024 43.116 42.096 43.152 ;
     RECT  42.12 43.116 42.192 43.152 ;
     RECT  42.216 43.116 42.288 43.152 ;
     RECT  42.312 43.116 42.384 43.152 ;
     RECT  42.408 43.116 42.48 43.152 ;
     RECT  42.504 43.116 42.576 43.152 ;
     RECT  42.6 43.116 42.672 43.152 ;
     RECT  42.696 43.116 42.768 43.152 ;
     RECT  42.792 43.116 42.864 43.152 ;
     RECT  42.888 43.116 42.96 43.152 ;
     RECT  42.984 43.116 43.056 43.152 ;
     RECT  43.08 43.116 43.152 43.152 ;
     RECT  43.176 43.116 43.248 43.152 ;
     RECT  43.272 43.116 43.344 43.152 ;
     RECT  43.368 43.116 43.44 43.152 ;
     RECT  43.464 43.116 43.536 43.152 ;
     RECT  43.56 43.116 43.632 43.152 ;
     RECT  43.656 43.116 43.728 43.152 ;
     RECT  43.752 43.116 43.824 43.152 ;
     RECT  43.848 43.116 43.92 43.152 ;
     RECT  43.944 43.116 44.016 43.152 ;
     RECT  44.04 43.116 44.88 43.152 ;
     RECT  44.904 43.116 44.976 43.152 ;
     RECT  45 43.116 45.072 43.152 ;
     RECT  45.096 43.116 45.168 43.152 ;
     RECT  45.192 43.116 45.264 43.152 ;
     RECT  45.288 43.116 45.36 43.152 ;
     RECT  45.384 43.116 45.456 43.152 ;
     RECT  45.48 43.116 45.552 43.152 ;
     RECT  45.576 43.116 45.648 43.152 ;
     RECT  45.672 43.116 45.744 43.152 ;
     RECT  45.768 43.116 45.84 43.152 ;
     RECT  45.864 43.116 45.936 43.152 ;
     RECT  45.96 43.116 46.032 43.152 ;
     RECT  46.056 43.116 46.128 43.152 ;
     RECT  46.152 43.116 46.224 43.152 ;
     RECT  46.248 43.116 46.32 43.152 ;
     RECT  46.344 43.116 46.416 43.152 ;
     RECT  46.44 43.116 46.512 43.152 ;
     RECT  46.536 43.116 46.608 43.152 ;
     RECT  46.632 43.116 46.704 43.152 ;
     RECT  46.728 43.116 46.8 43.152 ;
     RECT  46.824 43.116 46.896 43.152 ;
     RECT  46.92 43.116 46.992 43.152 ;
     RECT  47.016 43.116 47.088 43.152 ;
     RECT  47.112 43.116 47.184 43.152 ;
     RECT  47.208 43.116 47.28 43.152 ;
     RECT  47.304 43.116 47.376 43.152 ;
     RECT  47.4 43.116 47.472 43.152 ;
     RECT  47.496 43.116 47.568 43.152 ;
     RECT  47.592 43.116 47.664 43.152 ;
     RECT  47.688 43.116 47.76 43.152 ;
     RECT  47.784 43.116 47.856 43.152 ;
     RECT  47.88 43.116 47.952 43.152 ;
     RECT  47.976 43.116 48.048 43.152 ;
     RECT  48.072 43.116 48.144 43.152 ;
     RECT  48.168 43.116 48.24 43.152 ;
     RECT  48.264 43.116 48.336 43.152 ;
     RECT  48.36 43.116 48.432 43.152 ;
     RECT  48.456 43.116 48.528 43.152 ;
     RECT  48.552 43.116 48.624 43.152 ;
     RECT  48.648 43.116 48.72 43.152 ;
     RECT  48.744 43.116 48.816 43.152 ;
     RECT  48.84 43.116 48.912 43.152 ;
     RECT  48.936 43.116 49.008 43.152 ;
     RECT  49.032 43.116 49.104 43.152 ;
     RECT  49.128 43.116 49.2 43.152 ;
     RECT  49.224 43.116 49.296 43.152 ;
     RECT  49.32 43.116 49.392 43.152 ;
     RECT  49.416 43.116 49.488 43.152 ;
     RECT  49.512 43.116 49.584 43.152 ;
     RECT  49.608 43.116 49.68 43.152 ;
     RECT  49.704 43.116 49.776 43.152 ;
     RECT  49.8 43.116 49.872 43.152 ;
     RECT  49.896 43.116 49.968 43.152 ;
     RECT  49.992 43.116 50.064 43.152 ;
     RECT  50.088 43.116 50.16 43.152 ;
     RECT  50.184 43.116 50.256 43.152 ;
     RECT  50.28 43.116 50.352 43.152 ;
     RECT  50.376 43.116 50.448 43.152 ;
     RECT  50.472 43.116 50.544 43.152 ;
     RECT  50.568 43.116 50.64 43.152 ;
     RECT  50.664 43.116 50.736 43.152 ;
     RECT  50.76 43.116 50.832 43.152 ;
     RECT  50.856 43.116 50.928 43.152 ;
     RECT  50.952 43.116 51.432 43.152 ;
     RECT  46.368 43.152 46.392 43.187 ;
     RECT  51.408 43.152 51.432 43.187 ;
     RECT  7.992 0.016 9.12 0.132 ;
     RECT  7.944 0.132 9.168 2.151 ;
     RECT  12.168 2.137 13.2 5.699 ;
     RECT  8.112 2.151 9.168 2.915 ;
     RECT  8.112 2.915 9.264 4.213 ;
     RECT  6.96 3.443 7.44 4.501 ;
     RECT  8.232 4.213 9.264 4.405 ;
     RECT  4.008 4.693 5.184 5.605 ;
     RECT  5.208 4.789 6.528 4.981 ;
     RECT  5.496 4.981 6.528 5.989 ;
     RECT  11.688 5.699 13.2 6.275 ;
     RECT  10.152 12.659 10.248 13.669 ;
     RECT  2.304 14.867 2.4 15.973 ;
     RECT  0.168 15.923 0.216 16.933 ;
     RECT  59.592 16.741 60.96 16.979 ;
     RECT  59.256 16.979 60.96 17.989 ;
     RECT  17.664 17.891 18.6 18.757 ;
     RECT  29.712 17.989 30.72 19.093 ;
     RECT  30.744 17.989 32.064 19.573 ;
     RECT  59.256 17.989 60.912 18.181 ;
     RECT  0.24 18.035 0.48 19.285 ;
     RECT  59.688 18.181 60.912 18.757 ;
     RECT  17.352 18.757 18.6 20.629 ;
     RECT  59.784 18.757 60.912 19.477 ;
     RECT  18.912 19.141 19.968 19.909 ;
     RECT  59.928 19.715 60.912 20.435 ;
     RECT  59.784 20.435 60.912 21.589 ;
     RECT  31.32 21.155 32.4 21.683 ;
     RECT  31.32 21.683 32.496 22.741 ;
     RECT  0.168 21.779 0.216 23.269 ;
     RECT  31.32 22.741 32.352 23.125 ;
     RECT  60.696 24.419 61.8 25.525 ;
     RECT  60.696 25.525 61.68 25.861 ;
     RECT  60.552 26.051 61.68 27.395 ;
     RECT  24.504 26.293 25.872 26.819 ;
     RECT  60.552 27.395 61.8 29.077 ;
     RECT  26.472 28.165 27.888 29.365 ;
     RECT  60.648 29.077 61.8 30.899 ;
     RECT  10.344 29.795 10.392 30.613 ;
     RECT  10.344 30.613 11.424 31.475 ;
     RECT  60.552 30.899 61.8 33.733 ;
     RECT  10.296 31.475 11.424 32.437 ;
     RECT  11.688 32.341 13.2 39.349 ;
     RECT  24.312 32.485 25.68 41.049 ;
     RECT  60.552 33.923 61.8 34.835 ;
     RECT  4.776 34.787 5.76 35.171 ;
     RECT  60.456 34.835 61.8 35.939 ;
     RECT  4.776 35.171 6.192 36.659 ;
     RECT  59.112 35.363 60.192 35.795 ;
     RECT  58.92 35.795 60.192 37.091 ;
     RECT  60.36 35.939 61.8 35.987 ;
     RECT  12.072 39.349 13.2 40.453 ;
     RECT  2.712 39.923 3.696 39.971 ;
     RECT  54.84 39.923 55.824 40.499 ;
     RECT  12.168 40.453 13.2 41.063 ;
     RECT  57.912 40.547 58.896 40.595 ;
     RECT  12.168 41.063 12.456 41.605 ;
  END
END qkd_astk_er_tap
END LIBRARY
